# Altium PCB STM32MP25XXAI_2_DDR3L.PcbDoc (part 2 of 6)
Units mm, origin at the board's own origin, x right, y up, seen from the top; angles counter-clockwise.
Board outline 172 x 137 mm, 6 copper layers (Top Layer, Signal Layer 1, Signal Layer 2, Signal Layer 3, Signal Layer 4, Bottom Layer), stack 2.079 mm thick; 237 components, 152 nets, 1304 pads, 909 vias.
Unrouted connection lines stored in the file: 13.

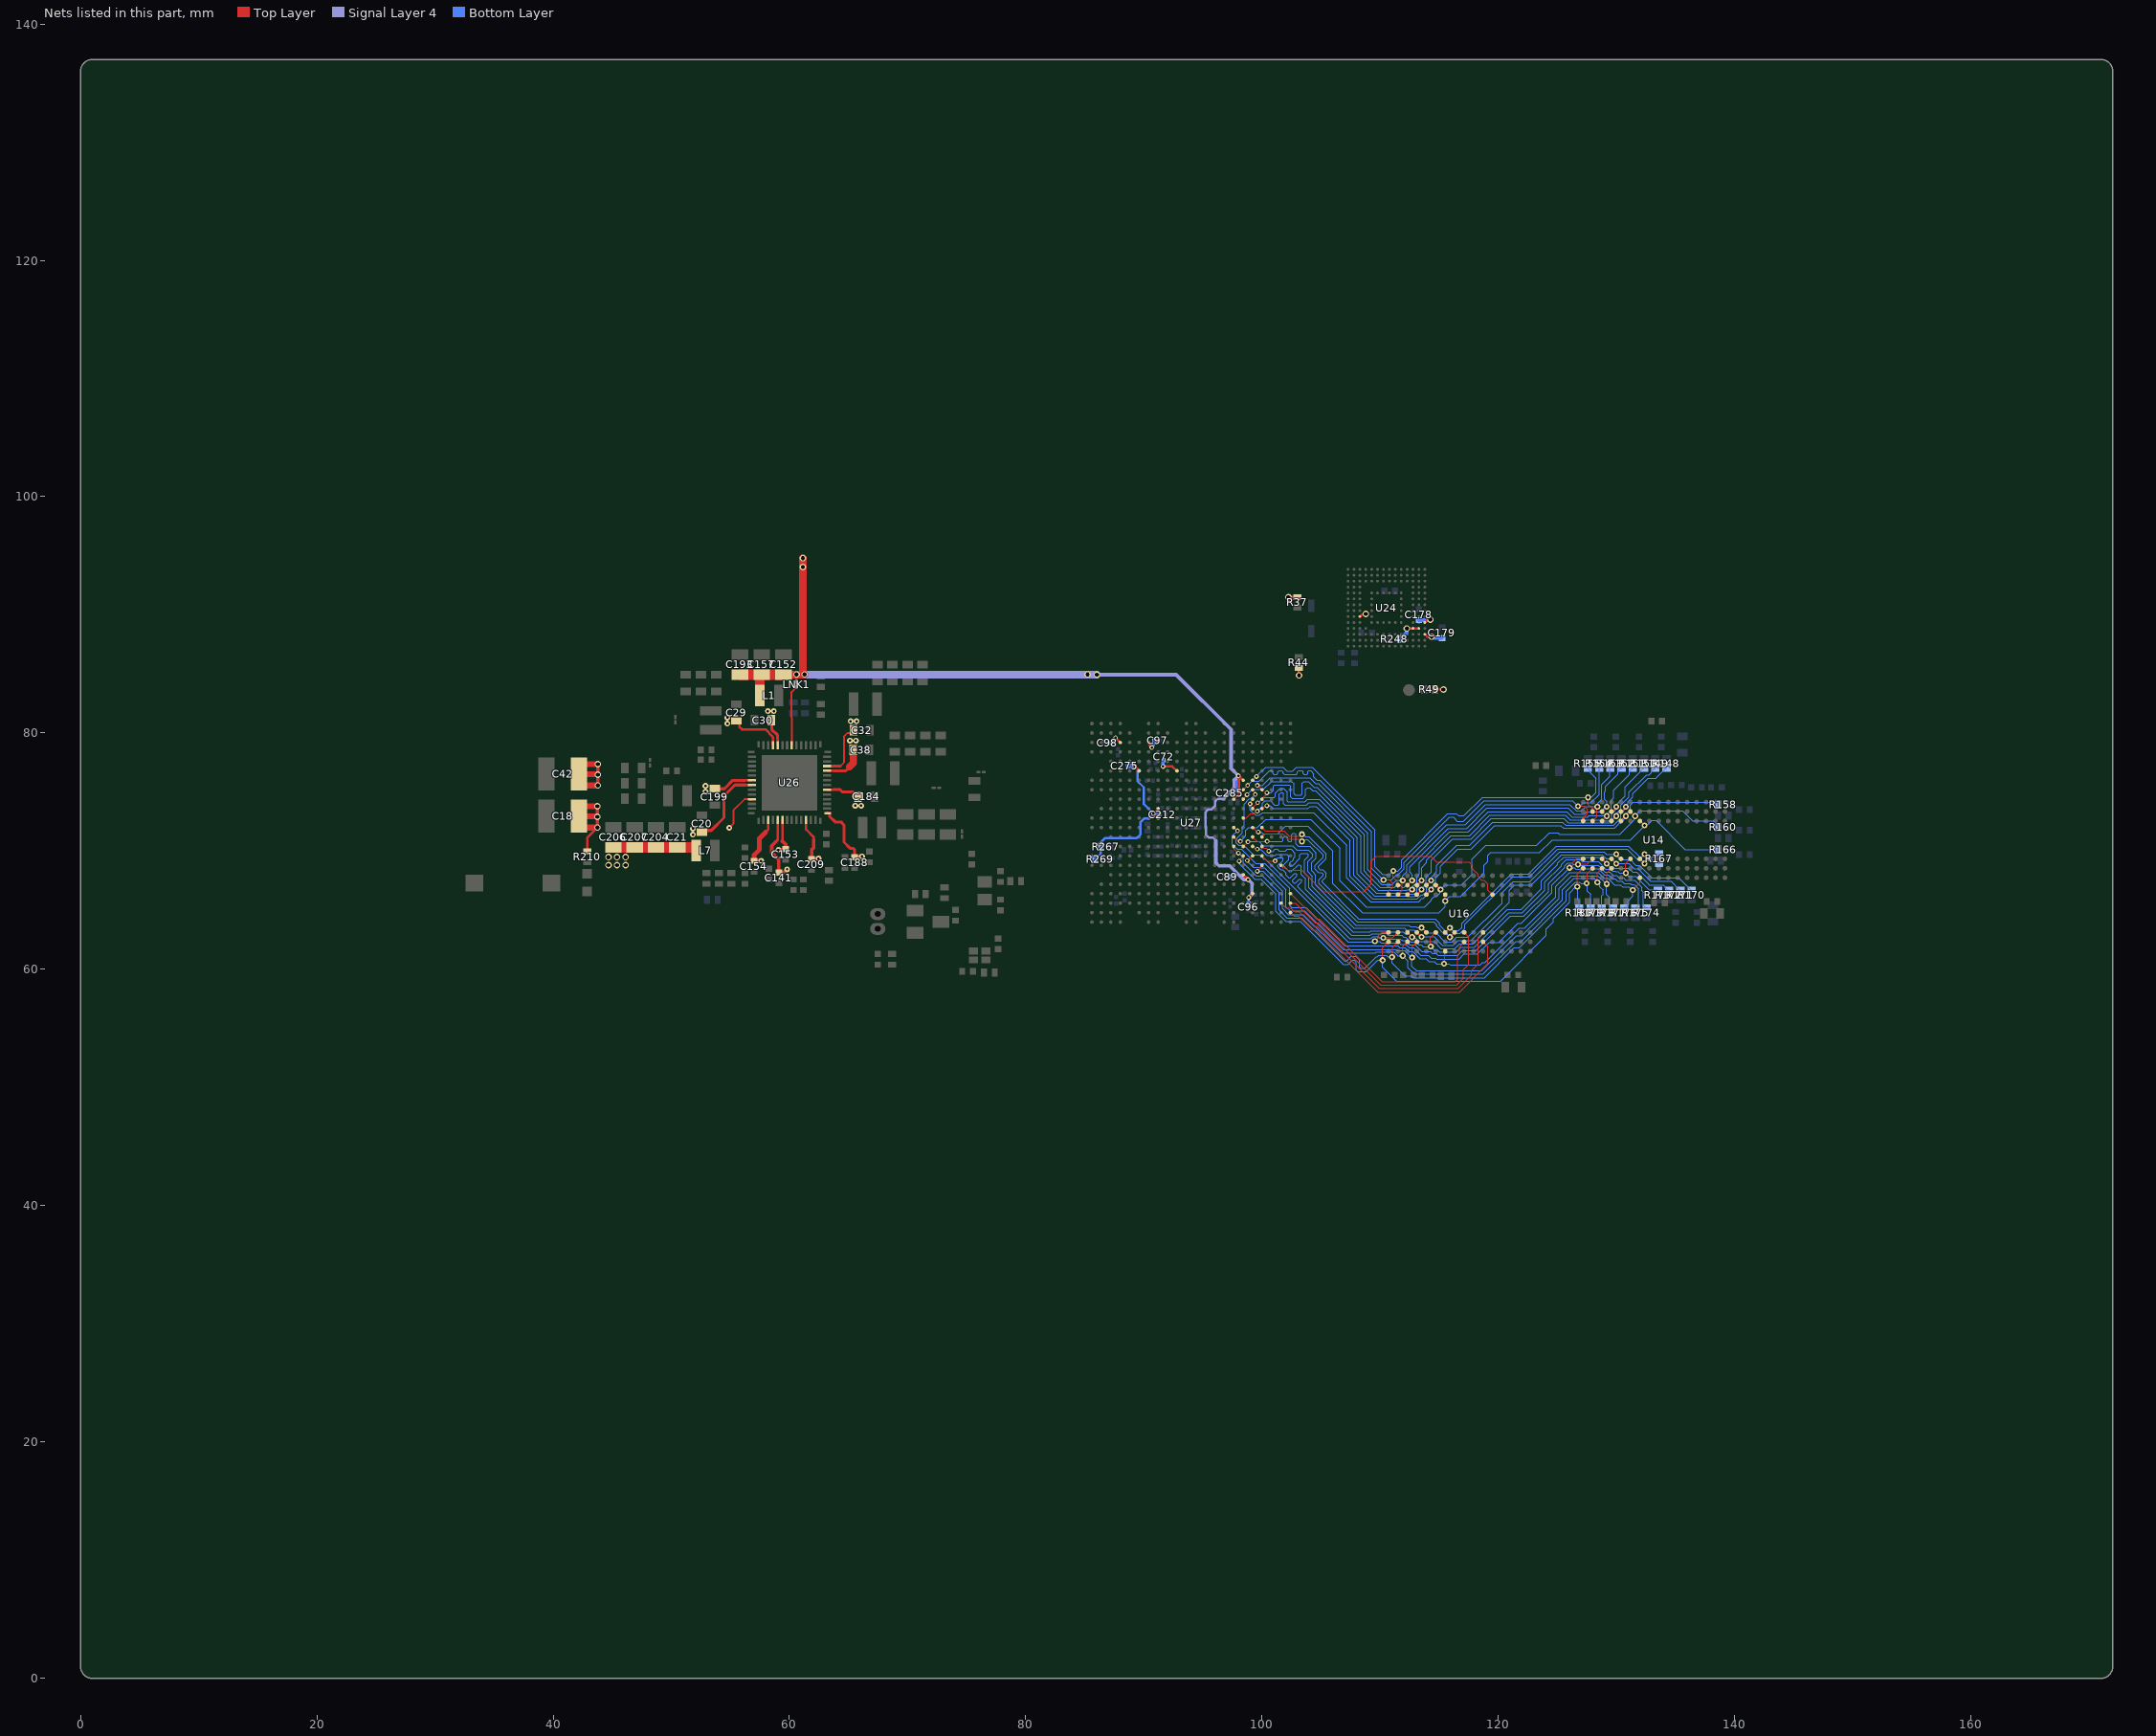
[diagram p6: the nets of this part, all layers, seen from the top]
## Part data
B2: library part MCD-03492, "Switch tactile, SPST-NO, 50mA, 12V, 6x3.8mm", Manufacturer="WURTH ELEKTRONIK", Manufacturer_Part_Number=434121025816, Package=6x3.8mm
C1 C2 C3 C4 C5 C6 C7 C8 C9 C10 C11 C12 C13 C14 C15 C16 C17 C25 C31 C44 C45 C46 C47 C52 C53 C54 C55 C56 C57 C58 C59 C60 C67: library part MCD-02377, "Capacitor, MLCC, 1uF, 6.3V, X5R, +/-20%, 0201, T=0,3mm", Alternate_Manufacturer=N/A, Manufacturer=MURATA, Manufacturer_Part_Number=GRM033R60J105MEA2, Package=0201
C18 C42: library part MCD-01796, "Capacitor, Tantalum, 100uF, 6V3, 40mR, +/-20%,  Type_B (3528 metric), T=1.9mm", Manufacturer=AVX, Manufacturer_Part_Number=TCJB107M006R0040, Package="3528 (metric)"
C19 C21 C152 C157 C186 C187 C193 C204 C206 C207: library part MCD-03139, "Capacitor, MLCC, 22uF, 10V, X5R, +/-20%, 0805, T=1,25mm", Manufacturer=MURATA, Manufacturer_Part_Number=GRM21BR61A226ME51L, Package=0805
C20 C29 C30 C32 C38 C184 C199: library part MCD-00099, "Capacitor, MLCC, 10uF, 10V, X5R, +/-10%, 0603, T=0,8mm", Alternate_Manufacturer=N/A, Manufacturer=MURATA, Manufacturer_Part_Number=GRM188R61A106KE69D, Package=0603
C22 C23 C24 C26 C27 C28 C34 C35 C36 C37 C41 C183 C200 C202: library part MCD-00100, "Capacitor, MLCC, 22uF, 6V3, X5R, +/-20%, 0603, T=0,8mm", Alternate_Manufacturer=N/A, Manufacturer=MURATA, Manufacturer_Part_Number=GRM188R60J226MEA0J, Package=0603
C33: library part MCD-00011, "Capacitor, MLCC, 10nF, 16V, X7R, 10%, 0402, T=0.5mm", Manufacturer=YAGEO, Manufacturer_Part_Number=CC0402KRX7R7BB103, Package=0402
C39 C40: library part MCD-03140, "Capacitor, MLCC, 10uF, 6.3V, X5R, +/-20%, 0402, T=0.5mm", Manufacturer=MURATA, Manufacturer_Part_Number=GRM155R60J106ME05D, Package=0402
C43 C153 C154 C188: library part MCD-00095, "Capacitor, MLCC, 1uF, 25V, X5R, +/-10%, 0402, T=0.5mm", Manufacturer=MURATA, Manufacturer_Part_Number=GRM155R61E105KA12, Package=0402
C48 C76 C77 C131 C132 C133 C134 C143 C146 C147 C148 C149 C159 C172 C177 C179 C182 C185 C191 C192 C194 C201 C205 C302 C304 C306 C307 C360 C361 C362 C363 C367 C373 C374 C375 C384 C390: library part MCD-00006, "Capacitor, MLCC, 100nF, 16V, X7R, +/-10%, 0402, T=0.5mm", Alternate_Manufacturer=MURATA, Alternate_Manufacturer_Part_Number=GCM155R71C104KA55D, Manufacturer=YAGEO, Manufacturer_Part_Number=CC0402KRX7R7BB104, Package=0402
C61: library part MCD-01534, "Capacitor, MLCC, 4,7uF, 6V3, X5R, +/-20%, 0201, T=0.5mm", Alternate_Manufacturer=N/A, Manufacturer=MURATA, Manufacturer_Part_Number=GRM035R60J475ME15, Package=0201
C62 C63 C64 C65 C66 C68 C69 C70 C71 C72 C73 C74 C75 C89 C96 C97 C98 C212 C234 C275 C285: library part MCD-01535, "Capacitor, MLCC,100nF, 10V, X7R, +/-10%, 0201, T=0.3mm", Alternate_Manufacturer=N/A, Manufacturer=MURATA, Manufacturer_Part_Number=GRM033R61A104KE15, Package=0201
C79: library part MCD-02235, "Capacitor, MLCC, 2.2uF, 10V, X5R,+/-10%, 0201, T=0.5mm", Manufacturer=MURATA, Manufacturer_Part_Number=GRM033R61A225KE47D, Package=0201
C80 C140 C173 C364: library part MCD-00099, "Capacitor, MLCC, 10uF, 10V, X5R, +/-10%, 0603, T=0.8mm", Alternate_Manufacturer=N/A, Manufacturer=MURATA, Manufacturer_Part_Number=GRM188R61A106KE69D, Package=0603
C81 C86 C90 C92: library part MCD-00674, "Capacitor, MLCC, 6.8pF, 50V, NPO, +-0.25pF, 0402, T=0.5mm", Alternate_Manufacturer=N/A, Manufacturer=YAGEO, Manufacturer_Part_Number=CC0402CRNPO9BN6R8, Package=0402
C87: library part MCD-00006, "Capacitor,100nF,16V,X7R,10%,0402", Alternate_Manufacturer=MURATA, Alternate_Manufacturer_Part_Number=GCM155R71C104KA55D, Manufacturer=YAGEO, Manufacturer_Part_Number=CC0402KRX7R7BB104, Package=0402
C88: library part MCD-01823, "Capacitor, MLCC, 2.2uF, 6V3, X5R,+/-10%, 0402, T=0.5mm", Alternate_Manufacturer=N/A, Manufacturer=MURATA, Manufacturer_Part_Number=GRM155R60J225KE95D, Package=0402
C91 C141 C142 C156 C189 C190 C208 C209 C217: library part MCD-01356, "Capacitor, MLCC, 4.7uF, 6V3, X5R, +/-20%, 0402, T=0.5mm", Manufacturer=MURATA, Manufacturer_Part_Number=GRM155R60J475ME47, Package=0402
C130 C399: library part MCD-00099, "Capacitor, MLCC, 10uF, 10V, X5R, +/-10%, 0603, T=0.8mm", Manufacturer=MURATA, Manufacturer_Part_Number=GRM188R61A106KE69D, Package=0603
C155: library part MCD-02198, "Capacitor, MLCC, 10nF, 50V, X7R, +/-10%, 0402, T=0.5mm", Manufacturer=YAGEO, Manufacturer_Part_Number=CC0402KRX7R9BB103, Package=0402
C178 C180 C181: library part MCD-02606, "Capacitor, MLCC, 2.2uF, 6.3V, X5R, +/-10%, 0402, T=0.5mm", Manufacturer=YAGEO, Manufacturer_Part_Number=CC0402KRX5R5BB225, Package=0402
CN12: library part MCD-00655, "Header 2 circuits, 1.25mm Pitch ,  Vertical, with Friction Lock", Alternate_Manufacturer=N/A, Manufacturer=MOLEX, Manufacturer_Part_Number=53047-0210
D5: library part MCD-00034, Manufacturer=STMICROELECTRONICS, Manufacturer_HQ_COO=EU, Package=SOD323
D6: library part MCD-03280, "Diode, Schottky, Dual Common Cathode, 0V3, 300mA, 40V, SOT-23", Manufacturer=STMICROELECTRONICS, Manufacturer_Part_Number=BAT54CFILM, Package=SOT23
L1 L6: library part MCD-03143, "Inductor, 2.2uH, +/-20%, Itemp= 1700mA, Isat= 2400mA, 0R140, 0806, T=1mm", Manufacturer=MURATA, Manufacturer_Part_Number=DFE201610E-2R2M{}P2, Package=0806
L2 L4: library part MCD-03142, "Inductor, 0.68uH, +/-20%, Itemp= 3900mA, Isat= 5400mA, 0R031, 1008, T=1.2mm", Manufacturer=MURATA, Manufacturer_Part_Number=DFE252012F-R68M{}P2, Package=1008
L3 L5 L7: library part MCD-03141, "Inductor, 0.68uH, +/-20%, Itemp= 3100mA, Isat= 4300mA, 0R043, 0806, T=1mm", Manufacturer=MURATA, Manufacturer_Part_Number=DFE201610E-R68M{}P2, Package=0806
LD11: library part MCD-00588, "LED Green, 0603 SMD, Forward Voltage Typ=2V, Max=2.5V", Alternate_Manufacturer="VISHAY SEMICONDUCTOR OPTO DIVISION", Alternate_Manufacturer_Part_Number=VLMTG1300-GS08, Manufacturer="OSRAM OPTO SEMICONDUCTORS", Manufacturer_Part_Number="LG Q396-PS-35", Package=0603
LNK1 LNK2 LNK4 LNK7 LNK8 LNK11: library part MCD-02777, "Track link on PCB 200um width for layout routing", Manufacturer=N/A
R2 R46 R57 R59 R60 R64 R75 R81 R267 R269 R286: library part MCD-00052, "Resistor,0R,0402,5%,1/16W", Alternate_Manufacturer=N/A, Manufacturer=YAGEO, Manufacturer_Part_Number=RC0402JR-070RL, Package=0402
R27 R272: library part MCD-00053, "Resistor,10K,0402,1%,1/16W", Alternate_Manufacturer=N/A, Manufacturer=YAGEO, Manufacturer_Part_Number=RC0402FR-0710KL, Package=0402
R37 R44 R49 R156 R248: library part MCD-00053, "Resistor,10K,0402,1%,1/16W", Manufacturer=YAGEO, Manufacturer_Part_Number=RC0402FR-0710KL, Package=0402
R66: library part MCD-00058, "Resistor, 20R, 0402, +/-1%, 1/16W", Alternate_Manufacturer=N/A, Manufacturer=YAGEO, Manufacturer_Part_Number=RC0402FR-0720RL, Package=0402
R67: library part MCD-00052, "Resistor, 0R, 0402, +/-5%, 1/16W", Manufacturer=YAGEO, Manufacturer_Part_Number=RC0402JR-070RL, Package=0402
R68 R83: library part MCD-00120, "Resistor,240R,0402,1%,1/16W", Manufacturer=YAGEO, Manufacturer_Part_Number=RC0402FR-07240RL, Package=0402
R148 R149 R150 R151 R152 R153 R154 R155 R158 R159 R160 R163 R166 R168 R170 R171 R172 R173 R174 R175 R176 R177 R178 R179 R180: library part MCD-00054, "Resistor, 56R, 0402, +/-1%, 1/16W", Alternate_Manufacturer=N/A, Manufacturer=YAGEO, Manufacturer_Part_Number=RC0402FR-0756RL, Package=0402
R167: library part MCD-01819, "Resistor,100R,0402,0,5%,1/16W,±100ppm/°C", Manufacturer=YAGEO, Manufacturer_Part_Number=RC0402DR-07100RL, Package=0402
R210: library part MCD-00441, "Resistor,270R,0402,1%,1/16W", Manufacturer=YAGEO, Manufacturer_Part_Number=RC0402FR-07270RL, Package=0402
R249: library part MCD-00056, "Resistor, 0R, 0603, +/-5%, 1/10W", Manufacturer=YAGEO, Manufacturer_Part_Number=RC0603JR-070RL, Package=0603
R260 R261: library part MCD-00068, "Resistor,1K5,0402,1%,1/16W", Manufacturer=YAGEO, Manufacturer_Part_Number=RC0402FR-071K5L, Package=0402
R262: library part MCD-02253, "Resistor,240R,0201,1%,1/20W", Alternate_Manufacturer=N/A, Manufacturer=YAGEO, Manufacturer_Part_Number=RC0201FR-07240RL, Package=0201
TP9: library part MCD-00074, "Test Point 1mm", Manufacturer=n/a, Manufacturer_HQ_COO=Unknown
U14 U16: library part MCD-01811, "Memory,DDR3L,4Gb,256Mbx16,933Mhz,1V35,TFBGA", Manufacturer=NANYA, Package=VFBGA-96
U24: library part MCD-02799, "Memory, eMMC, 4GB, 15nm ,WFBGA , 153 pins", Manufacturer=KIOXIA, Manufacturer_Part_Number=THGBMTG5D1LBAIL, Package=WFBGA153
U26: library part MCD-03000, "STPMIC2", Manufacturer=STMICROELECTRONICS, Package=VQFN
U27: library part MCD-02000, "MPU, ARM Cortex-A35 + M33 32-bit MPU, 808KB RAM, With Crypto", Manufacturer=STMICROELECTRONICS, Manufacturer_HQ_COO=EU, Package=LFBGA-436
X1: library part MCD-01479, "Crystal, 32.768kHz, 6pF, +/-20ppm, 80K, 2.05x1.2mm", Manufacturer=NDK, Manufacturer_Part_Number=NX2012SA-32.768KHZ-EXS00A-MU00527, Package=2.05x1.2mm
X2: library part MCD-02344, "Crystal, 40MHz, 6pF, +/-20ppm, 80R, 1.6x1.2mm", Manufacturer=NDK, Manufacturer_Part_Number=NX1612SA-40MHZ-EXS00A-CS13836, Package=1.6x1.2mm

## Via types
v1: diameter 0.55, hole 0.35, Top Layer to Bottom Layer, 421 vias
v2: diameter 0.4, hole 0.2, Top Layer to Bottom Layer, tented both sides, 169 vias
v3: diameter 0.5, hole 0.2, Top Layer to Bottom Layer, 146 vias
v4: diameter 0.5, hole 0.25, Top Layer to Bottom Layer, 145 vias
v5: diameter 0.4, hole 0.2, Top Layer to Bottom Layer, 28 vias

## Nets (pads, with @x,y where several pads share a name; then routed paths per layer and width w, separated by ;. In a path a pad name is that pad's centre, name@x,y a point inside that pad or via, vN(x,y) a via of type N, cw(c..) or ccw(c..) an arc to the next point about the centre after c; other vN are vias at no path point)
1V8: C72.2 C89.2 C96.2 C97.2 C98.2 C152.2 C157.2 C178.2 C179.2 C193.2 C212.2 C275.2 C285.2 L1.2 LNK1.2 R37.2 R44.2 R49.2 R248.2 R267.2 R269.1 U24.C6 U24.M4 U24.N4 U24.P3 U24.P5 U27.C4 U27.C7 U27.F6 U27.F10 U27.G17 U27.J16 U27.K8 U27.L8 U27.U17 U27.W18 | length 110.6
  Top Layer w0.2: LNK1.2@60.6,84.348 v1(60.6,84.95) ; v2(87.6,79.6) U27.C4@88,79.2 v2(87.6,79.6) ; v2(89.2,77.2) U27.F6@89.6,76.8 ; U27.C7@90.4,79.2 90.415,79.185 90.415,79.02 v2(90.66,78.775) ; U27.L8@91.2,72.8 91.175,72.8 v2(90.8,73.175) 91.2,73.575 U27.K8@91.2,73.6 ; v2(91.624,77.173) 92.413,77.173 92.786,76.8 U27.F10@92.8,76.8 ; U27.J16@97.6,74.4 98,74.8 v2(98,76.375) 98.012,76.375 98.388,76 U27.G17@98.4,76 ; U27.U17@98.4,68 v2(98.8,67.6) ; v2(98.868,66.067) U27.W18@99.2,66.4 ; v1(102.23,91.5) R37.2@102.975,91.5 ; R44.2@103.1,85.528 103.125,85.503 v1(103.125,84.875) ; U24.C6@108.275,89.85 108.452,90.027 108.727,90.027 v1(108.775,90.075) ; v1(112.25,88.85) U24.M4@112.775,88.85 U24.N4@113.275,88.85 ; U24.P3@113.775,88.35 113.975,88.15 v1(114.35,88.15) ; U24.P5@113.775,89.35 114.005,89.58 114.23,89.58 v1(114.25,89.6) ; R49.2@114.625,83.685 v1(115.35,83.685)
  Top Layer w0.64: C152.2@59.5,84.95 v1(60.6,84.95) v1(61.28,84.95) 61.142,85.088 v1(61.142,94.8)
  Top Layer w0.8: L1.2@57.495,83.175 57.495,84.9 57.545,84.95 C157.2@57.65,84.95
  Top Layer w0.9: C193.2@55.8,84.95 C157.2@57.545,84.95 ; C157.2@57.65,84.95 C152.2@59.5,84.95
  Signal Layer 4 w0.2: 96.075,70.9 95.825,71.15 95.484,71.15 95.399,71.235 95.248,71.386 95.248,72.063 95.201,72.109 95.201,73.292 95.317,73.408 95.317,73.433 95.434,73.55 95.723,73.55 96.007,73.834 96.007,74.166 96.003,74.169 96.257,74.423 96.684,74.423 ; v2(98.868,66.067) v2@98.868,66.094
  Signal Layer 4 w0.3: v1(86.019,84.939) 92.721,84.939 97.371,80.289 97.371,77.004 v2(98,76.375) ; 96.075,70.9 96.075,69.048 96.075,69.014 96.339,68.75 97.262,68.75 98.412,67.6 v2(98.8,67.6) ; 96.684,74.423 97.65,75.389 97.65,76.018 v2@98,76.367 ; v2(98.8,67.6) 99.15,67.25 99.15,66.377 v2@98.868,66.094
  Signal Layer 4 w0.64: v1@60.6,84.955 v1@61.28,84.955 ; v1(61.28,84.95) 86.009,84.95 v1(86.019,84.939)
  Bottom Layer w0.17: C89.2@97.35,67.825 97.415,67.89 97.44,67.89 97.56,68.01 98.39,68.01 v2(98.8,67.6)
  Bottom Layer w0.2: R269.1@85.854,69.315 85.854,69.41 86.009,69.565 86.104,69.565 86.35,69.811 R267.2@86.35,70.375 ; R267.2@86.325,70.715 86.697,71.087 89.377,71.087 89.723,71.434 89.723,72.448 90.059,72.783 90.457,72.783 90.8,73.127 v2(90.8,73.175) ; v2(89.2,77.2) 89.458,76.942 89.458,75.927 89.985,75.4 89.985,73.99 v2(90.8,73.175) ; v2(90.66,78.775) 90.66,78.79 90.825,78.955 C97.2@90.825,79.375 ; C212.2@91.31,73.1 91.272,73.138 90.837,73.138 v2(90.8,73.175) ; C96.2@98.85,65.55 98.85,66.05 v2(98.868,66.067)
  Bottom Layer w0.3: C98.2@87.175,79.175 v2(87.6,79.6) ; C72.2@91.6,77.7 91.6,77.224 91.624,77.2 v2(91.624,77.173) ; C285.2@97.555,74.91 97.94,75.295 97.94,76.288 98,76.348 v2(98,76.375) ; R248.2@111.675,87.95 112.241,88.516 112.241,88.841 v1(112.25,88.85) ; C178.2@113.275,89.55 114.132,89.55 114.182,89.6 v1(114.25,89.6) ; v1(114.35,88.15) 114.418,88.15 114.543,88.025 C179.2@115.225,88.025
  Bottom Layer w0.4: C275.2@88.675,77.2 v2(89.2,77.2)
  other v1: 85.224,84.95 61.131,94.047
1V8_FB: LNK1.1 U26.35 | length 5.1
  Top Layer w0.15: U26.35@60.2,78.97 60.2,81.311 60.175,81.336 60.175,83.473 LNK1.1@60.6,83.898
3V3: C21.2 C154.2 C204.2 C206.2 C207.2 L7.2 U26.3 U26.53 | length 15.3
  Top Layer w0.15: v3(54.91,71.977) 55.262,72.329 55.262,73.465 56.197,74.4 U26.53@56.83,74.4 ; U26.53@56.62,74.369 56.919,74.369 U26.53@56.95,74.4
  Top Layer w0.21: 57.973,71.598 58.2,71.825 U26.3@58.2,72.63
  Top Layer w0.3: C154.2@56.975,69.175 C154.2@57,69.175 v3@57.585,69.175
  Top Layer w0.4: C154.2@57,69.175 57.014,69.189 57.014,69.685 57.46,70.131 57.46,71.085 57.973,71.598
  Top Layer w0.9: C206.2@45.087,70.323 C21.2@50.5,70.323 51.862,70.323 L7.2@51.887,70.298
  other v1: 44.687,68.823 45.412,68.823 46.137,68.823 44.687,69.498 45.412,69.498 46.137,69.498
  other v3: 57.61,69.175
5V_STLK: C18.1 C20.2 C29.2 C30.2 C32.2 C38.2 C42.1 C153.2 C184.2 C188.2 C199.2 C209.2 R210.1 U26.6 U26.11 U26.15 U26.20 U26.24 U26.25 U26.38 U26.39 U26.49 U26.50 | length 56.5
  Top Layer w0.15: 64.3,77.2 64.625,77.525 64.625,79.731 64.888,79.994 65.319,79.994 C32.2@65.425,80.1
  Top Layer w0.2: R210.1@42.887,69.97 42.887,71.138 v1(43.751,72.002)
  Top Layer w0.21: C29.2@55.525,81.05 55.762,80.813 55.762,80.513 55.975,80.3 57.964,80.3 58.6,79.664 U26.39@58.6,78.97 ; 56.275,75.6 U26.50@56.83,75.6 ; 56.275,76 U26.49@56.83,76 ; U26.38@59,78.97 59,79.525 ; 59.4,70.85 U26.6@59.4,72.63 ; U26.11@61.4,72.63 61.4,71.843 62.04,71.203 62.04,70.975 ; U26.15@63.17,73.2 U26.15@63.245,73.2 U26.15@63.285,73.2 ; U26.20@63.17,75.2 63.725,75.2 ; U26.24@63.17,76.8 63.725,76.8 ; U26.25@63.17,77.2 64.3,77.2
  Top Layer w0.25: C20.2@52.6,71.75 53.375,71.75 54.45,72.825 54.45,74.669 55.381,75.6 56.275,75.6 ; C199.2@53.675,75.275 54.491,75.275 55.216,76 56.275,76 ; C30.2@58.425,81.075 58.494,81.006 58.494,80.308 59,79.802 59,79.525 ; 63.395,73.095 63.395,72.947 63.871,72.472 64.353,72.472 64.625,72.2 64.625,70.759 65.134,70.25 65.379,70.25 65.525,70.104 C188.2@65.525,69.55 ; 63.725,75.2 64.288,75.2 64.463,75.025 65.347,75.025 65.472,74.9 65.55,74.9 65.747,74.703 C184.2@65.747,74.625 ; 63.725,76.8 64.75,76.8 65.075,77.125
  Top Layer w0.3: v1(43.751,72.002) v1(43.751,72.902) v1(43.751,73.802) ; v1(43.776,75.565) v1(43.776,76.465) v1(43.776,77.365) ; v3(59.065,70.11) 59.675,70.11 59.674,70.111 59.674,70.576 59.4,70.85 ; C209.2@61.85,69.38 C209.2@61.875,69.38 ; 62.04,70.975 62.04,70.269 61.875,70.104 C209.2@61.875,69.38 ; v3(62.46,69.38) C209.2@61.875,69.38 ; C188.2@65.525,69.55 v3(66.135,69.55)
  Top Layer w0.5: C18.1@42.187,72.049 42.235,72.002 v1(43.751,72.002) ; C18.1@42.187,72.961 43.679,72.961 43.737,72.902 v1(43.751,72.902) ; C42.1@42.187,75.612 42.235,75.565 v1(43.776,75.565) ; C42.1@42.187,76.523 43.704,76.523 43.762,76.465 v1(43.776,76.465) ; C18.1@42.246,73.802 v1(43.751,73.802) ; C42.1@42.246,77.365 v1(43.776,77.365)
  Top Layer w0.6: 65.075,77.125 65.4,77.45 C38.2@65.4,78.175
  other v3: 51.825,71.4 51.825,71.9 65.575,73.85 66.075,73.85 52.9,75.025 52.9,75.525 65.125,79.35 65.625,79.35 54.75,80.8 65.175,81 65.675,81 54.75,81.3 58.175,81.85 58.675,81.85
5V_VCONN: C141.1 U26.5 | length 5.7
  Top Layer w0.21: 58.877,70.828 59,70.95 U26.5@59,72.63
  Top Layer w0.3: 58.877,70.828 58.51,70.46 58.51,69.865 59.1,69.275 C141.1@59.1,68.2 59.539,68.2 v3(59.8,68.46)
DDR_A0: R149.1 U14.N3 U16.N3 U27.L17 | length 50.4
  Top Layer w0.09: U27.L17@98.4,72.8 98.673,72.8 99.037,73.164 99.374,73.164 v5(99.6,73.39) ; U16.N3@113.101,66.327 113.101,66.376 v4@113.5,66.775 ; U14.N3@129.576,72.552 129.576,72.601 v4@129.975,73
  Bottom Layer w0.09: v5@99.603,73.39 100.016,73.803 100.016,74.043 100.219,74.246 100.712,74.246 101.058,73.9 101.348,73.9 101.443,73.995 101.443,74.811 101.603,74.971 101.748,74.971 101.833,74.886 101.833,74.017 101.95,73.9 103.774,73.9 103.962,74.088 104.682,74.088 105.043,73.727 ; 105.05,73.734 107.755,71.029 107.755,67.967 109.502,66.22 112.251,66.22 112.32,66.151 112.967,66.151 113.5,66.685 v4(113.5,66.745) 113.5,66.818 113.715,67.033 113.715,67.097 113.895,67.277 113.895,67.808 114.336,68.25 114.336,69.245 116.116,71.025 117.679,71.025 119.404,72.75 125.544,72.75 125.912,72.382 129.422,72.382 129.975,72.935 v4(129.975,72.97) v4@129.975,73 ; v4@129.976,73.013 129.976,73.139 130.37,73.534 130.37,73.908 131.064,74.602 131.064,74.979 132.537,76.452 132.751,76.452 132.971,76.672 132.971,76.767 133.181,76.977 R149.1@133.276,76.977
DDR_A1: R172.1 U14.P7 U16.P7 U27.P19 | length 48.6
  Top Layer w0.09: U27.P19@100.005,70.4 100.168,70.237 100.338,70.237 v5(100.575,70) ; U16.P7@112.301,63.127 v4(112.7,62.725) ; U14.P7@128.776,69.352 v4@129.176,68.952
  Bottom Layer w0.09: v5(100.575,70) 100.585,69.99 100.909,69.99 101.096,70.177 101.282,70.177 101.432,70.027 101.968,70.027 102.118,70.177 102.453,70.177 102.802,69.827 102.802,69.539 102.652,69.388 102.652,69.283 102.349,68.98 102.349,68.846 102.424,68.772 102.566,68.772 103.197,69.402 103.197,69.689 103.327,69.82 103.784,69.82 103.903,69.7 103.903,69.576 103.586,69.258 103.586,68.134 103.953,67.766 103.953,66.903 107.68,63.177 109.148,63.177 109.231,63.26 110.6,63.26 110.683,63.177 111.946,63.177 112.101,63.022 112.406,63.022 v4@112.672,62.756 ; v4@112.685,62.769 112.7,62.754 112.7,62.728 v4(112.7,62.725) 112.763,62.662 113.002,62.662 113.32,62.344 114.55,62.344 115.145,61.75 116.304,61.75 116.711,62.157 117.833,62.157 120.761,65.085 121.919,65.085 123.64,66.806 123.64,67.493 125.03,68.884 125.03,68.984 125.538,69.492 128.592,69.492 129.134,68.95 v4(129.175,68.95) 129.175,68.931 129.439,68.667 129.669,68.667 129.782,68.554 131.028,68.554 131.372,68.211 131.69,68.211 132.659,67.242 132.673,67.242 132.765,67.15 133.959,67.15 134.145,66.964 134.145,66.905 R172.1@134.45,66.6
DDR_A2: R151.1 U14.P3 U16.P3 U27.J19 | length 47.1
  Top Layer w0.09: U27.J19@100,74.4 100,74.438 100.341,74.779 100.341,74.891 v5(100.4,74.95) ; U16.P3@112.301,66.327 112.7,66.726 v4(112.7,66.745) ; U14.P3@128.776,72.552 129.175,72.951 v4(129.175,72.97)
  Bottom Layer w0.09: v5@100.403,74.95 100.747,74.95 100.95,75.153 100.95,75.501 101.051,75.602 102.305,75.602 102.413,75.494 102.413,74.594 102.527,74.48 103.461,74.48 103.689,74.708 103.689,75.224 103.824,75.359 104.044,75.359 104.287,75.115 104.517,75.115 108.355,71.278 108.355,68.187 109.842,66.7 112.213,66.7 112.258,66.745 v4(112.7,66.745) 112.778,66.823 112.778,67.042 113.095,67.358 113.095,67.845 113.168,67.918 113.168,67.92 113.3,68.052 113.3,69.057 ; 113.299,69.057 115.867,71.625 117.43,71.625 119.155,73.35 125.793,73.35 126.241,72.902 127.573,72.902 127.668,72.997 v4@129.172,72.997 ; v4(129.175,72.97) 129.175,73.095 129.57,73.49 129.57,74.31 129.765,74.505 129.765,75.167 131.071,76.472 131.071,76.767 131.281,76.977 R151.1@131.376,76.977
DDR_A3: R150.1 U14.N2 U16.N2 U27.K18 | length 47.8
  Top Layer w0.09: U27.K18@99.2,73.6 99.2,73.65 v5@99.625,74.075 ; U16.N2@113.101,67.127 113.476,67.502 v4@113.476,67.527 ; U14.N2@129.575,73.35 v4(129.975,73.75)
  Bottom Layer w0.09: v5@99.625,74.063 100.109,74.546 101.03,74.546 101.14,74.656 101.14,74.918 101.524,75.302 101.828,75.302 102.123,75.007 102.123,74.238 102.171,74.19 103.654,74.19 103.842,74.378 104.83,74.378 108.055,71.153 108.055,68.077 109.672,66.46 112.315,66.46 112.425,66.35 112.864,66.35 113.095,66.581 113.095,66.899 113.31,67.114 113.31,67.267 113.5,67.457 v4(113.5,67.525) 113.505,67.53 113.505,68.614 113.916,69.025 113.916,69.249 115.992,71.325 117.554,71.325 119.279,73.05 125.669,73.05 126.075,72.644 128.943,72.644 129.011,72.575 129.339,72.575 129.58,72.816 129.58,73.164 129.897,73.48 129.897,73.672 v4(129.975,73.75) ; v4@130.018,73.956 130.712,74.651 130.712,75.438 132.021,76.746 132.021,76.767 132.231,76.977 R150.1@132.326,76.977
  other v5: 99.625,74.1
DDR_A4: R178.1 U14.P8 U16.P8 U27.T19 | length 43.4
  Top Layer w0.09: v5(99.6,68.3) 99.6,68.302 99.798,68.501 99.798,68.591 U27.T19@100,68.793 ; v4(111.9,61.145) 111.901,61.927 U16.P8@112.301,62.327 ; v4(128.375,67.35) 128.376,68.152 U14.P8@128.776,68.552
  Bottom Layer w0.09: v5(99.6,68.3) 100.063,68.3 101.734,66.629 101.734,65.145 102.237,64.642 103.471,64.642 106.736,61.377 109.575,61.377 109.65,61.452 111.181,61.452 111.488,61.145 v4(111.9,61.145) 112.36,60.685 112.36,60.134 112.904,59.59 118.694,59.59 121.482,62.378 121.92,62.378 125.44,65.898 125.44,66.748 126.377,67.685 128.101,67.685 128.375,67.411 v4(128.375,67.35) 128.375,67.34 128.573,67.142 128.573,66.992 128.846,66.72 128.846,66.347 128.743,66.244 128.743,65.232 R178.1@128.75,65.225
DDR_A5: R152.1 U14.P2 U16.P2 U27.J17 | length 48.4
  Top Layer w0.09: U27.J17@98.4,74.4 98.4,74.438 98.725,74.763 v5(98.725,74.775) ; U16.P2@112.302,67.127 v4(112.7,67.525) ; U14.P2@128.776,73.352 128.777,73.352 v4(129.175,73.75)
  Bottom Layer w0.09: v5(98.725,74.775) 99.174,75.224 100.113,75.224 100.791,75.902 102.504,75.902 102.703,75.703 102.703,74.866 102.799,74.77 103.304,74.77 103.399,74.865 103.399,75.763 103.538,75.902 103.924,75.902 104.411,75.415 104.642,75.415 108.655,71.402 108.655,68.297 108.918,68.034 110.012,66.94 111.189,66.94 111.438,67.189 111.613,67.189 111.701,67.102 ; 111.699,67.1 111.859,66.94 112.029,66.94 112.216,67.127 112.302,67.127 v4(112.7,67.525) 112.7,68.005 112.487,68.218 112.487,68.669 115.743,71.925 117.306,71.925 119.031,73.65 125.917,73.65 126.425,73.142 127.3,73.142 127.503,73.345 128.644,73.345 129.049,73.75 v4(129.175,73.75) 129.191,73.766 129.191,74.172 128.972,74.391 128.972,75.001 129.076,75.105 129.076,75.477 130.121,76.522 130.121,76.767 130.331,76.977 R152.1@130.426,76.977
DDR_A6: R179.1 U14.R8 U16.R8 U27.P16 | length 46.7
  Top Layer w0.09: U27.P16@97.6,70.4 97.624,70.376 97.624,70.155 97.934,69.845 v5(98,69.845) ; v4(111,61.05) 111.047,61.096 111.047,61.872 U16.R8@111.5,62.325 ; v4(127.475,67.275) 127.523,67.323 127.523,68.09 127.976,68.542 U14.R8@127.976,68.552
  Bottom Layer w0.09: v5(98,69.845) 98.4,69.445 98.4,69.012 99.492,67.92 100.025,67.92 101.444,66.5 101.444,65.025 102.117,64.352 103.351,64.352 106.991,60.712 107.147,60.712 107.522,61.087 107.928,61.087 108.242,60.772 108.242,60.182 108.344,60.081 108.688,60.081 109.684,61.077 109.759,61.077 109.854,61.172 110.514,61.172 110.636,61.05 v4(111,61.05) 111,60.516 112.08,59.436 112.648,59.436 112.784,59.3 118.814,59.3 121.338,61.824 121.776,61.824 125.74,65.788 125.74,66.623 126.511,67.395 126.839,67.395 126.985,67.248 127.449,67.248 v4(127.475,67.275) 127.52,67.23 127.52,66.63 127.801,66.349 R179.1@127.801,65.227
DDR_A7: R155.1 U14.R2 U16.R2 U27.G18 | length 43.8
  Top Layer w0.09: U27.G18@99.2,76 v5(99.525,76.325) ; v4(111.1,68.325) 111.1,67.772 111.447,67.425 111.447,67.178 U16.R2@111.5,67.125 ; v4(127.575,74.55) 127.575,73.997 127.969,73.603 127.969,73.356 U14.R2@127.975,73.35
  Bottom Layer w0.09: v5(99.525,76.325) 100.302,77.102 101.791,77.102 102.111,76.782 102.594,76.782 102.914,77.102 104.228,77.102 109.555,71.775 109.555,68.67 110.187,68.038 110.81,68.038 111.097,68.325 v4(111.1,68.325) 111.505,68.325 111.8,68.62 111.8,69.255 115.72,73.175 116.432,73.175 116.616,72.991 117.099,72.991 118.658,74.55 v4(127.575,74.55) 127.615,74.59 127.9,74.59 128.249,74.938 128.249,76.156 127.767,76.638 127.767,76.786 R155.1@127.576,76.977
DDR_A8: R180.1 U14.T8 U16.T8 U27.R17 | length 45.9
  Top Layer w0.09: v5(98.05,69.15) 98.05,69.216 98.4,69.566 U27.R17@98.4,69.6 ; v4(110.2,60.775) 110.2,61.826 U16.T8@110.701,62.327 ; v4(126.675,67) 126.675,68.051 U14.T8@127.176,68.552
  Bottom Layer w0.09: v5@98.05,69.175 98.109,69.116 98.109,68.893 99.372,67.63 99.905,67.63 101.154,66.38 101.154,64.905 101.997,64.062 103.231,64.062 106.871,60.422 107.268,60.422 107.643,60.797 107.808,60.797 107.952,60.652 107.952,59.919 108.08,59.791 108.808,59.791 109.794,60.777 v4@110.2,60.777 ; v4(110.2,60.775) 110.2,60.189 111.379,59.01 120.203,59.01 124.063,62.871 124.063,63.411 124.67,64.017 124.67,64.308 126.03,65.668 126.03,66.458 126.571,67 v4(126.675,67) v4@126.675,66.903 ; v4@126.678,66.903 126.73,66.852 126.73,65.909 126.851,65.788 R180.1@126.851,65.227
DDR_A9: R153.1 U14.R3 U16.R3 U27.H19 | length 45.3
  Top Layer w0.09: v5(99.6,75.575) 99.625,75.575 U27.H19@100,75.2 ; U16.R3@111.501,66.327 111.876,66.702 v4@111.876,67.502 ; U14.R3@127.976,72.552 128.351,72.927 v4@128.351,73.727
  Bottom Layer w0.09: v5@99.605,75.57 100.038,75.57 100.67,76.202 104.049,76.202 104.536,75.715 104.766,75.715 108.955,71.526 108.955,68.421 109.88,67.496 109.88,67.404 110.104,67.18 111.005,67.18 111.351,67.526 v4@111.899,67.526 ; v4(111.9,67.525) 111.9,67.921 112.25,68.271 112.25,68.856 115.619,72.225 117.182,72.225 118.907,73.95 126.041,73.95 126.586,73.405 127.017,73.405 127.389,73.777 128.351,73.777 128.417,73.843 128.417,74.073 128.745,74.401 128.745,75.631 129.442,76.327 129.442,76.943 R153.1@129.476,76.977
  other v4: 128.375,73.75
DDR_A10: R173.1 U14.L7 U16.L7 U27.P18 | length 48.2
  Top Layer w0.09: U27.P18@99.2,70.4 99.254,70.4 99.42,70.234 99.541,70.234 v5(99.6,70.175) ; v4@114.256,61.931 114.256,62.681 U16.L7@114.7,63.125 ; v4(130.775,68.15) 130.775,68.95 U14.L7@131.175,69.35
  Bottom Layer w0.09: v5(99.6,70.175) 99.642,70.133 99.913,70.133 100.409,69.637 101.112,69.637 101.202,69.727 102.095,69.727 102.247,69.575 102.247,69.288 101.84,68.881 101.84,68.724 102.309,68.255 102.477,68.255 103.053,68.83 103.182,68.83 103.296,68.716 103.296,68.014 103.663,67.646 103.663,66.783 107.56,62.887 109.163,62.887 109.296,63.02 110.086,63.02 110.111,63.045 110.51,63.045 110.581,62.974 ; 110.582,62.974 110.679,62.877 111.822,62.877 111.977,62.722 112.14,62.722 112.52,62.342 112.524,62.342 112.536,62.33 113.013,62.33 113.266,62.077 113.47,62.077 113.623,61.924 v4@114.279,61.924 ; 115.024,61.46 115.013,61.46 114.833,61.64 114.561,61.64 114.561,61.644 v4(114.28,61.925) ; 115.024,61.46 116.424,61.46 116.831,61.867 117.968,61.867 120.886,64.785 122.029,64.785 123.94,66.696 123.94,67.369 125.33,68.759 125.33,68.874 125.726,69.27 126.921,69.27 127.081,69.109 128.45,69.109 129.082,68.477 129.496,68.477 129.667,68.305 129.862,68.305 129.913,68.254 130.13,68.254 130.234,68.15 v4(130.775,68.15) 130.775,68.125 131.025,67.875 131.615,67.875 132.741,66.75 R173.1@133.5,66.75 ; v4@114.279,61.924 v4(114.28,61.925)
DDR_A11: R174.1 U14.R7 U16.R7 U27.R19 | length 48.7
  Top Layer w0.09: U27.R19@100,69.6 100.42,69.18 v5(101.105,69.18) ; v4(110.25,62.65) 110.27,62.67 111.045,62.67 U16.R7@111.5,63.125 ; v4(126.725,68.875) 126.751,68.901 127.525,68.901 U14.R7@127.976,69.352
  Bottom Layer w0.09: v5(101.105,69.18) 101.105,69.206 101.326,69.427 101.686,69.427 101.769,69.344 101.769,69.22 101.331,68.782 101.331,68.672 101.585,68.418 101.736,68.418 102.012,68.142 102.012,67.992 102.25,67.754 102.393,67.754 102.762,68.123 102.876,68.123 102.961,68.038 102.961,67.903 102.596,67.538 102.596,67.408 102.693,67.31 102.83,67.31 103.147,67.628 103.271,67.628 103.366,67.533 103.366,67.409 103.047,67.09 103.047,66.956 107.406,62.597 109.212,62.597 109.368,62.753 109.37,62.753 109.386,62.77 109.822,62.77 109.943,62.649 v4(110.25,62.65) 110.3,62.65 v4@110.355,62.595 ; v4@110.401,62.577 111.698,62.577 111.853,62.422 112.143,62.422 112.506,62.059 112.947,62.059 113.501,61.505 114.254,61.505 114.409,61.35 114.713,61.35 114.893,61.17 114.904,61.17 116.544,61.17 116.951,61.577 118.102,61.577 121.02,64.495 122.149,64.495 124.24,66.586 124.24,67.245 125.63,68.635 125.63,68.764 125.861,68.995 126.247,68.995 126.365,68.877 126.826,68.877 126.893,68.809 128.445,68.809 129.028,68.227 129.425,68.227 129.71,67.942 130.006,67.942 130.204,67.745 130.587,67.745 130.773,67.559 131.521,67.559 132.154,66.926 132.154,66.636 132.249,66.541 132.249,65.437 132.459,65.227 R174.1@132.551,65.227
DDR_A12: R171.1 U14.N7 U16.N7 U27.P17 | length 48.9
  Top Layer w0.09: U27.P17@98.4,70.4 v5(98.8,70.8) ; U16.N7@113.101,63.127 113.101,63.102 v4@113.451,62.752 ; U14.N7@129.576,69.352 129.576,69.327 129.953,68.95 v4(129.975,68.95)
  Bottom Layer w0.09: v5@98.801,70.802 99.743,70.802 100.068,70.477 102.577,70.477 102.944,70.11 103.904,70.11 104.276,69.737 104.276,69.539 103.876,69.138 103.876,68.254 104.243,67.886 104.243,67.023 107.761,63.506 112.041,63.506 112.226,63.322 112.881,63.322 113.463,62.74 v4(113.5,62.74) ; v4@113.501,62.752 114.553,62.752 115.265,62.04 116.184,62.04 116.591,62.447 117.699,62.447 120.926,65.674 120.926,66.683 121.39,67.148 122.784,67.148 125.342,69.706 128.802,69.706 129.132,69.376 129.582,69.376 129.975,68.983 v4(129.975,68.95) 131.057,68.95 131.492,68.515 131.818,68.515 132.791,67.542 ; 132.794,67.545 132.889,67.45 134.605,67.45 135.305,66.75 R171.1@135.4,66.75 ; R171.1@135.352,66.703 R171.1@135.4,66.655
DDR_A13: R154.1 U14.T3 U16.T3 U27.H17 | length 48
  Top Layer w0.09: U27.H17@98.4,75.2 v5(98.775,75.575) ; v4(110.275,67.575) 110.775,67.575 111.05,67.3 111.05,66.95 110.701,66.601 U16.T3@110.701,66.327 ; v4@126.775,73.8 127.25,73.8 127.525,73.525 127.525,73.175 127.176,72.826 U14.T3@127.176,72.552
  Bottom Layer w0.09: v5(98.775,75.575) 99.127,75.927 99.739,75.927 100.624,76.812 100.816,76.812 100.932,76.696 100.932,76.57 101.011,76.492 101.24,76.492 101.317,76.569 101.317,76.701 101.429,76.812 101.671,76.812 101.767,76.716 101.767,76.606 101.881,76.492 102.887,76.492 103.006,76.612 103.006,76.727 103.091,76.812 103.389,76.812 103.474,76.727 103.474,76.587 103.559,76.502 103.778,76.502 103.863,76.587 103.863,76.717 103.948,76.802 104.103,76.802 104.378,76.528 104.378,76.297 104.66,76.015 104.89,76.015 109.255,71.65 109.255,68.546 110.226,67.575 v4(110.275,67.575) 110.976,67.575 111.369,67.968 111.482,67.968 112.025,68.512 112.025,69.055 115.845,72.875 116.175,72.875 116.525,72.525 117.057,72.525 118.782,74.25 126.275,74.25 126.725,73.8 v4(126.75,73.8) v4@126.775,73.8 ; v4@126.776,73.801 126.851,73.727 127.206,74.082 127.828,74.082 128.526,74.78 R154.1@128.526,76.977
DDR_A14: R175.1 U14.T7 U16.T7 U27.H18 | length 52.7
  Top Layer w0.09: U27.H18@99.2,75.2 99.2,75.145 99.366,74.979 99.366,74.859 v5(99.425,74.8) ; v4(109.55,62.375) 109.574,62.375 109.847,62.648 109.847,62.825 110.149,63.127 U16.T7@110.701,63.127 ; v4(126.025,68.6) 126.084,68.6 126.33,68.846 126.33,69.039 126.643,69.352 U14.T7@127.176,69.352
  Bottom Layer w0.09: v5(99.425,74.8) 99.033,74.408 98.907,74.408 98.474,73.975 98.474,72.194 98.319,72.04 98.319,71.552 97.805,71.038 97.805,70.682 98.007,70.48 98.469,70.48 99.279,69.67 99.804,69.67 100.137,69.337 100.257,69.337 107.286,62.307 109.482,62.307 v4(109.55,62.375) ; v4@109.551,62.377 109.964,62.377 110.086,62.255 111.596,62.255 111.729,62.122 112.146,62.122 112.456,61.812 112.813,61.812 113.427,61.198 114.078,61.198 114.316,60.96 114.684,60.96 114.764,60.88 116.664,60.88 117.071,61.287 118.222,61.287 119.209,62.274 120.038,62.274 121.659,63.894 121.959,63.894 124.54,66.475 124.54,67.12 126.019,68.6 v4(126.025,68.6) 126.441,68.6 126.561,68.48 126.914,68.48 126.943,68.509 128.443,68.509 128.965,67.987 129.325,67.987 129.667,67.645 129.879,67.645 130.079,67.445 130.463,67.445 130.649,67.259 131.177,67.259 131.242,67.195 131.461,67.195 131.526,67.13 131.528,67.13 131.854,66.804 131.854,65.435 131.644,65.225 R175.1@131.6,65.225
DDR_A15: R170.1 U14.M7 U16.M7 U27.N18 | length 50.9
  Top Layer w0.09: U27.N18@99.2,71.2 99.575,70.825 v5(100.425,70.825) ; v4(113.501,63.527) U16.M7@113.9,63.127 ; v4(129.975,69.745) 129.978,69.745 U14.M7@130.371,69.352 ; U14.M7@130.373,69.35 U14.M7@130.375,69.35
  Bottom Layer w0.09: v5(100.425,70.825) 101.679,70.827 101.775,70.923 101.775,71.086 101.944,71.254 102.069,71.254 102.175,71.149 102.175,70.91 102.258,70.827 102.451,70.827 102.499,70.875 102.499,71.407 102.612,71.52 102.762,71.52 102.864,71.419 102.864,70.615 103.078,70.4 104.024,70.4 104.566,69.857 104.566,69.419 104.186,69.038 104.186,68.354 104.533,68.006 104.533,67.144 107.931,63.746 112.425,63.746 112.548,63.623 113.027,63.623 113.124,63.526 113.499,63.526 v4(113.501,63.527) 113.957,63.071 114.723,63.071 115.463,62.33 116.064,62.33 116.471,62.737 117.421,62.737 120.302,65.618 120.302,66.469 121.27,67.438 122.664,67.438 125.172,69.946 128.925,69.946 129.146,69.725 129.975,69.725 129.975,69.648 130.345,69.279 131.152,69.279 131.616,68.815 131.951,68.815 133.011,67.755 135.25,67.755 R170.1@136.35,66.655
DDR_BA0: R148.1 U14.M2 U16.M2 U27.K19 | length 46.9
  Top Layer w0.09: U27.K19@100,73.6 100.054,73.6 100.245,73.791 100.341,73.791 v5(100.4,73.85) ; U16.M2@113.901,67.127 113.913,67.127 114.3,67.514 v4(114.3,67.525) ; U14.M2@130.376,73.352 130.388,73.352 130.775,73.739 v4(130.775,73.75)
  Bottom Layer w0.09: v5(100.4,73.85) 100.696,73.852 100.938,73.61 103.894,73.61 104.082,73.798 104.562,73.798 107.455,70.905 107.455,67.857 109.332,65.98 112.187,65.98 112.223,65.944 113.128,65.944 113.458,66.274 113.614,66.274 113.905,66.564 113.905,66.909 114.085,67.089 114.085,67.247 114.3,67.462 v4(114.3,67.525) 114.35,67.575 114.35,67.839 114.762,68.252 114.762,68.782 116.463,70.483 117.561,70.483 119.528,72.45 125.42,72.45 125.688,72.182 129.753,72.182 130.375,72.804 130.375,73.25 v4@130.835,73.71 ; v4(130.775,73.75) 130.775,73.835 130.974,74.034 130.974,74.182 131.364,74.571 131.364,74.855 132.661,76.152 133.306,76.152 134.131,76.977 R148.1@134.226,76.977
DDR_BA1: R177.1 U14.N8 U16.N8 U27.R18 | length 45.6
  Top Layer w0.09: v5(98.75,69.2) 98.775,69.2 99.175,69.6 U27.R18@99.2,69.6 ; v4(112.7,61) 112.7,61.926 U16.N8@113.101,62.327 ; v4(129.175,67.225) 129.175,68.151 U14.N8@129.576,68.552
  Bottom Layer w0.09: v5(98.75,69.2) 98.75,69.157 99.253,68.654 99.798,68.654 99.863,68.59 100.183,68.59 102.034,66.739 102.034,65.269 102.361,64.942 103.595,64.942 106.86,61.677 111.325,61.677 111.414,61.588 112.065,61.588 112.653,61 v4(112.7,61) 112.68,60.98 112.68,60.269 113.07,59.88 118.574,59.88 121.545,62.85 121.982,62.85 125.14,66.008 125.14,66.872 126.183,67.915 128.424,67.915 129.011,67.329 129.071,67.329 v4(129.175,67.225) 129.153,67.203 129.153,66.319 129.396,66.077 129.396,65.437 129.606,65.227 R177.1@129.701,65.227
DDR_BA2: R158.1 U14.M3 U16.M3 U27.J18 | length 51.7
  Top Layer w0.09: v5(98.99,74) 99.05,74.059 99.05,74.193 99.2,74.343 U27.J18@99.2,74.4 ; U16.M3@113.901,66.327 113.901,66.365 v4@114.3,66.764 ; U14.M3@130.376,72.552 130.376,72.59 v4@130.775,72.989
  Bottom Layer w0.09: v5(98.99,74) 98.99,73.512 99.457,73.045 99.789,73.045 100.014,73.27 104.378,73.27 107.155,70.493 107.155,67.746 109.166,65.735 113.273,65.735 113.534,65.996 113.653,65.996 114.3,66.643 v4(114.3,66.745) 114.3,66.866 114.498,67.063 114.498,67.164 114.696,67.362 114.696,67.76 115.1,68.165 115.1,68.709 116.573,70.183 117.685,70.183 119.652,72.15 125.275,72.15 125.483,71.942 129.854,71.942 130.726,72.814 130.726,73.041 131.17,73.485 131.17,73.904 131.426,74.16 138.365,74.16 R158.1@138.575,73.95
  other v4: 130.775,72.97
DDR_CASN: R166.1 U14.K3 U16.K3 U27.M18 | length 50.8
  Top Layer w0.09: U27.M18@99.2,72 99.22,72 99.595,71.625 v5(99.675,71.625) ; v4(115.5,65.775) U16.K3@115.501,66.327 ; U14.K3@131.975,72.55 132,72.55 v4@132.377,72.172
  Bottom Layer w0.09: v5(99.675,71.625) 99.72,71.583 99.964,71.583 100.066,71.481 101.336,71.481 101.965,72.11 103.898,72.11 105.995,70.013 105.995,67.266 108.486,64.775 114.967,64.775 115.5,65.308 v4(115.5,65.775) 115.87,66.145 116.796,66.145 118.78,68.13 118.78,68.778 119.116,69.114 119.116,69.658 119.338,69.88 123.494,69.88 124.561,70.947 131.152,70.947 v4(132.375,72.17) 132.486,72.17 132.6,72.284 132.683,72.284 132.994,72.595 133.339,72.595 135.784,70.15 R166.1@138.575,70.15
DDR_CKE: R176.1 U14.K9 U16.K9 U27.M16 | length 49.3
  Top Layer w0.09: U27.M16@97.6,72 97.625,72 97.9,71.725 v5(97.925,71.725) ; v4(115.4,60.475) 115.445,60.52 115.445,61.472 U16.K9@115.501,61.527 ; v4(131.375,66.725) 131.976,67.326 U14.K9@131.976,67.752
  Bottom Layer w0.09: v5(97.925,71.725) 97.495,71.295 97.495,70.574 97.879,70.19 98.249,70.19 99.474,68.964 100.219,68.964 102.334,66.849 102.334,65.393 102.485,65.242 103.719,65.242 106.985,61.977 111.491,61.977 111.633,61.835 112.114,61.835 112.423,61.527 112.732,61.527 113.339,60.92 113.864,60.92 114.114,60.67 114.564,60.67 114.758,60.476 v4@115.399,60.476 ; v4@115.404,60.471 115.836,60.471 115.945,60.363 118.447,60.363 118.664,60.58 118.864,60.58 121.774,63.49 122.212,63.49 124.84,66.118 124.84,66.996 126.049,68.205 128.442,68.205 128.95,67.697 129.268,67.697 129.82,67.145 130.339,67.145 130.525,66.959 131.053,66.959 131.287,66.725 v4(131.375,66.725) 131.375,66.2 130.955,65.78 130.955,65.435 130.745,65.225 R176.1@130.65,65.225
DDR_CLK_N: R167.2 U14.K7 U16.K7 U27.M19 | length 45.3
  Top Layer w0.09: U27.M19@100,72 100.285,71.715 101.842,71.715 102.293,71.264 103.124,71.264 103.285,71.425 v4(103.381,71.425) ; U16.K7@115.501,63.127 v4(115.9,63.525) ; U14.K7@131.977,69.352 v4@132.375,69.75
  Bottom Layer w0.09: v4@103.381,71.417 103.5,71.417 103.671,71.246 103.941,71.246 105.415,69.772 105.415,69.375 104.753,68.712 104.753,68.588 104.888,68.452 105.13,68.452 105.415,68.167 105.415,67.829 105.073,67.487 105.073,67.367 108.171,64.27 114.632,64.27 115.012,63.891 115.012,63.744 115.488,63.268 115.641,63.268 v4(115.9,63.525) 116.151,63.277 116.651,63.277 116.925,63.551 116.925,63.912 121.093,68.08 122.542,68.08 124.898,70.436 131.001,70.436 131.93,69.507 132.14,69.507 v4@132.375,69.742 ; v4(132.375,69.745) 132.629,69.491 133.173,69.491 133.296,69.614 133.296,69.617 133.506,69.827 R167.2@133.601,69.827
DDR_CLK_P: R167.1 U14.J7 U16.J7 U27.N19 | length 45.4
  Top Layer w0.09: U27.N19@100,71.2 100.009,71.2 100.294,71.485 101.718,71.485 102.189,71.014 103.124,71.014 103.313,70.825 v4(103.381,70.825) ; v4(115.9,62.725) U16.J7@116.3,63.125 ; v4@132.375,68.95 U14.J7@132.775,69.35
  Bottom Layer w0.09: v4(103.381,70.825) 103.492,70.825 103.664,70.996 103.837,70.996 105.165,69.669 105.165,69.478 104.503,68.816 104.503,68.485 104.785,68.202 105.026,68.202 105.165,68.064 105.165,67.932 104.823,67.591 104.823,67.264 108.067,64.02 114.529,64.02 114.762,63.787 114.762,63.64 115.384,63.018 115.63,63.018 115.901,62.747 v4(115.9,62.725) 116.201,63.027 116.754,63.027 117.175,63.448 117.175,63.809 121.196,67.83 122.646,67.83 125.002,70.186 130.898,70.186 131.827,69.257 132.068,69.257 v4@132.375,68.95 ; v4(132.375,68.955) 132.661,69.241 133.19,69.241 133.294,69.137 133.391,69.137 R167.1@133.6,68.925
DDR_CSN: R160.1 U14.L2 U16.L2 U27.N16 | length 53.1
  Top Layer w0.09: U27.N16@97.6,71.2 97.916,70.884 98.091,70.884 v5(98.15,70.825) ; U16.L2@114.7,67.125 114.716,67.125 v4@115.096,66.745 ; U14.L2@131.175,73.35 131.191,73.35 131.571,72.97 v4(131.575,72.97)
  Bottom Layer w0.09: v5(98.15,70.825) 98.626,71.301 98.626,71.748 98.857,71.979 99.593,71.979 100.304,72.69 104.138,72.69 106.575,70.253 106.575,67.506 108.819,65.262 113.746,65.262 114.337,65.853 114.337,65.92 114.568,66.152 114.783,66.152 115.063,66.431 115.063,66.708 v4(115.1,66.745) ; v4@115.1,66.75 115.5,67.15 116.864,67.15 117.752,68.038 117.752,69.31 118.929,70.487 123.252,70.487 124.312,71.547 125.044,71.547 125.157,71.434 130.276,71.434 131.503,72.661 131.503,72.898 v4(131.575,72.97) ; v4@131.575,72.976 132,73.402 135.596,73.402 136.452,72.546 138.188,72.546 138.378,72.355 R160.1@138.582,72.056
DDR_DQ0: U16.H8 U27.W22 | length 20.7
  Top Layer w0.09: U27.W22@102.401,66.377 102.476,66.377 104.608,64.246 104.85,64.246 110.14,58.955 116.34,58.955 116.562,59.176 116.562,61.228 116.7,61.366 116.7,61.925 U16.H8@117.1,62.325
DDR_DQ1: U16.F7 U27.Y21 | length 23.6
  Top Layer w0.09: U27.Y21@101.6,65.6 102.003,65.2 102.427,65.2 102.774,64.853 103.152,64.853 104.359,63.646 104.629,63.646 109.9,58.375 116.581,58.375 117.746,59.54 117.746,59.897 118.302,60.453 118.302,62.726 U16.F7@118.7,63.125
DDR_DQ2: U16.H7 U27.Y22 | length 22
  Top Layer w0.09: U27.Y22@102.4,65.6 102.833,65.6 104.497,63.936 104.75,63.936 110.02,58.665 116.46,58.665 117.054,59.258 117.054,59.979 117.497,60.422 117.497,62.724 U16.H7@117.1,63.122
DDR_DQ3: U16.F8 U27.AA22 | length 22.5
  Top Layer w0.09: U27.AA22@102.4,64.8 102.688,64.515 103.066,64.515 104.235,63.346 104.519,63.346 109.78,58.085 116.701,58.085 119.097,60.482 119.097,61.928 U16.F8@118.7,62.325
DDR_DQ4: U16.E3 U27.T21 | length 23.1
  Top Layer w0.09: U27.T21@101.601,68.802 101.791,68.612 101.933,68.612 102.16,68.385 103.367,68.385 105.175,66.577 108.611,66.577 109.242,67.208 109.242,69.141 109.661,69.56 114.304,69.56 114.787,69.077 117.521,69.077 117.75,68.848 117.75,68.548 118.028,68.27 118.043,68.27 118.285,68.028 118.285,67.848 118.589,67.543 118.779,67.543 119.118,67.205 119.118,66.71 U16.E3@119.501,66.327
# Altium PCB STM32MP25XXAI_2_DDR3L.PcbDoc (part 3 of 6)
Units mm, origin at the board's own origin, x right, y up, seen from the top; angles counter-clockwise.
Board outline 172 x 137 mm, 6 copper layers (Top Layer, Signal Layer 1, Signal Layer 2, Signal Layer 3, Signal Layer 4, Bottom Layer), stack 2.079 mm thick; 237 components, 152 nets, 1304 pads, 909 vias.
Unrouted connection lines stored in the file: 13.

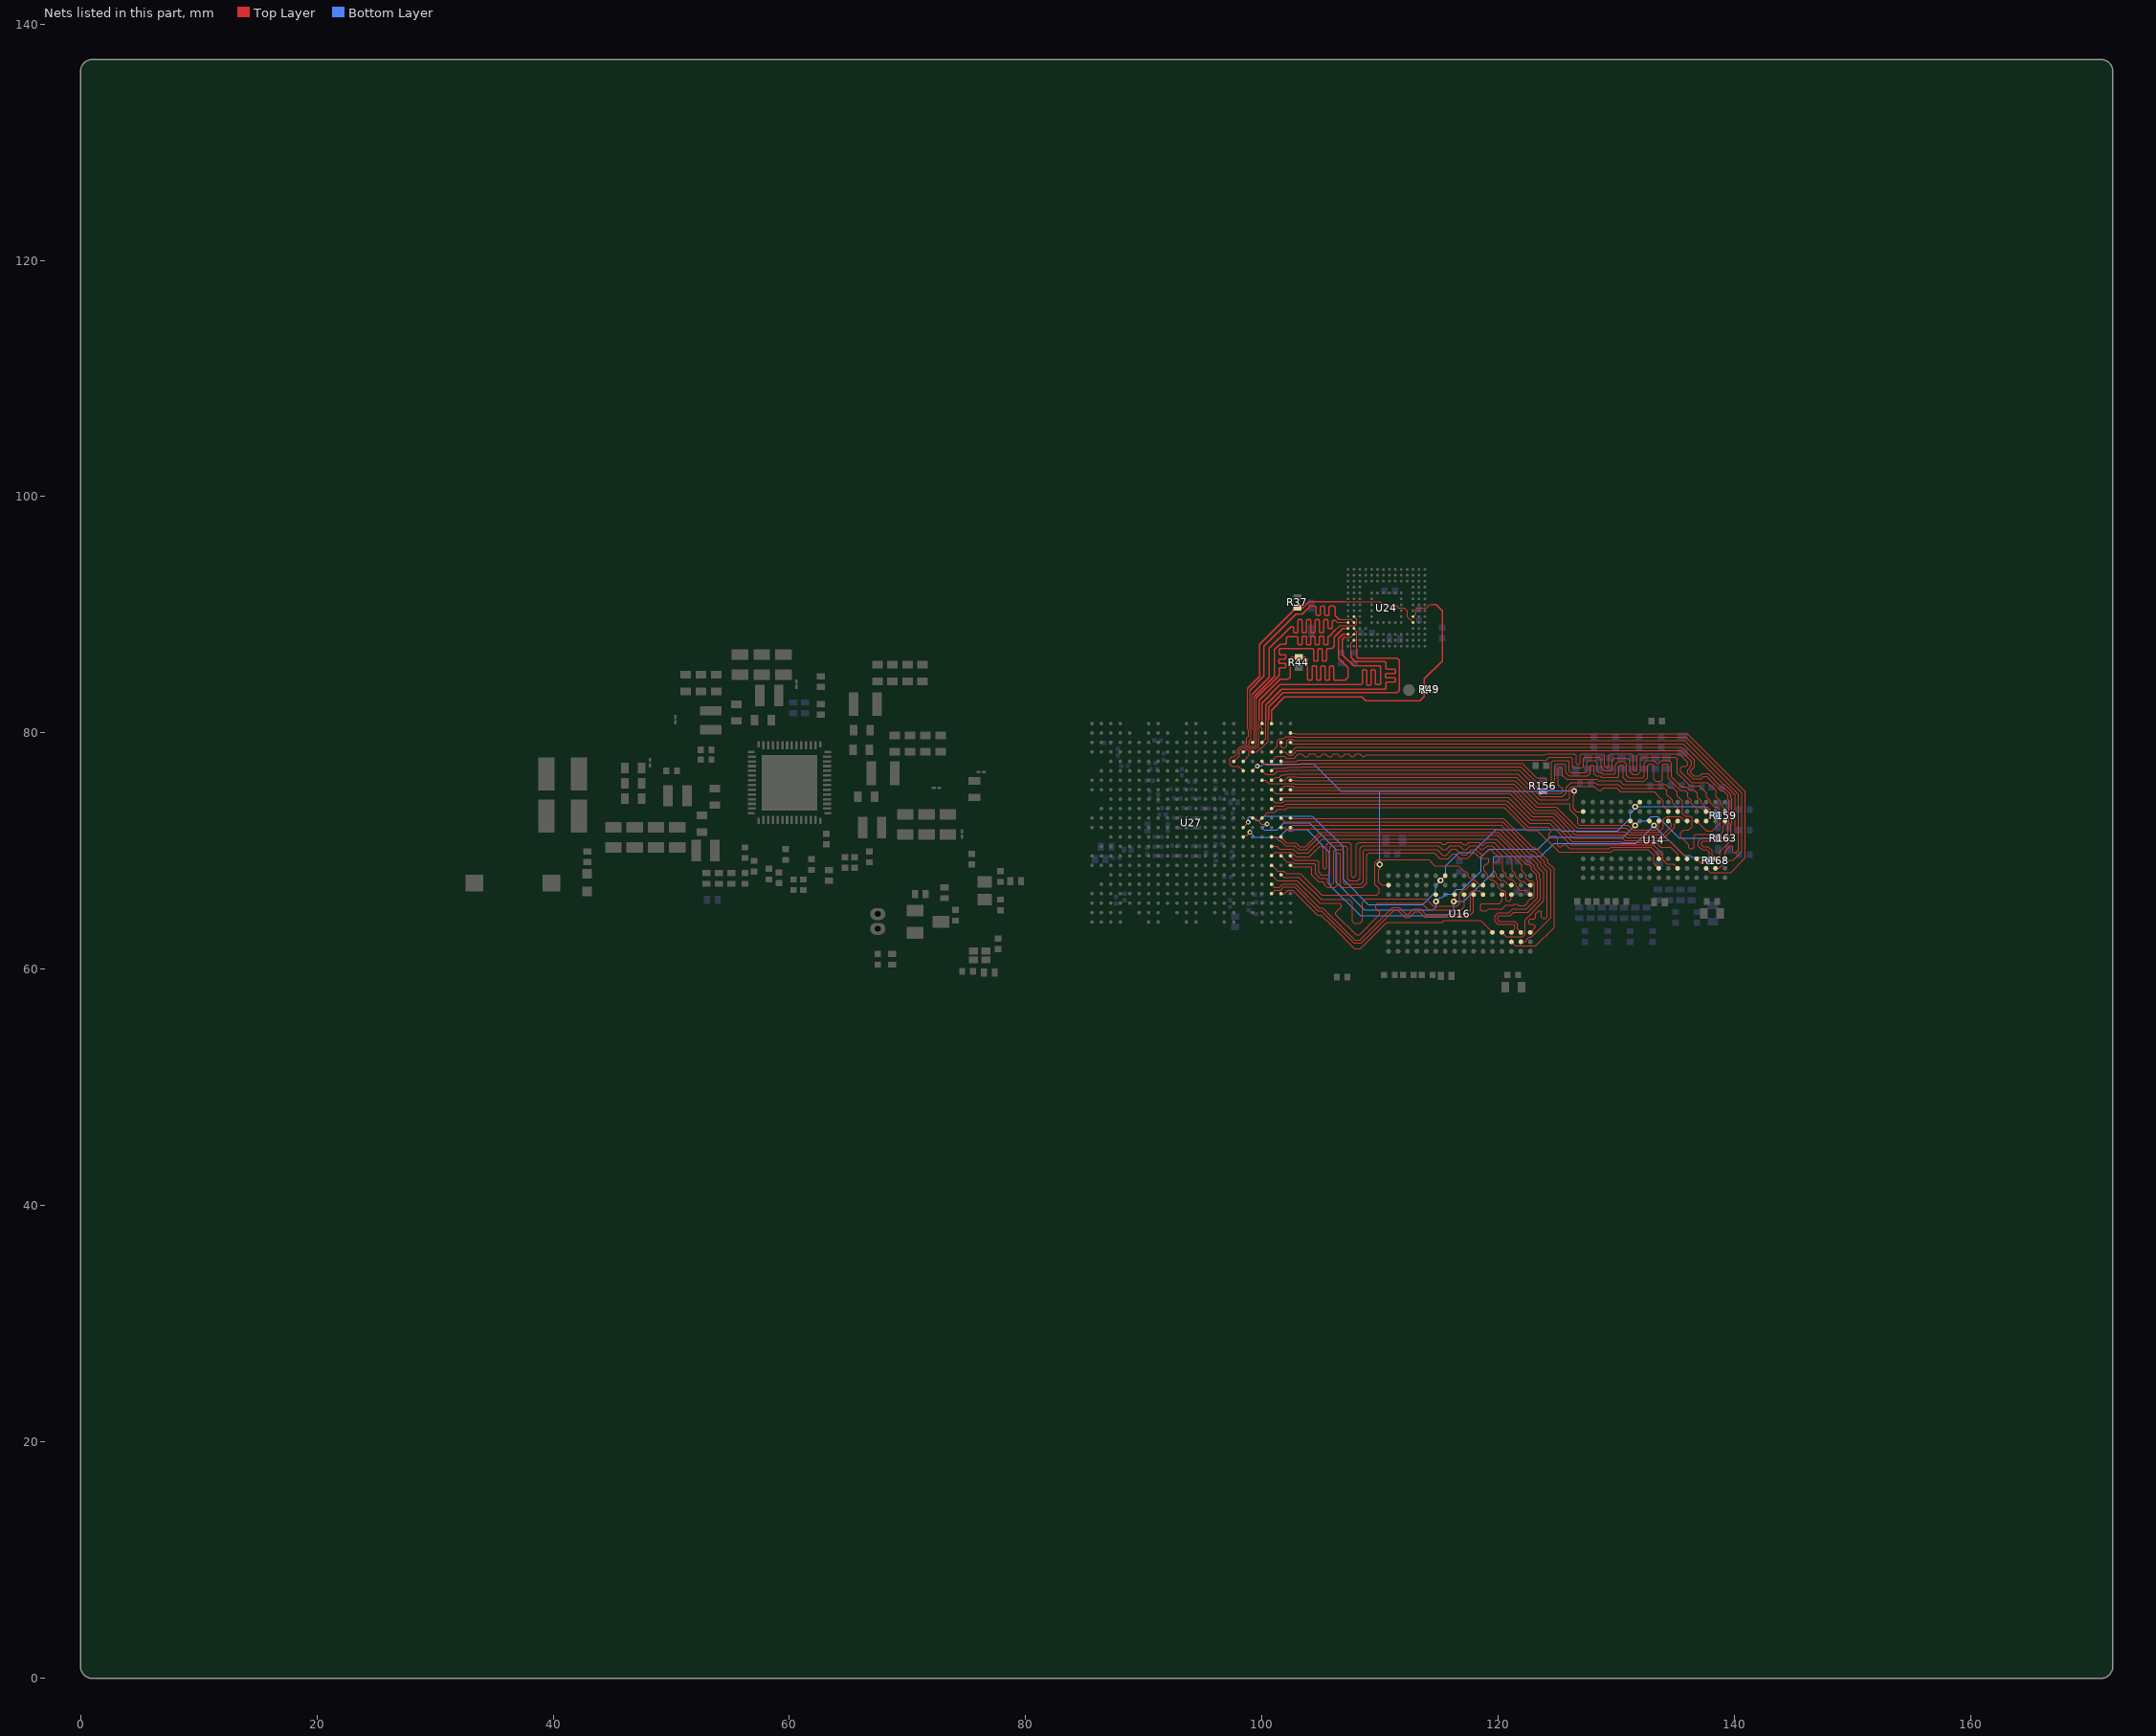
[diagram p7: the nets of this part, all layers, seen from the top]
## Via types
v1: diameter 0.55, hole 0.35, Top Layer to Bottom Layer, 421 vias
v2: diameter 0.4, hole 0.2, Top Layer to Bottom Layer, tented both sides, 169 vias
v3: diameter 0.5, hole 0.2, Top Layer to Bottom Layer, 146 vias
v4: diameter 0.5, hole 0.25, Top Layer to Bottom Layer, 145 vias
v5: diameter 0.4, hole 0.2, Top Layer to Bottom Layer, 28 vias

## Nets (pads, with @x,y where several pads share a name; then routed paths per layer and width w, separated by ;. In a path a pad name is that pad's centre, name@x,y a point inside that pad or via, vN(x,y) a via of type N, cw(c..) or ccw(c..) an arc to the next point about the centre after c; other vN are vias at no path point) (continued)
DDR_DQ5: U16.F2 U27.T20 | length 23.2
  Top Layer w0.09: U27.T20@100.801,68.802 100.826,68.802 101.316,68.312 101.823,68.312 102.04,68.095 103.233,68.095 105.051,66.277 109.708,66.277 109.91,66.478 109.91,66.808 109.532,67.186 109.532,69.021 109.781,69.27 114.13,69.27 114.623,68.777 116.623,68.777 117.13,68.27 117.243,68.27 117.457,68.056 117.457,67.876 117.806,67.527 118.002,67.527 118.402,67.127 U16.F2@118.701,67.127
DDR_DQ6: U16.G2 U27.U21 | length 22.2
  Top Layer w0.09: U27.U21@101.6,68 101.634,68 101.829,67.805 103.099,67.805 105.001,65.903 107.366,65.903 107.631,65.637 107.631,64.047 107.77,63.908 108.293,63.908 108.476,64.091 108.476,65.693 108.749,65.967 113.871,65.967 114.483,65.355 116.511,65.355 116.697,65.542 116.697,66.41 117.067,66.78 117.243,66.78 117.587,67.124 U16.G2@117.9,67.125 U16.G2@117.9,67.125
DDR_DQ7: U16.H3 U27.U20 | length 22.9
  Top Layer w0.09: U27.U20@100.8,68 101.285,67.515 102.965,67.515 104.878,65.602 106.563,65.602 106.703,65.462 106.703,65.275 106.237,64.809 106.237,64.644 107.95,62.931 108.233,62.931 109.969,64.666 109.969,64.835 109.631,65.172 109.631,65.432 109.801,65.602 113.522,65.602 114.087,65.037 116.836,65.037 117.101,65.301 U16.H3@117.101,66.327
DDR_DQ8: U16.D7 U27.M21 | length 32.1
  Top Layer w0.09: U27.M21@101.601,72.002 101.976,72.002 102.276,71.702 102.601,71.702 102.769,71.871 120.126,71.871 122.561,69.435 122.762,69.435 123.31,68.887 123.31,68.686 123.85,68.146 123.85,65.802 122.243,64.195 122.243,62.971 122.052,62.78 120.645,62.78 U16.D7@120.3,63.125
DDR_DQ9: U16.A7 U27.M22 | length 31.6
  Top Layer w0.09: U27.M22@102.401,72.002 102.586,72.187 120.219,72.187 122.681,69.725 122.882,69.725 123.6,69.007 123.6,68.807 124.14,68.267 124.14,64.484 123.965,64.309 123.765,64.309 123.657,64.416 123.657,64.861 123.572,64.946 123.419,64.946 123.171,64.698 123.171,64.403 123.016,64.248 122.72,64.248 122.59,64.118 122.59,63.894 122.666,63.818 122.971,63.818 123.129,63.66 123.129,63.522 122.732,63.125 U16.A7@122.7,63.125
DDR_DQ10: U16.B8 U27.L21 | length 32.2
  Top Layer w0.09: U27.L21@101.6,72.8 101.613,72.8 101.936,72.477 120.34,72.477 122.802,70.015 123.003,70.015 123.89,69.128 123.89,68.927 124.43,68.387 124.43,64.364 122.791,62.725 122.605,62.725 122.205,62.325 U16.B8@121.9,62.325
DDR_DQ11: U16.C8 U27.L22 | length 33.6
  Top Layer w0.09: U27.L22@102.401,72.802 102.436,72.767 120.46,72.767 122.922,70.305 123.123,70.305 124.18,69.248 124.18,69.047 124.72,68.507 124.72,63.534 123.166,61.98 121.445,61.98 U16.C8@121.1,62.325
DDR_DQ12: U16.C3 U27.T22 | length 32.8
  Top Layer w0.09: U27.T22@102.4,68.8 102.457,68.8 102.582,68.675 104.107,68.675 104.22,68.562 104.22,67.971 104.767,67.424 105.149,67.424 105.264,67.309 105.264,67.185 105.534,66.915 106.177,66.915 106.34,67.078 106.34,69.772 106.425,69.857 106.551,69.857 106.636,69.772 106.636,67.102 106.817,66.92 108.475,66.92 108.866,67.311 108.866,69.639 109.076,69.85 114.564,69.85 115.037,69.377 115.76,69.377 116.139,69.756 116.364,69.756 116.733,69.387 117.397,69.387 117.86,69.85 117.992,69.85 118.451,69.391 119.086,69.391 119.192,69.285 119.192,69.045 119.068,68.92 118.928,68.92 118.78,68.772 118.78,68.336 119.045,68.071 119.045,67.86 119.37,67.535 119.609,67.535 119.955,67.188 119.955,66.982 120.254,66.683 120.448,66.683 120.645,66.486 120.645,65.852 120.745,65.752 120.921,65.752 121.078,65.909 121.078,66.303 U16.C3@121.1,66.325
DDR_DQ13: U16.A2 U27.R20 | length 34.5
  Top Layer w0.09: U27.R20@100.801,69.602 100.809,69.602 101.092,69.885 102.518,69.885 102.858,69.545 104.013,69.545 104.903,70.436 105.042,70.436 105.168,70.31 105.168,68.589 105.253,68.504 105.385,68.504 105.47,68.589 105.47,70.533 105.674,70.737 107.366,70.737 107.557,70.545 107.557,67.9 107.657,67.8 107.803,67.8 107.976,67.973 107.976,70.543 108.184,70.751 115.092,70.751 115.27,70.573 115.544,70.573 115.722,70.751 116.844,70.751 117.043,70.552 117.278,70.552 117.476,70.751 118.334,70.751 118.572,70.512 118.692,70.512 118.931,70.751 119.647,70.751 121.175,69.223 121.175,68.338 121.461,68.052 121.461,67.872 121.862,67.47 122.091,67.47 122.377,67.184 122.641,67.184 U16.A2@122.7,67.125
DDR_DQ14: U16.C2 U27.R21 | length 33.5
  Top Layer w0.09: U27.R21@101.6,69.6 101.6,69.595 102.1,69.095 102.572,69.095 102.702,68.965 104.393,68.965 104.51,68.847 104.51,68.091 104.887,67.714 105.454,67.714 105.554,67.613 105.554,67.305 105.655,67.205 105.911,67.205 106.05,67.344 106.05,70.008 106.189,70.147 106.801,70.147 106.926,70.022 106.926,67.299 107.014,67.21 108.355,67.21 108.576,67.431 108.576,70.036 108.679,70.14 114.811,70.14 115.284,69.667 115.562,69.667 116.066,70.171 116.409,70.171 116.903,69.677 117.277,69.677 117.74,70.14 118.112,70.14 118.571,69.681 118.743,69.681 119.212,70.15 119.364,70.15 120.081,69.433 120.081,69.178 119.964,69.062 119.687,69.062 119.575,68.95 119.575,68.341 119.845,68.071 119.845,67.855 120.148,67.552 120.447,67.552 120.825,67.174 121.054,67.174 U16.C2@121.101,67.127
DDR_DQ15: U16.A3 U27.R22 | length 32.7
  Top Layer w0.09: U27.R22@102.4,69.6 102.743,69.255 104.644,69.255 104.8,69.099 104.8,68.211 105.007,68.004 105.585,68.004 105.76,68.179 105.76,70.328 105.878,70.447 107.045,70.447 107.226,70.266 107.226,67.646 107.371,67.5 108.088,67.5 108.276,67.688 108.276,70.247 108.489,70.461 114.934,70.461 115.266,70.129 115.567,70.129 115.899,70.461 116.724,70.461 117.049,70.136 117.279,70.136 117.596,70.453 117.596,70.461 118.201,70.461 118.545,70.117 118.707,70.117 119.051,70.461 119.463,70.461 120.371,69.553 120.371,68.34 120.372,68.34 120.66,68.053 120.66,67.873 120.956,67.577 121.158,67.577 121.493,67.241 121.493,67.036 121.819,66.71 122.317,66.71 U16.A3@122.701,66.327
DDR_DQ16: U14.B8 U27.D20 | length 50.3
  Top Layer w0.09: U27.D20@100.801,78.402 101.294,78.895 101.294,79.322 101.489,79.517 101.825,79.517 101.837,79.517 102.011,79.692 102.746,79.692 102.786,79.652 135.868,79.652 140.615,74.906 140.615,69.983 139.886,69.255 139.568,69.255 139.263,68.95 139.049,68.95 138.649,68.55 U14.B8@138.375,68.55
DDR_DQ17: U14.D7 U27.C22 | length 47.7
  Top Layer w0.09: U27.C22@102.4,79.2 102.417,79.2 102.545,79.072 135.628,79.072 139.055,75.645 139.143,75.645 140.035,74.753 140.035,71.275 138.747,69.988 138.747,69.234 138.518,69.005 137.123,69.005 U14.D7@136.776,69.352
DDR_DQ18: U14.A7 U27.C21 | length 48.9
  Top Layer w0.09: U27.C21@101.6,79.2 101.584,79.184 101.584,78.875 101.734,78.725 101.9,78.725 102.105,78.93 102.105,79.322 102.278,79.495 102.533,79.495 102.666,79.362 135.748,79.362 140.325,74.785 140.325,70.103 140.053,69.831 139.933,69.831 139.848,69.916 139.848,70.372 139.755,70.465 139.634,70.465 139.179,70.01 U14.A7@139.179,69.354
DDR_DQ19: U14.C8 U27.B22 | length 50.1
  Top Layer w0.09: U27.B22@102.4,80 102.418,79.982 102.866,79.982 102.906,79.942 135.988,79.942 140.905,75.026 140.905,69.451 139.659,68.205 137.92,68.205 U14.C8@137.575,68.55
DDR_DQ20: U14.C2 U27.F20 | length 50.8
  Top Layer w0.09: U27.F20@100.801,76.802 101.001,77.002 101.805,77.002 101.855,77.052 102.1,77.052 102.15,77.102 103.348,77.102 103.378,77.132 121.899,77.132 123.116,75.915 123.695,75.915 123.81,75.8 123.81,75.307 123.913,75.204 124.701,75.204 124.786,75.289 124.786,77.259 124.889,77.362 125.584,77.362 125.711,77.235 125.711,76.663 126.008,76.365 127.547,76.365 127.77,76.588 127.77,77.165 127.855,77.25 128.018,77.25 128.103,77.165 128.103,76.548 128.286,76.365 128.589,76.365 128.714,76.24 130.107,76.24 130.22,76.353 130.22,77.194 130.315,77.289 130.468,77.289 130.553,77.204 130.553,76.202 130.828,75.928 132.323,75.928 132.62,76.224 132.62,77.213 132.779,77.372 132.991,77.372 133.15,77.213 133.15,76.069 133.292,75.928 133.749,75.928 133.884,76.062 133.884,77.282 133.974,77.372 134.27,77.372 134.372,77.271 134.372,76.176 135.389,75.159 135.776,75.159 136.023,74.912 136.023,74.589 136.05,74.563 136.118,74.495 136.322,74.29 136.322,74.052 136.672,73.702 137.163,73.702 137.513,73.352 U14.C2@137.576,73.352
DDR_DQ21: U14.A3 U27.F19 | length 51.5
  Top Layer w0.09: U27.F19@100.001,76.802 100.301,76.502 101.015,76.502 101.275,76.762 101.905,76.762 101.945,76.802 102.204,76.802 102.244,76.842 121.779,76.842 123.709,74.913 125.306,74.913 125.445,75.052 125.445,75.25 125.076,75.619 125.076,76.986 125.162,77.072 125.331,77.072 125.421,76.982 125.421,76.426 125.771,76.075 128.339,76.075 128.464,75.95 130.267,75.95 130.58,75.638 134.176,75.638 134.468,75.345 134.791,75.345 135.132,75.004 135.132,74.681 135.576,74.237 135.576,73.177 135.801,72.952 136.251,72.952 136.376,72.827 136.376,72.061 136.123,71.809 135.675,71.809 135.414,71.548 135.414,71.225 136.101,70.538 136.101,70.298 136.197,70.202 136.452,70.202 136.573,70.323 136.573,71.324 136.687,71.438 138.79,71.438 139.021,71.67 139.021,72.142 139.135,72.256 139.135,72.51 U14.A3@139.175,72.55
DDR_DQ22: U14.C3 U27.E19 | length 51
  Top Layer w0.09: U27.E19@100.001,77.602 100.298,77.305 101.722,77.305 101.77,77.353 101.859,77.353 ; 101.86,77.352 102.906,77.352 ; 102.907,77.353 103.189,77.353 103.258,77.422 122.019,77.422 123.236,76.205 123.92,76.205 124.1,76.025 124.1,75.594 124.199,75.495 124.386,75.495 124.471,75.58 124.471,77.523 124.6,77.652 125.895,77.652 126.001,77.546 126.001,76.783 126.129,76.655 127.395,76.655 127.48,76.74 127.48,77.546 127.596,77.662 128.17,77.662 128.393,77.439 128.393,76.752 128.489,76.655 128.709,76.655 128.834,76.53 129.839,76.53 129.93,76.621 129.93,77.356 130.153,77.579 130.621,77.579 130.843,77.356 130.843,76.427 131.053,76.218 132.203,76.218 132.33,76.344 132.33,77.439 132.553,77.662 133.145,77.662 133.382,77.425 133.58,77.425 133.817,77.662 134.439,77.662 134.662,77.439 134.662,76.299 135.512,75.449 135.895,75.449 136.187,75.156 136.577,75.156 136.693,75.041 136.698,75.036 cw(c136.425,74.75) 136.711,75.023 136.716,75.018 136.798,74.935 136.825,74.909 136.825,74.588 136.851,74.561 137.154,74.258 137.154,74.082 137.512,73.725 137.688,73.725 137.92,73.493 137.92,72.895 U14.C3@137.575,72.55
DDR_DQ23: U14.A2 U27.E20 | length 50.1
  Top Layer w0.09: U27.E20@100.801,77.602 101.218,78.019 101.9,78.019 102.067,77.852 102.699,77.852 103.079,78.232 103.371,78.232 103.601,78.002 103.826,78.002 104.056,78.232 104.426,78.232 104.656,78.002 104.901,78.002 105.131,78.232 105.371,78.232 105.601,78.002 105.851,78.002 106.081,78.232 106.371,78.232 106.601,78.002 106.801,78.002 107.031,78.232 107.326,78.232 107.556,78.002 107.722,78.002 107.952,78.232 108.296,78.232 108.526,78.002 108.676,78.002 108.808,78.134 123.927,78.134 124.035,78.242 126.437,78.242 126.581,78.098 126.581,77.431 126.666,77.346 126.815,77.346 126.9,77.431 126.9,78.094 127.048,78.242 128.85,78.242 128.973,78.119 128.973,77.215 129.077,77.11 129.265,77.11 129.35,77.195 129.35,78.112 129.48,78.242 131.274,78.242 131.423,78.093 131.423,76.901 131.526,76.798 131.649,76.798 131.75,76.899 131.75,78.092 131.9,78.242 135.284,78.242 136.018,77.508 136.018,77.317 135.884,77.183 135.551,77.183 135.441,77.073 135.441,76.731 136.35,75.823 137.703,75.823 138.43,75.096 138.43,74.583 138.83,74.183 138.83,74.007 139.006,73.831 139.006,73.747 139.157,73.596 139.157,73.371 U14.A2@139.176,73.352
DDR_DQ24: U14.E3 U27.G19 | length 38.9
  Top Layer w0.09: U27.G19@100.001,76.002 100.007,75.995 100.285,75.995 100.576,75.704 102.757,75.704 102.779,75.682 121.299,75.682 123.23,73.751 124.897,73.751 126.648,72 126.707,71.94 130.827,71.94 131.183,71.584 133.566,71.584 133.976,71.993 133.976,72.666 134.237,72.927 135.365,72.927 135.729,72.563 135.964,72.563 U14.E3@135.976,72.552
DDR_DQ25: U14.H3 U27.G22 | length 34.1
  Top Layer w0.09: U27.G22@102.401,76.002 102.869,76.002 102.899,75.972 121.419,75.972 123.35,74.041 125.95,74.041 126.05,73.941 126.05,73.495 126.698,72.847 126.698,72.36 126.853,72.205 130.981,72.205 131.411,71.775 133.339,71.775 133.575,72.011 U14.H3@133.575,72.55
DDR_DQ26: U14.G2 U27.G21 | length 36.1
  Top Layer w0.09: U27.G21@101.601,76.002 101.925,76.002 102.218,76.295 102.986,76.295 103.019,76.262 121.539,76.262 123.47,74.331 125.831,74.331 126.025,74.525 126.025,75.259 126.261,75.495 128.099,75.495 128.483,75.111 128.659,75.111 128.918,75.37 129.995,75.37 130.32,75.045 133.191,75.045 133.43,74.806 133.43,74.736 133.661,74.505 133.708,74.505 133.983,74.229 133.983,73.799 134.375,73.407 U14.G2@134.375,73.35
DDR_DQ27: U14.F2 U27.G20 | length 37.7
  Top Layer w0.09: U27.G20@100.801,76.002 100.849,76.002 101.109,76.262 101.435,76.262 101.635,76.462 101.96,76.462 102.05,76.552 121.659,76.552 123.588,74.623 125.426,74.623 125.735,74.932 125.735,75.379 126.141,75.785 128.219,75.785 128.343,75.66 130.147,75.66 130.472,75.335 134.049,75.335 134.23,75.154 134.23,74.783 134.72,74.293 134.72,74.088 135.146,73.662 135.146,73.382 U14.F2@135.176,73.352
DDR_DQ28: U14.F7 U27.J21 | length 36
  Top Layer w0.09: U27.J21@101.6,74.4 101.762,74.562 120.835,74.562 122.766,72.631 124.433,72.631 126.244,70.82 130.345,70.82 130.442,70.723 133.348,70.723 133.734,70.336 134.562,70.336 135.176,69.723 U14.F7@135.176,69.352
DDR_DQ29: U14.F8 U27.J20 | length 37.2
  Top Layer w0.09: U27.J20@100.801,74.402 101.098,74.105 101.722,74.105 101.889,74.272 120.715,74.272 122.646,72.341 124.312,72.341 126.121,70.533 133.124,70.533 133.91,69.746 133.91,69.277 134.26,68.927 134.8,68.927 U14.F8@135.176,68.552
DDR_DQ30: U14.H7 U27.K20 | length 36.1
  Top Layer w0.09: U27.K20@100.801,73.602 100.859,73.602 101.072,73.815 101.842,73.815 102.009,73.982 120.594,73.982 122.526,72.051 124.192,72.051 124.457,71.786 124.457,71.65 124.3,71.492 124.3,71.227 124.385,71.143 124.943,71.143 125.028,71.058 125.028,70.498 125.155,70.372 125.337,70.372 125.487,70.521 125.722,70.521 126.041,70.203 129.388,70.203 129.516,70.331 132.902,70.331 133.559,69.673 133.559,69.365 U14.H7@133.575,69.35
DDR_DQ31: U14.H8 U27.L19 | length 36.7
  Top Layer w0.09: U27.L19@100.001,72.802 100.476,73.277 101.079,73.277 101.327,73.525 101.962,73.525 102.129,73.692 120.474,73.692 122.405,71.761 123.282,71.761 125.13,69.913 129.508,69.913 129.736,70.14 132.679,70.14 133.175,69.644 133.175,68.95 U14.H8@133.575,68.55
DDR_DQM0: U16.E7 U27.W21 | length 21.5
  Top Layer w0.09: U27.W21@101.601,66.402 101.629,66.374 101.859,66.374 102.17,66.685 102.593,66.685 104.673,64.605 104.956,64.605 106.005,63.556 107.809,61.752 108.351,61.752 110.558,63.96 115.258,63.96 115.429,64.13 118.495,64.13 U16.E7@119.5,63.125
DDR_DQM1: U16.D3 U27.P20 | length 34.2
  Top Layer w0.09: U27.P20@100.801,70.402 100.855,70.402 101.254,70.402 101.481,70.175 102.638,70.175 102.978,69.835 103.893,69.835 105.098,71.041 119.782,71.041 121.979,68.843 121.979,68.334 122.355,67.958 122.355,67.723 122.592,67.486 122.827,67.486 123.045,67.268 123.045,66.171 122.864,65.99 122.731,65.99 122.47,65.729 122.47,65.636 122.239,65.405 121.702,65.405 121.602,65.505 121.314,65.505 121.247,65.437 120.645,65.437 120.334,65.126 119.169,65.126 118.995,64.952 118.592,64.952 118.507,65.037 118.507,65.465 118.592,65.55 120.077,65.55 120.313,65.786 120.313,66.312 U16.D3@120.3,66.325
DDR_DQM2: U14.D3 U27.E21 | length 49.4
  Top Layer w0.09: U27.E21@101.603,77.603 102.927,77.603 103.036,77.712 124.035,77.712 124.275,77.952 126.168,77.952 126.291,77.829 126.291,77.141 126.376,77.056 127.1,77.056 127.19,77.146 127.19,77.834 127.308,77.952 128.494,77.952 128.683,77.764 128.683,77.095 128.957,76.82 129.526,76.82 129.64,76.935 129.64,77.695 129.814,77.869 130.938,77.869 131.133,77.674 131.133,76.73 131.356,76.508 131.817,76.508 132.04,76.73 132.04,77.771 132.221,77.952 134.994,77.952 135.139,77.806 135.139,76.623 136.23,75.533 137.001,75.533 137.63,74.904 137.63,74.586 137.938,74.278 137.938,74.112 138.298,73.752 138.461,73.752 138.73,73.483 138.73,72.344 138.115,71.729 137.599,71.729 U14.D3@136.776,72.552
DDR_DQM3: U14.E7 U27.H20 | length 37.6
  Top Layer w0.09: U27.H20@100.801,75.201 100.957,75.045 101.151,74.852 120.955,74.852 122.766,73.041 122.886,72.921 124.553,72.921 126.364,71.11 130.474,71.11 130.671,70.913 134.433,70.913 135.976,69.37 U14.E7@135.976,69.352
DDR_DQS0_N: U16.G3 U27.W20 | length 22.7
  Top Layer w0.09: U27.W20@100.801,66.402 101.101,66.702 101.554,66.702 101.827,66.975 102.727,66.975 104.741,64.961 105.025,64.961 107.746,62.24 108.414,62.24 111.151,64.977 111.505,64.977 112.085,64.397 112.476,64.397 112.942,64.863 113.318,64.863 113.751,64.43 117.453,64.43 117.901,64.878 U16.G3@117.901,66.327
DDR_DQS0_P: U16.F3 U27.V20 | length 23.8
  Top Layer w0.09: U27.V20@100.801,67.202 101.051,66.952 101.451,66.952 101.724,67.225 102.83,67.225 104.844,65.211 105.128,65.211 107.849,62.49 108.311,62.49 111.048,65.227 111.609,65.227 112.189,64.647 112.373,64.647 112.839,65.113 113.421,65.113 113.854,64.68 117.349,64.68 117.651,64.982 117.651,66.086 117.555,66.182 117.555,66.468 117.757,66.67 118.358,66.67 U16.F3@118.701,66.327
DDR_DQS1_N: U16.B7 U27.N21 | length 33.6
  Top Layer w0.09: U27.N21@101.6,71.2 101.6,71.18 102.065,70.715 102.862,70.715 103.202,70.375 103.669,70.375 104.875,71.581 120.005,71.581 122.441,69.145 122.643,69.145 123.02,68.767 123.02,68.542 123.482,68.08 123.482,67.668 123.56,67.59 123.56,65.922 122.486,64.848 121.302,64.848 120.99,64.536 120.08,64.536 119.948,64.404 119.948,64.168 120.062,64.054 121.388,64.054 121.631,63.811 121.631,63.396 U16.B7@121.901,63.126
DDR_DQS1_P: U16.C7 U27.N20 | length 34.1
  Top Layer w0.09: U27.N20@100.801,71.202 101.126,71.202 101.423,70.905 101.521,70.905 101.961,70.465 102.758,70.465 103.098,70.125 103.772,70.125 104.978,71.331 119.902,71.331 122.338,68.895 122.539,68.895 122.77,68.664 122.77,68.439 ; U16.C7@121.101,63.127 121.381,63.408 121.381,63.707 121.285,63.804 119.958,63.804 119.698,64.064 119.698,64.507 119.977,64.786 120.887,64.786 121.198,65.098 122.382,65.098 123.31,66.026 123.31,67.487 123.232,67.565 123.232,67.977 122.77,68.439
DDR_DQS2_N: U14.B7 U27.D22 | length 48.7
  Top Layer w0.09: U27.D22@102.4,78.4 102.464,78.4 102.846,78.782 135.508,78.782 136.603,77.687 136.603,77.138 136.277,76.812 136.277,76.659 136.573,76.363 137.063,76.363 137.261,76.561 137.729,76.561 138.92,75.37 139.117,75.37 139.677,74.81 139.677,74.489 139.77,74.396 139.77,72.304 139.677,72.211 139.677,71.369 139.167,70.859 137.315,70.859 137.19,70.735 137.19,70.539 137.333,70.396 137.731,70.396 138.091,70.036 138.091,69.637 U14.B7@138.376,69.352
DDR_DQS2_P: U14.C7 U27.D21 | length 49.2
  Top Layer w0.09: U27.D21@101.601,78.402 101.946,78.402 102.242,78.105 102.278,78.105 102.523,78.105 102.95,78.532 135.404,78.532 136.353,77.584 136.353,77.242 136.027,76.916 136.027,76.556 136.47,76.113 137.166,76.113 137.365,76.311 137.625,76.311 138.816,75.12 139.014,75.12 139.427,74.707 139.427,74.385 139.52,74.293 139.52,72.407 139.427,72.315 139.427,71.473 139.063,71.109 137.212,71.109 136.94,70.838 136.94,70.435 137.23,70.146 137.627,70.146 137.841,69.932 137.841,69.617 U14.C7@137.576,69.352
DDR_DQS3_N: U14.G3 U27.H21 | length 35.8
  Top Layer w0.09: U27.H21@101.601,75.202 101.601,75.227 101.876,75.502 102.565,75.502 102.675,75.392 121.179,75.392 123.11,73.461 124.776,73.461 126.587,71.65 130.702,71.65 130.967,71.385 133.937,71.385 134.652,72.1 134.652,72.286 134.387,72.552 U14.G3@134.376,72.552
DDR_DQS3_P: U14.F3 U27.H22 | length 35.2
  Top Layer w0.09: U27.H22@102.4,75.2 102.458,75.142 121.075,75.142 123.006,73.211 124.673,73.211 126.484,71.4 130.598,71.4 130.864,71.134 134.04,71.134 134.902,71.996 134.902,72.279 U14.F3@135.176,72.552
DDR_ODT: R159.1 U14.K1 U16.K1 U27.M17 | length 51.9
  Top Layer w0.09: U27.M17@98.4,72 98.4,72.013 98.825,72.438 v5(98.825,72.45) ; v4(115.1,67.525) U16.K1@115.5,67.925 ; v4(131.575,73.75) U14.K1@131.963,74.138
  Bottom Layer w0.09: v5(98.825,72.45) 98.825,72.81 98.936,72.921 99.132,72.921 99.463,72.59 99.794,72.59 100.184,72.98 104.258,72.98 106.865,70.373 106.865,67.626 108.996,65.495 113.609,65.495 114.695,66.581 114.695,66.899 114.79,66.994 114.79,67.188 115.1,67.498 v4(115.1,67.525) 115.555,67.98 115.555,68.755 116.683,69.883 117.809,69.883 119.776,71.85 125.151,71.85 125.299,71.702 130.073,71.702 131.18,72.809 131.18,73.164 131.497,73.48 131.497,73.698 131.576,73.777 137.351,73.777 138.041,73.087 138.488,73.087 R159.1@138.575,73
DDR_RASN: R168.1 U14.J3 U16.J3 U27.N17 | length 51.6
  Top Layer w0.09: U27.N17@98.4,71.2 98.457,71.2 98.62,71.363 98.738,71.363 v5(98.975,71.6) ; v4(116.226,65.75) 116.301,65.825 U16.J3@116.301,66.327 ; U14.J3@132.775,72.55 132.8,72.55 133.15,72.2 v4@133.175,72.2
  Bottom Layer w0.09: v5@98.975,71.592 99.386,71.181 101.446,71.181 102.085,71.82 103.778,71.82 105.705,69.893 105.705,67.146 108.316,64.535 115.654,64.535 116.226,65.106 v4(116.226,65.75) 117.075,65.75 119.571,68.247 119.571,69.486 119.665,69.58 123.618,69.58 124.714,70.676 131.651,70.676 133.145,72.17 v4(133.175,72.17) 135.695,69.65 136.2,69.65 136.345,69.505 137.865,69.505 138.075,69.295 R168.1@138.075,69.2
DDR_RESETN: R156.2 U14.T2 U16.T2 U27.F18 | length 39.5
  Top Layer w0.09: U27.F18@99.2,76.8 v5(99.6,77.2) ; v4(109.95,68.875) 109.95,68.501 109.876,68.427 109.876,67.379 110.128,67.127 U16.T2@110.701,67.127 ; v4(126.425,75.1) 126.425,74.726 126.351,74.652 126.351,73.604 126.603,73.352 U14.T2@127.176,73.352
  Bottom Layer w0.09: v5(99.6,77.2) 99.943,77.2 100.145,77.402 104.352,77.402 106.679,75.075 109.95,75.075 ; v4(109.95,68.875) 109.95,75.075 ; R156.2@123.75,75.075 109.95,75.075 ; R156.2@123.775,75.1 v4(126.425,75.1)
DDR_WEN: R163.1 U14.L3 U16.L3 U27.L18 | length 51.6
  Top Layer w0.09: U27.L18@99.2,72.8 99.44,72.8 99.94,72.3 v5(100.425,72.3) ; U16.L3@114.7,66.325 114.725,66.3 v4(114.725,65.75) ; U14.L3@131.175,72.55 131.2,72.55 v4@131.55,72.2
  Bottom Layer w0.09: v5(100.425,72.3) 100.37,72.3 100.076,72.006 100.076,71.881 100.176,71.781 101.226,71.781 101.845,72.4 104.018,72.4 106.285,70.133 106.285,67.386 108.656,65.015 114.455,65.015 114.723,65.283 v4@114.723,65.748 ; v4(114.725,65.75) 115.052,66.077 115.243,66.077 115.516,66.35 116.064,66.35 116.477,66.763 116.978,66.763 118.545,68.33 118.545,69.188 118.543,69.19 118.543,69.516 119.207,70.18 123.369,70.18 124.439,71.25 124.843,71.25 124.906,71.187 130.562,71.187 131.95,72.575 132.539,72.575 132.553,72.589 132.561,72.589 132.894,72.922 133.489,72.922 135.311,71.1 R163.1@138.575,71.1
  other v4: 131.575,72.17
eMMC.SDMMC2_CK: R49.1 U24.M6 U27.A20 | length 26
  Top Layer w0.09: U24.M6@112.775,89.85 113.025,90.1 113.025,90.454 113.171,90.6 113.925,90.6 114.175,90.85 114.375,90.85
  Top Layer w0.11: U27.A20@100.8,80.8 100.8,81.935 101.902,83.037 106.072,83.037 108.445,83.037 108.767,82.715 113.348,82.715 113.725,83.093 R49.1@113.725,83.685 113.725,84.582 115.25,86.107 115.25,90.35 114.75,90.85 114.375,90.85
eMMC.SDMMC2_CMD: R37.1 U24.M5 U27.F17 | length 28.4
  Top Layer w0.09: U27.F17@98.4,76.8 98.002,77.198 97.453,77.198 97.29,77.36 97.29,77.84 97.432,77.982 97.62,77.982 97.91,78.272 97.91,78.596 98.199,78.885 98.488,78.885 98.715,79.112 98.715,79.56 98.865,79.71 98.865,80.231 98.775,80.321 98.775,83.777 ; 107.071,91.1 109.975,91.1 110.3,90.775 111.35,90.775 111.525,90.6 112,90.6 112.3,90.3 112.3,89.825 U24.M5@112.775,89.35
  Top Layer w0.11: 98.775,83.777 99.787,84.789 99.787,87.507 102.287,90.007 102.88,90.6 R37.1@102.975,90.6 103.449,90.6 103.943,91.093 107.071,91.093
eMMC.SDMMC2_D0: R44.1 U24.A3 U27.B19 | length 25.9
  Top Layer w0.09: 99.75,81.05 99.695,80.995 99.695,80.674 100,80.369 U27.B19@100,80
  Top Layer w0.11: 99.75,81.05 99.75,82.762 101.528,84.541 102.178,84.541 102.363,84.725 102.363,86.308 102.482,86.428 R44.1@103.1,86.428 103.633,86.428 103.836,86.225 103.836,84.57 103.929,84.477 ; 103.932,84.474 103.929,84.477 ; U24.A3@107.275,88.35 106.824,88.35 106.475,88.001 106.475,86.332 107.27,85.537 107.27,84.724 107.023,84.477 106.406,84.477 106.162,84.477 106.071,84.568 106.071,85.579 105.98,85.67 105.798,85.67 105.707,85.579 105.707,84.566 105.616,84.475 105.434,84.475 105.343,84.566 105.343,85.593 105.252,85.684 105.07,85.684 104.979,85.593 104.979,84.566 104.888,84.475 104.706,84.475 104.615,84.566 104.615,85.593 104.524,85.684 104.342,85.684 104.251,85.593 104.251,84.568 104.16,84.477 104.105,84.477 103.929,84.477
eMMC.SDMMC2_D1: U24.A4 U27.E17 | length 24
  Top Layer w0.09: U27.E17@98.4,77.6 98.895,78.095 98.895,78.526 99.074,78.705 99.505,78.705 99.695,78.895 99.695,80.419 99.515,80.599 99.515,82.965 99.525,82.975
  Top Layer w0.11: 99.525,82.965 99.525,82.975 101.442,84.892 101.442,85.031 101.442,85.45 101.533,85.541 101.944,85.541 102.035,85.632 102.035,85.814 101.944,85.905 101.493,85.905 101.402,85.996 101.402,86.178 101.493,86.269 101.944,86.269 102.035,86.36 102.035,86.542 101.944,86.633 101.533,86.633 101.442,86.724 101.442,86.911 101.442,87.057 101.525,87.14 103.849,87.14 104.268,87.14 104.359,87.049 104.359,86.182 104.45,86.091 104.632,86.091 104.723,86.182 104.723,87.061 104.814,87.152 104.996,87.152 105.087,87.061 105.087,86.182 105.178,86.091 105.36,86.091 105.451,86.182 105.451,87.049 105.542,87.14 105.917,87.14 105.923,87.146 106.102,87.325 106.102,88.132 106.82,88.85 U24.A4@107.275,88.85
eMMC.SDMMC2_D2: U24.A5 U27.C18 | length 25.1
  Top Layer w0.09: 99.155,83.28 99.155,80.45 99.335,80.27 99.335,79.361 99.2,79.226 U27.C18@99.2,79.2 ; 106.195,89.516 106.353,89.358 107.267,89.358 U24.A5@107.275,89.35
  Top Layer w0.11: 99.165,83.28 100.606,84.721 100.606,87.166 102.247,88.807 102.446,89.006 102.575,89.006 102.666,88.915 102.666,88.55 102.757,88.459 102.939,88.459 103.03,88.55 103.03,89.502 103.121,89.593 103.303,89.593 103.394,89.502 103.394,88.55 103.485,88.459 103.667,88.459 103.758,88.55 103.758,89.502 103.849,89.593 104.031,89.593 104.122,89.502 104.122,88.55 104.213,88.459 104.395,88.459 104.486,88.55 104.486,89.502 104.577,89.593 104.759,89.593 104.85,89.502 104.85,88.55 104.941,88.459 105.123,88.459 105.214,88.55 105.214,89.502 105.305,89.593 105.487,89.593 105.578,89.502 105.578,88.917 105.669,88.826 105.851,88.826 105.942,88.917 105.942,89.425 106.033,89.516 106.103,89.516 106.195,89.516
eMMC.SDMMC2_D3: U24.B2 U27.C19 | length 23.8
  Top Layer w0.09: U27.C19@100,79.2 100.31,79.51 100.31,81.055 ; 107.525,86.9 107.525,87.6 U24.B2@107.775,87.85
  Top Layer w0.11: 100.31,81.055 100.299,81.065 100.299,82.373 101.646,83.72 110.396,83.72 110.461,83.784 110.461,83.796 110.461,84.215 110.552,84.306 111.194,84.306 111.285,84.397 111.285,84.579 111.194,84.67 110.539,84.67 110.448,84.761 110.448,84.943 110.539,85.034 111.194,85.034 111.285,85.125 111.285,85.307 111.194,85.398 110.552,85.398 110.461,85.489 110.461,85.916 110.461,85.974 110.396,86.038 107.887,86.038 107.525,86.4 107.525,86.9
eMMC.SDMMC2_D4: U24.B3 U27.A19 | length 24.7
  Top Layer w0.09: 107,88.1 107.525,88.1 U24.B3@107.775,88.35
  Top Layer w0.11: U27.A19@100,80.8 100,82.538 101.546,84.084 108.332,84.084 108.387,84.084 108.478,84.175 108.478,85.263 108.569,85.354 108.751,85.354 108.842,85.263 108.842,84.122 108.933,84.031 109.115,84.031 109.206,84.122 109.206,85.263 109.297,85.354 109.479,85.354 109.57,85.263 109.57,84.175 109.661,84.084 109.866,84.084 109.947,84.084 110.053,84.19 110.053,85.549 109.938,85.664 107.753,85.664 106.814,86.603 106.814,87.914 107,88.1
eMMC.SDMMC2_D5: U24.B4 U27.D18 | length 25
  Top Layer w0.09: U27.D18@99.2,78.4 99.562,78.4 99.872,78.71 99.948,78.71 100.49,79.252 100.51,79.272 100.51,81.16 100.55,81.2 ; U24.B4@107.775,88.85 108.025,88.6 108.025,87.75 108.025,87.15
  Top Layer w0.11: 100.55,81.2 100.55,82.184 101.775,83.409 106.072,83.409 111.428,83.409 111.596,83.577 111.596,86.171 111.422,86.345 108.142,86.345 108.025,86.462 108.025,87.15
eMMC.SDMMC2_D6: U24.B5 U27.E16 | length 23.9
  Top Layer w0.09: U27.E16@97.6,77.6 98.09,78.09 98.09,78.375 98.095,78.38 98.095,78.526 98.274,78.705 98.563,78.705 98.895,79.037 98.895,79.345 99.045,79.495 99.045,80.305 98.965,80.385 98.965,83.61 ; 106.499,89.612 106.803,89.612 106.815,89.6 107.525,89.6 U24.B5@107.775,89.35
  Top Layer w0.11: 98.975,83.625 100.173,84.823 100.173,87.357 102.876,90.06 103.393,90.06 104.072,90.739 104.491,90.739 104.582,90.648 104.582,90.022 104.673,89.931 104.855,89.931 104.946,90.022 104.946,90.659 105.037,90.75 105.219,90.75 105.31,90.659 105.31,90.022 105.401,89.931 105.583,89.931 105.674,90.022 105.674,90.648 105.765,90.739 106.071,90.739 106.179,90.63 106.195,90.615 106.195,89.916 106.499,89.612
eMMC.SDMMC2_D7: U24.B6 U27.D17 | length 24
  Top Layer w0.09: U27.D17@98.4,78.4 98.44,78.44 98.552,78.44 98.997,78.885 99.431,78.885 99.515,78.969 99.515,80.345 99.335,80.525 99.335,83.11 ; 106.195,88.716 106.579,89.1 107.879,89.1 108.025,89.246 108.025,89.6 U24.B6@107.775,89.85
  Top Layer w0.11: 99.355,83.11 101.049,84.804 101.049,87.051 101.524,87.526 101.95,87.525 102.049,87.624 102.049,88.051 102.171,88.172 102.52,88.172 102.939,88.172 103.03,88.081 103.03,87.56 103.121,87.469 103.303,87.469 103.394,87.56 103.394,88.107 103.485,88.198 103.667,88.198 103.758,88.107 103.758,87.56 103.849,87.469 104.031,87.469 104.122,87.56 104.122,88.107 104.213,88.198 104.395,88.198 104.486,88.107 104.486,87.56 104.577,87.469 104.759,87.469 104.85,87.56 104.85,88.107 104.941,88.198 105.123,88.198 105.214,88.107 105.214,87.56 105.305,87.469 105.487,87.469 105.578,87.56 105.578,88.099 105.726,88.247 106.195,88.716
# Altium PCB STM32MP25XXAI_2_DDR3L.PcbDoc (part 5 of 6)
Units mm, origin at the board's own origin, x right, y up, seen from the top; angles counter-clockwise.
Board outline 172 x 137 mm, 6 copper layers (Top Layer, Signal Layer 1, Signal Layer 2, Signal Layer 3, Signal Layer 4, Bottom Layer), stack 2.079 mm thick; 237 components, 152 nets, 1304 pads, 909 vias.
Unrouted connection lines stored in the file: 13.

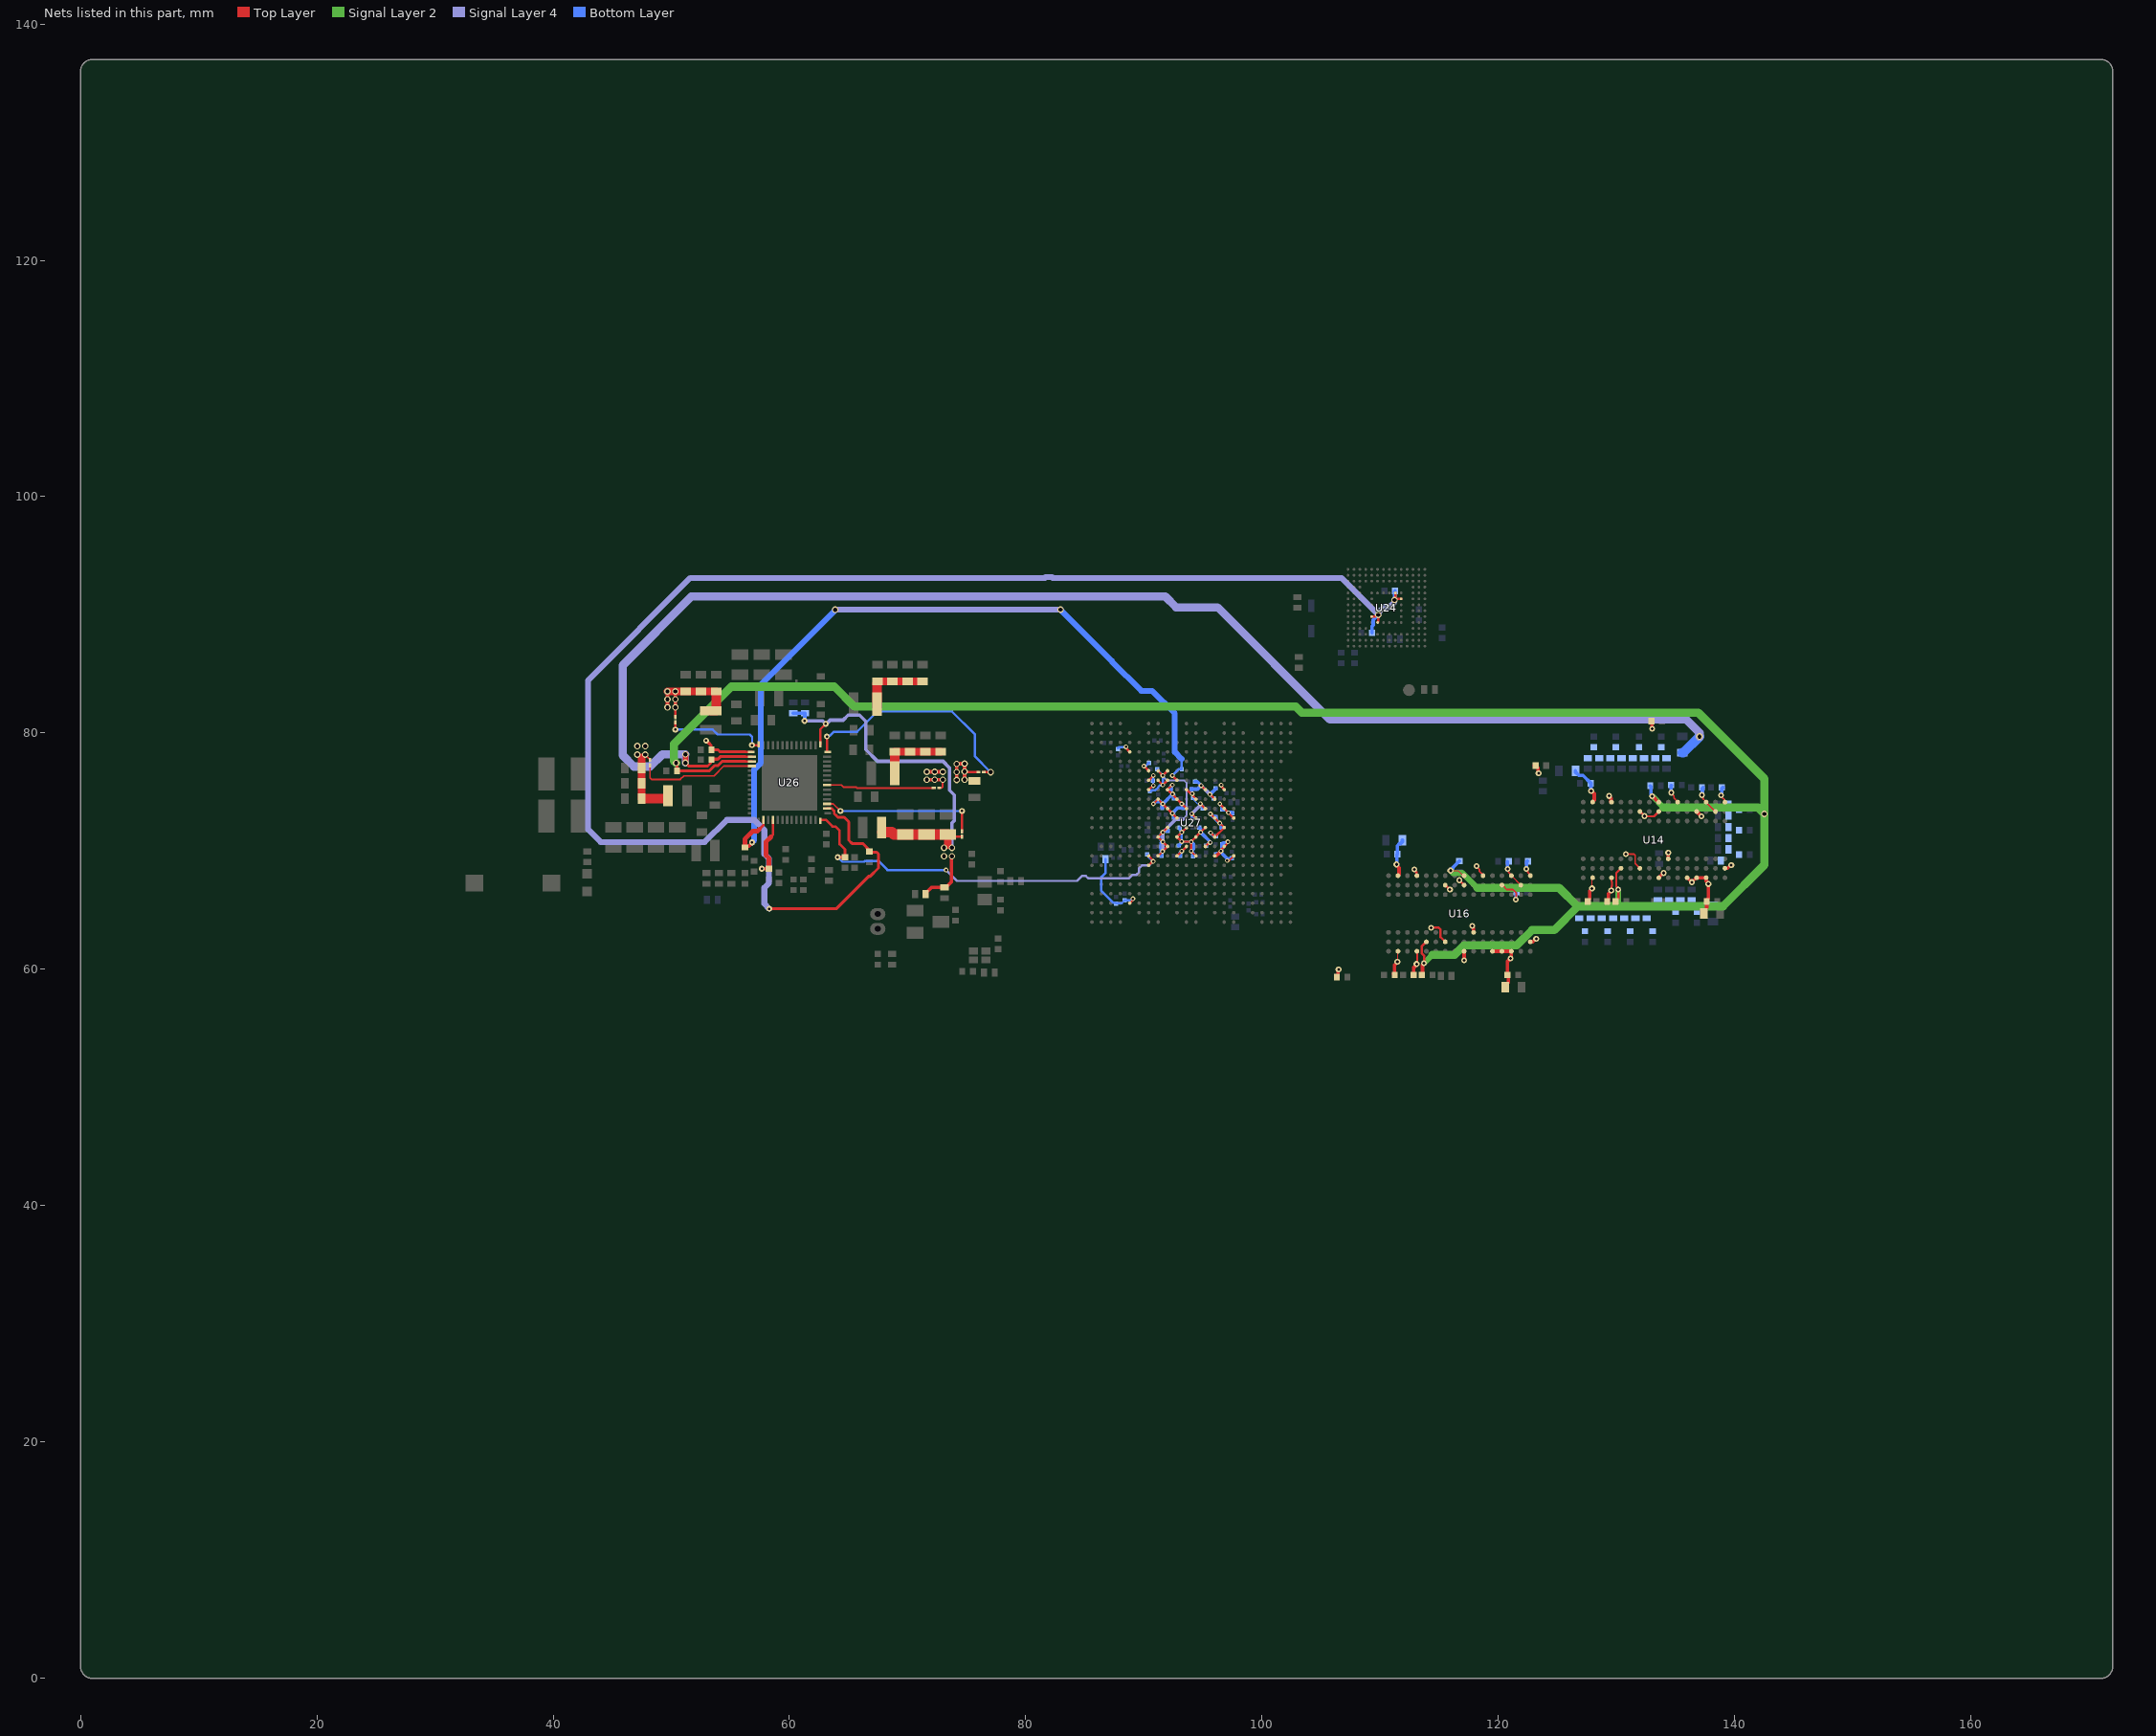
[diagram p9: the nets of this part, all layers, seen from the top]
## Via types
v1: diameter 0.55, hole 0.35, Top Layer to Bottom Layer, 421 vias
v2: diameter 0.4, hole 0.2, Top Layer to Bottom Layer, tented both sides, 169 vias
v3: diameter 0.5, hole 0.2, Top Layer to Bottom Layer, 146 vias
v4: diameter 0.5, hole 0.25, Top Layer to Bottom Layer, 145 vias
v5: diameter 0.4, hole 0.2, Top Layer to Bottom Layer, 28 vias

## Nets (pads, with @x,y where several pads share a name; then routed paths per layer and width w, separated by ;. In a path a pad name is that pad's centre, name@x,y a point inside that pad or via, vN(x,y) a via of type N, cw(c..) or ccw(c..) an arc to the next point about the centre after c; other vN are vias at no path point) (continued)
VDD_DDR: C39.2 C41.2 C48.2 C53.2 C54.1 C55.2 C56.2 C57.2 C58.2 C59.2 C60.2 C76.2 C77.2 C80.2 C140.2 C143.2 C146.2 C148.2 C149.2 C173.2 C191.2 C194.2 C200.2 C202.2 C360.2 C361.2 C363.2 C364.2 C367.2 C373.2 C374.2 C384.2 C390.2 L5.2 LNK8.2 U14.A1 U14.A8 U14.B2 U14.C1 U14.C9 U14.D2 U14.D9 U14.E9 U14.F1 U14.G7 U14.H2 U14.H9 U14.K2 U14.K8 U14.N1 U14.N9 U14.R1 U14.R9 U16.A1 U16.A8 U16.B2 U16.C1 U16.C9 U16.D2 U16.D9 U16.E9 U16.F1 U16.G7 U16.H2 U16.H9 U16.K2 U16.K8 U16.N1 U16.N9 U16.R1 U16.R9 U26.43 U27.K15 U27.L14 U27.L16 U27.M15 U27.N14 U27.P15 U27.R14 U27.R16 | length 78.9
  Top Layer w0.1: U27.R16@97.575,69.6 U27.R16@97.6,69.6 ; v4@111.476,60.625 U16.R9@111.476,61.502 ; v4@127.951,66.85 U14.R9@127.951,67.727
  Top Layer w0.125: U16.C1@121.1,67.928 U16.B2@121.901,67.127
  Top Layer w0.15: v1(47.798,78.165) 48.2,77.763 LNK8.2@48.2,77.723 ; v4@113.134,60.508 U16.N9@113.134,61.492 ; v4@118.15,68.75 v4(118.15,68.725) 118.15,68.68 118.401,68.43 118.401,68.279 118.7,67.979 U16.F1@118.7,67.925 ; U16.D2@120.301,67.127 120.354,67.127 120.732,66.749 121.24,66.749 121.5,66.488 v4@121.5,65.975 ; v4(120.775,68.5) 120.842,68.433 120.842,68.237 121.1,67.979 U16.C1@121.1,67.928 ; U16.C1@121.062,67.966 U16.C1@121.1,67.928 ; U16.C1@121.1,67.925 U16.C1@121.1,67.928 ; v4@122.425,68.425 122.425,68.355 122.492,68.288 122.492,68.203 122.625,68.07 122.625,68.068 122.7,67.993 U16.A1@122.7,67.925 ; C48.2@122.976,77.252 C48.2@123.126,77.102 ; v4(129.55,66.675) 129.575,66.7 129.575,67.024 129.6,67.049 129.6,67.401 129.575,67.426 U14.N9@129.575,67.75 ; v4@130.775,69.75 131.485,69.75 131.573,69.662 131.573,68.952 U14.K8@131.975,68.55 ; v4(132.375,72.97) v4@132.397,72.948 ; v4(134.625,74.95) 134.625,74.88 134.851,74.655 134.851,74.504 135.15,74.204 U14.F1@135.15,74.15 ; v4@137.225,74.725 137.292,74.658 137.292,74.462 137.55,74.204 U14.C1@137.55,74.153 ; C364.2@137.376,64.827 C364.2@137.376,64.951 ; C364.2@137.376,64.952 137.625,65.201 137.626,65.202 C363.2@137.626,65.877 ; U14.C1@137.512,74.191 U14.C1@137.55,74.153 ; U14.C1@137.55,74.15 U14.C1@137.55,74.153 ; U14.C1@137.575,74.15 U14.B2@138.375,73.35 ; v4@138.836,74.7 138.836,74.636 139.137,74.335 139.137,74.188 U14.A1@139.175,74.15
  Top Layer w0.175: v4@132.397,72.948 133.172,72.948
  Top Layer w0.2: v2@95.6,73.15 v2(95.625,73.15) 95.65,73.15 U27.L14@96,72.8 v2(96.42,72.379) ; v2@95.625,71.575 U27.N14@96,71.2 U27.M15@96.8,72 v2@96.421,72.379 ; v2@96.4,74 U27.K15@96.8,73.6 v2(97.15,73.25) ; v2(96.525,70) 96.563,70.038 96.563,70.163 U27.P15@96.8,70.4 97.1,70.7 v2(97.1,70.8) ; v2(97.05,69.2) 97.2,69.2 U27.R16@97.6,69.6 ; v2@97.125,73.275 v2(97.15,73.25) ; U27.L16@97.6,72.8 v2(97.15,73.25) ; v4(112.892,68.45) 112.892,68.418 113.063,68.248 113.063,67.965 U16.N1@113.101,67.927 ; v4(114.3,63.525) 114.949,63.525 115.093,63.381 ; 115.093,62.732 U16.K8@115.5,62.325 ; 115.1,62.732 115.1,63.381 ; U16.K2@115.5,67.125 115.51,67.125 v4@115.89,66.745 ; v4@115.88,66.745 v4@115.89,66.745 ; v4(115.9,66.745) v4@115.89,66.745 ; v4(116.7,67.545) 116.7,67.535 117.1,67.135 U16.H2@117.1,67.125 ; U16.H9@117.067,61.489 U16.H9@117.101,61.455 ; v4(117.102,60.76) v4(117.102,60.76) ; U14.K2@132.001,73.352 132.353,73 v4@132.375,73 ; 133.172,72.948 U14.H2@133.576,73.352
  Top Layer w0.21: 56.275,78.4 U26.43@56.825,78.4
  Top Layer w0.25: 53.195,79.125 53.199,79.125 53.345,78.979 53.345,78.685 C39.2@53.455,78.575 ; C39.2@53.505,78.575 53.975,78.575 54.15,78.4 56.275,78.4
  Top Layer w0.275: U14.H9@133.576,67.752 v4(133.976,68.152) ; U14.E9@135.977,67.761 136.363,67.375 v4(136.375,67.375) ; v4@136.375,67.475 136.402,67.449 136.449,67.449 136.713,67.713 136.717,67.713 136.755,67.75 U14.D9@136.775,67.75
  Top Layer w0.3: v3@52.944,79.376 53.195,79.125 ; U27.R14@96,69.6 96.125,69.6 v2(96.525,70) ; C77.2@106.325,59.35 106.43,59.455 106.43,59.9 v4@106.475,59.944 ; C373.2@111.151,59.627 111.2,59.676 111.2,60.349 111.45,60.599 v4(111.45,60.625) ; v4@111.375,68.86 111.375,68.824 111.6,68.599 111.6,68.052 111.5,67.952 U16.R1@111.5,67.925 ; C374.2@112.751,59.627 112.838,59.714 112.838,60.158 113.075,60.396 v4(113.075,60.45) ; v4(117.102,60.76) U16.H9@117.101,61.455 ; v4@117.775,63.65 117.775,63.596 117.891,63.48 117.891,63.135 U16.G7@117.9,63.125 ; U16.E9@119.5,61.525 U16.D9@120.3,61.525 U16.C9@121.093,61.525 ; C80.2@120.55,58.6 120.85,58.9 120.85,59.625 C76.2@120.806,59.669 ; C76.2@120.775,59.625 120.775,60.671 121.025,60.921 v4(121.025,60.925) 121.025,60.979 121.091,61.045 121.091,61.515 U16.C9@121.1,61.525 ; v4@120.775,68.446 v4(120.775,68.5) ; v4@121.488,65.988 v4@121.5,65.975 ; v4(122.375,68.5) v4@122.375,68.564 ; U16.A8@122.753,62.325 122.9,62.325 123.175,62.6 v4@123.2,62.6 ; C48.2@123.125,77.3 123.125,77.275 123.362,77.038 123.362,76.638 v4(123.4,76.6) ; C360.2@127.626,65.852 127.731,65.957 127.731,66.656 v4(127.925,66.85) ; v4@127.825,75.125 v4(127.85,75.1) 128.106,74.844 128.106,74.321 127.975,74.191 U14.R1@127.975,74.15 ; C361.2@129.226,65.852 129.313,65.939 129.313,66.383 129.55,66.621 v4(129.55,66.675) ; v4(129.367,74.675) 129.367,74.643 129.538,74.473 129.538,74.19 U14.N1@129.575,74.15 ; C367.2@132.95,81 132.987,80.963 132.987,80.387 v4(133.025,80.35) ; U14.G7@134.375,69.35 v4(134.375,69.875) ; U14.D9@136.775,67.75 U14.C9@137.575,67.75 137.585,67.74 137.585,67.47 137.775,67.279 v4(137.775,67.225) 137.775,66.026 C363.2@137.73,65.981 ; U14.D2@136.775,73.35 v4(137.175,72.95) ; v4@137.225,74.725 v4@137.263,74.763 ; C364.2@137.376,64.951 137.625,65.2 ; 137.625,65.201 C363.2@137.625,65.85 ; C363.2@137.627,65.877 C363.2@137.73,65.98 ; U14.A8@139.175,68.55 139.386,68.55 v4@139.696,68.86
  Top Layer w0.64: C202.2@47.475,74.45 C41.2@47.475,75.75 C200.2@47.475,77.05 ; 47.475,77.495 47.475,77.925
  Top Layer w0.8: C202.2@47.7,74.45 L5.2@49.475,74.45
  Signal Layer 4 w0.3: v2@96.356,72.394 96.406,72.394 v2@96.425,72.375
  Bottom Layer w0.2: v2@96.4,74 96.4,73.946 96.549,73.796 96.549,73.599 C60.2@96.624,73.524 ; C60.2@96.631,73.524 96.704,73.452 96.933,73.452 97.135,73.25 v2(97.15,73.25) ; v2@97.125,73.275 v2(97.15,73.25) ; v2@97.15,73.23 v2(97.15,73.25)
  Bottom Layer w0.3: v2@95.6,71.575 95.9,71.275 C55.2@96.1,71.275 ; v2@95.6,73.15 v2(95.625,73.15) ; v2@95.627,73.15 v2(95.625,73.15) ; C59.2@96.1,69.725 96.175,69.8 96.308,69.8 96.6,70.092 96.6,70.575 C54.1@96.625,70.6 96.7,70.675 96.921,70.675 97.046,70.8 v2(97.1,70.8) ; v2(96.42,72.379) 96.394,72.379 96.124,72.649 96.124,72.687 96.099,72.712 96.099,72.85 C56.2@96.074,72.875 96.049,72.9 95.875,72.9 v2(95.625,73.15) ; v2@96.425,72.375 96.425,72.347 96.549,72.223 96.549,71.999 C57.2@96.574,71.974 ; v2(96.525,70) 96.544,69.981 96.544,69.869 v2@97.031,69.383 ; v2(97.05,69.2) 97.05,69.375 97.425,69.375 C53.2@97.45,69.4 ; v2@97.125,73.275 97.425,73.275 C58.2@97.5,73.2 ; v4(111.375,68.875) 111.413,68.913 111.413,69.713 C384.2@111.45,69.75 111.45,70.454 111.626,70.63 111.705,70.63 111.875,70.8 C173.2@111.875,70.925 ; v4@120.775,68.446 v4(120.775,68.5) C191.2@120.775,69.125 ; C194.2@121.475,66.625 121.488,66.612 121.488,65.988 v4@121.5,65.975 ; v4@122.396,68.496 122.396,69.096 C390.2@122.45,69.15 ; C140.2@126.525,76.8 126.525,76.675 126.794,76.406 127.169,76.406 127.825,75.75 127.825,75.125 v4(127.85,75.1) ; v4(134.625,74.95) 134.625,75.55 C146.2@134.637,75.562 ; v4@137.225,74.725 137.263,74.763 137.263,75.313 C149.2@137.325,75.375 ; v4@138.825,74.7 138.825,74.754 138.895,74.824 138.895,75.27 C148.2@139,75.375
  other v1: 47.123,78.165 47.123,78.89 47.798,78.89
  other v2: 95.65,71.55 96.425,74
  other v3: 52.95,79.348
  other v4: 106.475,59.998 123.2,62.575 117.775,63.675 121.475,65.9 139.71,68.825 130.775,69.745 138.847,74.725 137.225,74.75
VDD_DDR_FB: LNK8.1 U26.46 | length 10.2
  Top Layer w0.15: LNK8.1@48.2,77.273 48.2,76.19 48.317,76.073 50.767,76.073 51.067,76.373 51.737,76.373 51.739,76.375 53.627,76.375 54.452,77.2 U26.46@56.83,77.2
VDD_EMMC: C177.2 C180.2 C190.1 U24.E6 U24.F5 U24.J10 U24.K9 U26.16 | length 133.6
  Top Layer w0.2: U24.E6@109.275,89.85 109.58,89.85 109.73,90 v1(109.825,90) ; U24.F5@109.775,89.35 109.775,89.358 109.825,89.408 v1@109.825,89.85 ; v1(111.2,91.25) v1@111.275,91.325 ; U24.J10@111.275,91.85 111.275,91.42 111.267,91.412 111.267,91.333 v1@111.275,91.325 ; U24.K9@111.775,91.35 111.395,91.35 111.362,91.317 111.283,91.317 v1@111.275,91.325
  Top Layer w0.21: U26.16@63.17,73.6 63.6,73.6 63.788,73.412 63.788,73.188 63.934,73.041
  Top Layer w0.25: v3(58.3,65.125) 63.96,65.125 66.7,67.865 66.822,67.865 67.535,68.578 67.535,69.764 67.389,69.91 66.805,69.91 C190.1@66.75,69.965 ; 63.932,73.038 64.098,72.872 64.628,72.872 65.025,72.475 65.025,70.925 65.3,70.65 66.195,70.65 C190.1@66.75,70.095
  Signal Layer 4 w0.5: v3(58.3,65.125) 57.872,65.553 57.872,66.908 58.265,67.301 58.265,69.369 57.872,69.762 57.872,71.786 57.009,72.649 54.703,72.649 52.827,70.773 44.024,70.773 42.958,71.839 42.958,84.457 51.616,93.115 81.606,93.115 81.691,93.2 82.209,93.2 82.294,93.115 85.406,93.115 85.416,93.125 85.934,93.125 85.944,93.115 106.726,93.115 v1@109.678,90.163 ; v1(109.825,90) 109.835,90.01 109.835,90.196 110.259,90.62 110.475,90.62 110.737,90.62 111.2,91.083 v1(111.2,91.25)
  Bottom Layer w0.3: C180.2@109.3,88.475 109.3,89.049 109.4,89.149 109.4,89.575 v1(109.825,90) ; v1(111.2,91.25) 111.225,91.275 111.225,92 C177.2@111.25,92.025
VDD_SDCARD: C142.1 U26.4 | length 5.1
  Top Layer w0.21: 58.425,71.2 58.6,71.375 U26.4@58.6,72.63
  Top Layer w0.3: v3(57.665,68.51) C142.1@58.275,68.51
  Top Layer w0.4: C142.1@58.275,68.51 58.275,69.393 58.01,69.658 58.01,70.785 58.425,71.2
VDDA1V8_AON: C189.2 C234.2 U26.14 U27.R7 U27.T7 | length 35.8
  Top Layer w0.2: U27.T7@90.4,68.8 90.687,69.087 90.757,69.087 v2(90.795,69.125) 90.795,69.178 90.4,69.573 U27.R7@90.4,69.6
  Top Layer w0.21: U26.14@62.6,72.63 63.11,72.63 63.648,72.092 63.887,72.092 64.245,71.734 64.245,70.602 64.7,70.147 C189.2@64.7,69.49
  Top Layer w0.3: v3(64.09,69.49) C189.2@64.7,69.49
  Signal Layer 4 w0.2: v2(73.253,68.406) 73.259,68.406 74.183,67.482 84.342,67.482 84.76,67.9 85.091,67.9 85.302,67.689 88.724,67.689 89.034,68 89.2,68 89.366,68 89.6,68.234 89.6,68.566 89.835,68.8 90.47,68.8 v2(90.795,69.125) v2@90.726,69.125
  Bottom Layer w0.2: v3(64.09,69.49) 64.48,69.1 66.321,69.1 66.392,69.171 67.535,69.171 68.3,68.406 v2(73.253,68.406) ; C234.2@90.275,69.735 90.441,69.569 90.441,69.443 90.76,69.125 v2(90.795,69.125)
VDDCORE: C1.1 C2.2 C3.2 C4.1 C5.2 C6.2 C22.2 C23.2 C24.2 C66.2 C69.2 C70.2 C183.2 L2.2 LNK2.2 R249.1 U27.D5 U27.F7 U27.G7 U27.H7 U27.H9 U27.J8 U27.J10 U27.K9 U27.K11 U27.L10 | length 26.2
  Top Layer w0.2: C22.2@71.275,84.375 C22.2@71.323,84.423 ; v1@74.87,76.685 LNK2.2@75.98,76.685 ; v2(88.475,78.825) 88.475,78.725 U27.D5@88.8,78.4 ; v2(90,77.2) U27.F7@90.4,76.8 U27.F7@90.425,76.8 ; U27.H7@90.4,75.2 90.425,75.2 90.775,75.55 v2(90.8,75.55) ; U27.G7@90.4,76 v2(90.8,76.4) ; v2(90.8,74) U27.J8@91.2,74.4 v2(91.6,74) v2(92.4,73.2) U27.L10@92.8,72.8 ; v2(92.4,75.6) U27.H9@92,75.2 v2@92.425,74.775 ; v2(92.425,74.85) v2@92.425,74.775 ; U27.K11@93.6,73.6 v2(93.2,74) U27.J10@92.8,74.4 v2@92.425,74.775
  Top Layer w0.3: v1@74.151,77.404 v1(74.826,77.404) v1(74.826,76.729) ; v1(74.156,76.024) v1(74.156,76.699) v1(74.156,77.374) ; v1(74.826,76.054) v1(74.826,76.729) ; v1@74.87,76.685 v1(74.826,76.729)
  Top Layer w0.64: C183.2@67.45,84.375 C24.2@68.725,84.375 C23.2@70,84.375 C22.2@71.275,84.375
  Top Layer w0.8: L2.2@67.415,82.2 L2.2@67.415,82.45 C183.2@67.415,84.173
  Bottom Layer w0.2: C70.2@87.8,78.7 87.9,78.8 88.038,78.8 v2@88.4,78.8 ; v2(90,77.2) 90.038,77.238 90.188,77.238 C66.2@90.425,77.475 ; v2(90.8,75.55) 90.777,75.572 90.777,75.948 C69.2@90.755,75.97 90.777,75.992 90.777,76.378 v2(90.8,76.4)
  Bottom Layer w0.3: v2(90.8,74) 91,74.2 91.4,74.2 v2(91.6,74) ; C3.2@91.55,73.65 91.55,73.95 v2(91.6,74) ; v2(92.4,75.6) 92.275,75.475 C4.1@92.275,75.25 92.275,75 v2(92.425,74.85) ; C1.1@92.55,72.825 92.55,73.05 v2(92.4,73.2) 92.85,73.65 C2.2@93.326,73.65 93.325,73.875 v2(93.2,74) ; C5.2@92.551,74.475 92.55,74.725 v2(92.425,74.85) ; v2(91.6,74) 92.425,74.825 v2(92.425,74.85)
VDDCORE_FB: LNK2.1 U26.28 | length 19.9
  Top Layer w0.2: U26.28@63.17,78.4 v3(63.17,79.7) ; LNK2.1@76.444,76.687 v1@77.031,76.685
  Bottom Layer w0.2: v3(63.17,79.7) 63.227,79.757 63.401,79.757 63.754,80.111 65.734,80.111 67.457,81.833 73.744,81.833 75.675,79.902 75.675,78.041 v1(77.033,76.683)
VDDCPU: C13.1 C14.2 C15.2 C16.1 C17.2 C25.2 C26.2 C27.2 C28.2 C31.2 L3.2 LNK4.1 U27.H11 U27.H13 U27.H15 U27.J12 U27.J14 U27.K13 U27.L12 | length 21.1
  Top Layer w0.2: LNK4.1@50.35,81.35 v1(50.35,82.173) ; U27.H11@93.6,75.2 93.627,75.2 93.924,74.903 94.052,74.903 94.128,74.827 94.128,74.699 94.4,74.427 U27.J12@94.4,74.4 ; v2(94.045,73.155) U27.L12@94.4,72.8 ; v2(94.775,74.005) 95.18,73.6 U27.K13@95.2,73.6 ; v2(94.845,75.555) U27.H13@95.2,75.2 ; v2(95.595,74.805) U27.J14@96,74.4 ; v2(96.54,75.591) 96.578,75.553 96.578,75.449 96.8,75.227 U27.H15@96.8,75.2
  Top Layer w0.3: v1(49.675,82.173) v1(49.675,82.848) v1(49.675,83.523) v1(50.35,83.523) v1(50.35,82.848) v1(50.35,82.173)
  Top Layer w0.64: v1(49.675,83.523) 49.675,83.525 C27.2@51.2,83.525 C28.2@52.5,83.525 C26.2@53.8,83.525
  Top Layer w0.8: L3.2@53.35,81.875 53.8,81.875 53.8,83.173
  Signal Layer 4 w0.3: v2(94.045,73.155) 94.756,73.866 94.756,73.986 v2(94.775,74.005) ; v2(94.845,75.555) v2(95.595,74.805)
  Bottom Layer w0.1: C14.2@94.15,74.48 94.15,74.379 94.524,74.005 v2(94.775,74.005)
  Bottom Layer w0.2: v2(94.045,73.155) 94.045,72.855 C31.2@94.125,72.775 ; v2@94.775,73.978 v2(94.775,74.005) ; C13.1@94.95,73.625 94.95,73.803 ; v2(95.595,74.805) 95.633,74.767 95.633,74.692 C15.2@95.875,74.45
  Bottom Layer w0.3: v2(94.095,74.865) 94.095,74.892 94.05,74.937 94.05,75.225 C25.2@94.025,75.25 94.548,75.25 v2@94.853,75.555 ; C17.2@94.325,75.875 94.525,75.875 v2(94.845,75.555) ; v2@94.775,73.978 94.95,73.803 ; v2(95.595,74.805) C16.1@96.095,75.305
VDDCPU_FB: LNK4.2 U26.42 | length 8.6
  Top Layer w0.2: v3(50.35,80.29) LNK4.2@50.35,80.9 ; v3(56.825,78.975) U26.42@57.395,78.975
  Bottom Layer w0.2: v3@50.37,80.287 53.499,80.287 53.914,79.872 56.643,79.872 56.845,79.67 v3@56.845,78.972
VDDGPU: C7.2 C8.2 C9.2 C10.2 C11.1 C12.2 C34.2 C35.2 C36.2 C37.2 L4.2 LNK7.2 U27.M11 U27.M13 U27.N10 U27.N12 U27.P13 U27.R12 | length 21.3
  Top Layer w0.15: LNK7.2@72.675,75.35 72.682,75.358 72.885,75.358 72.973,75.445 v1(72.973,76.038)
  Top Layer w0.2: C35.2@73.05,78.393 C35.2@73.098,78.345 ; U27.M11@93.6,72 v2(93.2,71.6) U27.N10@92.8,71.2 93.197,70.803 93.997,70.803 v2(94,70.8) ; U27.R12@94.4,69.6 v2(94,70) v2(94,70.8) ; U27.P13@95.2,70.4 95.487,70.687 95.562,70.687 v2(95.6,70.725) ; U27.M13@95.2,72 v2(94.8,71.6) v2(94,70.8)
  Top Layer w0.3: v1(71.623,76.038) v1(72.298,76.038) v1(72.973,76.038) ; v1(71.623,76.713) v1(72.298,76.713) v1(72.973,76.713)
  Top Layer w0.64: C37.2@68.9,78.4 C36.2@70.2,78.4 C34.2@71.5,78.4 C35.2@72.8,78.4
  Top Layer w0.8: L4.2@68.925,76.6 68.925,78.073
  Bottom Layer w0.2: C9.2@93.025,72 93.025,71.775 v2(93.2,71.6) 93.197,71.598 93.197,70.808 93.195,70.805 93.197,70.803 93.997,70.803 v2(94,70.8) ; v2(95.6,70.725) v2@95.61,70.715
  Bottom Layer w0.3: C10.2@92.95,70.48 93.176,70.706 93.176,70.786 v2@93.195,70.805 ; v2(94,70.8) 94.175,70.625 94.175,70.175 v2(94,70) 94.2,69.8 C12.2@94.2,69.575 ; C7.2@94.675,72 94.8,71.875 v2(94.8,71.6) 94.833,71.567 95.581,70.819 95.581,70.744 v2(95.6,70.725) 95.581,70.706 95.506,70.706 C11.1@95.25,70.45
  other v2: 93.2,70.805
VDDGPU_FB: LNK7.1 U26.21 | length 9.3
  Top Layer w0.15: U26.21@63.05,75.6 64.383,75.6 64.56,75.423 65.64,75.423 65.713,75.35 LNK7.1@72.225,75.35
VDDIO: C19.2 C44.1 C45.2 C46.2 C47.1 C52.2 C73.2 C74.2 C186.2 C187.2 L6.2 LNK11.2 R27.2 R67.2 R260.2 R261.2 U26.29 U27.F8 U27.F9 U27.G8 U27.G9 U27.M9 U27.N8 U27.P9 U27.P11 U27.R8 U27.R10 | length 61.4
  Top Layer w0.2: U26.29@62.6,79.045 62.6,80.298 v3(63.075,80.773) ; C186.2@73.4,71.4 73.585,71.215 LNK11.2@74.6,71.215 ; U27.R8@91.2,69.6 v2(91.575,69.975) U27.P9@92,70.4 v2(91.6,70.8) U27.N8@91.2,71.2 v2(91.6,71.6) U27.M9@92,72 ; U27.G8@91.2,76 91.599,75.6 U27.G9@92,76 ; U27.F8@91.2,76.8 v2(91.6,76.4) U27.F9@92,76.8 ; U27.R10@92.8,69.6 v2(93.2,70) U27.P11@93.6,70.4
  Top Layer w0.3: R67.2@71.525,66.375 71.525,66.44 72.01,66.925 R27.2@73.125,66.925 73.23,67.03 73.339,67.03 73.712,67.402 73.712,69.52 v1(73.752,69.56) ; v1(73.077,69.56) v1@73.125,69.512
  Top Layer w0.64: 73.4,70.525 C186.2@73.4,70.955
  Top Layer w0.9: L6.2@67.85,71.6 68.65,71.6 68.85,71.4 C187.2@69.8,71.4 C19.2@71.6,71.4 C186.2@73.4,71.4
  Signal Layer 4 w0.15: v2(91.599,75.599) 91.971,75.971 91.962,75.98 ; v2@91.6,76.338 v2@91.6,76.342 ; v2(91.6,76.4) v2@91.6,76.342 ; 93.301,72.703 93.608,73.01 93.608,75.783 93.411,75.98 91.962,75.98 ; v2@91.6,76.342 91.962,75.98
  Signal Layer 4 w0.3: v3(61.284,81.027) 62.799,81.027 63.05,80.776 v3@63.075,80.776 ; v3(63.075,80.773) 63.129,80.773 63.44,81.084 64.543,81.084 64.973,81.513 65.931,81.513 66.455,80.989 66.455,78.601 67.456,77.6 72.999,77.6 73.551,77.048 73.551,75.156 73.951,74.756 73.951,72.573 73.752,72.375 v1(73.752,70.285) ; v2(91.575,69.975) 91.6,70 v2(91.6,71.6) 92.703,72.703 93.301,72.703
  Bottom Layer w0.2: C74.2@90.5,75.05 90.575,75.125 90.667,75.125 90.692,75.15 90.931,75.15 90.946,75.165 90.981,75.165 91.2,75.384 91.2,75.419 91.342,75.561 91.561,75.561 v2(91.599,75.599) 91.6,76.4 91.6,76.45 C73.2@91.125,76.925
  Bottom Layer w0.3: R260.2@60.33,81.68 R261.2@61.305,81.68 61.294,81.669 61.294,81.038 v3(61.284,81.027) ; C44.1@91.475,69.6 91.475,69.875 v2(91.575,69.975) 91.475,70.075 91.475,70.675 v2(91.6,70.8) 91.475,70.925 91.475,71.475 91.725,71.725 C46.2@92.025,71.725 ; C45.2@93.075,69.6 93.075,69.875 v2(93.2,70) v2@93.225,70
  other v1: 73.077,70.285
VDDIO_FB: LNK11.1 U26.17 | length 13.4
  Top Layer w0.15: U26.17@63.17,74 63.7,74 64.303,73.397 v3(64.315,73.397)
  Top Layer w0.2: LNK11.1@74.6,71.665 v3(74.6,73.4)
  Bottom Layer w0.15: v3(64.315,73.397) v3@74.597,73.397
VDDIO_SDCARD: C71.2 C217.1 U26.2 U27.G10 | length 65.5
  Top Layer w0.2: v2(92.4,76.4) U27.G10@92.8,76
  Top Layer w0.21: 57.459,71.873 57.8,72.214 U26.2@57.8,72.63
  Top Layer w0.3: C217.1@56.225,70.38 56.27,70.425 56.559,70.425 56.835,70.701 v3(56.835,70.737)
  Top Layer w0.4: C217.1@56.225,70.32 56.225,70.38 56.225,71.015 56.899,71.69 57.275,71.69 57.459,71.873
  Signal Layer 4 w0.5: v1(63.865,90.43) 63.867,90.432 82.942,90.432 v1(82.945,90.435)
  Bottom Layer w0.2: v2(92.4,76.4) 92.95,76.95 C71.2@93.201,76.95 93.201,77.799
  Bottom Layer w0.5: v3(56.835,70.737) 57.009,70.911 57.009,76.91 57.581,77.482 57.581,81.596 57.575,81.601 57.575,82.099 57.581,82.104 57.581,84.092 63.855,90.367 63.855,90.42 v1(63.865,90.43) ; v1@82.945,90.444 v1(82.945,90.435) 87.294,86.086 87.294,86.055 89.779,83.57 90.696,83.57 92.605,81.661 92.605,78.395 93.2,77.8
VREF+: C67.2 C68.2 R269.2 U27.Y5 | length 6.6
  Top Layer w0.2: U27.Y5@88.8,65.6 89.037,65.837 89.037,65.942 v2(89.076,65.981)
  Bottom Layer w0.2: R269.2@86.754,69.315 86.754,68.159 86.402,67.808 86.402,66.63 87.387,65.645 87.585,65.645 87.63,65.6 88.125,65.6 C68.2@88.375,65.85 88.904,65.85 89.035,65.981 v2(89.076,65.981)
VREF_DDR: C43.2 C147.2 C192.2 C362.2 C375.2 U14.H1 U14.M8 U16.H1 U16.M8 U26.45 | length 179.7
  Top Layer w0.1: v4(115.95,68.35) 116.609,68.35 117.034,67.925 U16.H1@117.1,67.925
  Top Layer w0.175: C362.2@129.925,65.75 129.925,65.775 130.159,66.008 v4@130.159,66.741 ; v4@130.135,66.75 130.135,66.853 129.987,67 129.987,68.163 U14.M8@130.376,68.552
  Top Layer w0.2: v4(113.7,60.525) 113.7,61.159 113.5,61.359 113.5,61.925 U16.M8@113.9,62.325
  Top Layer w0.21: 56.275,77.6 U26.45@56.83,77.6
  Top Layer w0.25: C43.2@50.485,76.8 50.485,77.341 v1@50.504,77.36 ; C43.2@50.515,76.79 53.231,76.79 53.676,77.235 53.951,77.235 54.316,77.6 56.275,77.6
  Top Layer w0.3: C375.2@113.475,59.625 113.58,59.73 v4@113.58,60.351 ; v4@133.025,74.635 v4(133.025,74.65) 133.05,74.65 133.55,74.15 U14.H1@133.575,74.15
  Signal Layer 2 w0.5: v4(113.7,60.525) 114.394,61.219 ; v4(115.95,68.35) 116.155,68.145 116.949,68.145 118.2,66.894 ; 130.151,65.33 v4(130.15,66.75) ; v4(133.025,74.65) 133.032,74.65 133.985,73.698
  Signal Layer 2 w0.7: v1(50.4,77.455) 50.222,77.633 50.222,79.06 55.087,83.925 63.802,83.925 65.477,82.25 102.84,82.25 103.365,81.725 136.925,81.725 142.513,76.137 v1(142.513,73.145) ; 114.394,61.219 116.288,61.219 117.094,62.025 121.555,62.025 122.85,63.319 124.728,63.319 126.739,65.33 ; 118.2,66.894 125.13,66.894 126.694,65.33 126.739,65.33 ; 133.985,73.698 141.961,73.698 v1(142.513,73.145) ; 126.739,65.33 130.151,65.33 139.015,65.33 142.513,68.828 v1(142.513,73.145)
  Bottom Layer w0.3: v4@115.95,68.325 116.146,68.521 116.146,68.621 116.675,69.15 C192.2@116.7,69.15 ; C147.2@132.85,75.525 132.912,75.463 132.912,74.688 v4@132.95,74.65
VTT_DDR: C40.2 C130.2 C131.2 C132.2 C133.2 C134.2 C159.2 C172.2 C185.2 C201.2 C205.2 C302.2 C304.2 C306.2 C307.2 C399.2 R148.2 R149.2 R150.2 R151.2 R152.2 R153.2 R154.2 R155.2 R158.2 R159.2 R160.2 R163.2 R166.2 R168.2 R170.2 R171.2 R172.2 R173.2 R174.2 R175.2 R176.2 R177.2 R178.2 R179.2 R180.2 U26.44 | length 122.1
  Top Layer w0.21: 56.275,78 U26.44@56.83,78
  Top Layer w0.25: v1(51.2,78.198) v1@51.202,78.196 ; v1@51.225,77.473 v1(51.202,77.473) 51.475,77.2 53.075,77.2 53.32,77.445 53.32,77.635 53.435,77.75 C40.2@53.505,77.75 ; C40.2@53.51,77.635 53.665,77.79 53.94,77.79 54.15,78 56.275,78
  Top Layer w0.5: v1(51.202,77.473) v1@51.202,78.196
  Signal Layer 4 w0.6: v1@51.2,77.475 v1(51.2,78.198)
  Signal Layer 4 w0.7: v1(51.2,78.198) 49.244,78.198 48.209,77.163 46.837,77.163 45.883,78.117 45.883,85.733 51.699,91.549 91.801,91.549 92.714,90.636 96.239,90.636 105.727,81.148 135.884,81.148 137.025,80.007 v1(137.025,79.7)
  Bottom Layer w0.8: C130.2@135.55,78.325 135.659,78.325 v1@137.025,79.691
pads on no net: U14.J1 U14.J9 U14.L1 U14.L9 U16.J1 U16.J9 U16.L1 U16.L9 U24.A1 U24.A2 U24.A7 U24.A8 U24.A9 U24.A10 U24.A11 U24.A12 U24.A13 U24.A14 U24.B1 U24.B7 U24.B8 U24.B9 U24.B10 U24.B11 U24.B12 U24.B13 U24.B14 U24.C1 U24.C3 U24.C5 U24.C7 U24.C8 U24.C9 U24.C10 U24.C11 U24.C12 U24.C13 U24.C14 U24.D1 U24.D2 U24.D3 U24.D4 U24.D12 U24.D13 U24.D14 U24.E1 U24.E2 U24.E3 U24.E5 U24.E8 U24.E9 U24.E10 U24.E12 U24.E13 U24.E14 U24.F1 U24.F2 U24.F3 U24.F10 U24.F12 U24.F13 U24.F14 U24.G1 U24.G2 U24.G3 U24.G10 U24.G12 U24.G13 U24.G14 U24.H1 U24.H2 U24.H3 U24.H12 U24.H13 U24.H14 U24.J1 U24.J2 U24.J3 U24.J12 U24.J13 U24.J14 U24.K1 U24.K2 U24.K3 U24.K6 U24.K7 U24.K10 U24.K12 U24.K13 U24.K14 U24.L1 U24.L2 U24.L3 U24.L12 U24.L13 U24.L14 U24.M1 U24.M2 U24.M3 U24.M7 U24.M8 U24.M9 U24.M10 U24.M11 U24.M12 U24.M13 U24.M14 U24.N1 U24.N3 U24.N6 U24.N7 U24.N8 U24.N9 U24.N10 U24.N11 U24.N12 U24.N13 U24.N14 U24.P1 U24.P2 U24.P7 U24.P8 U24.P9 U24.P10 U24.P11 U24.P12 U24.P13 U24.P14 U27.A2 U27.A3 U27.A4 U27.A7 U27.A8 U27.A11 U27.A12 U27.A15 U27.A16 U27.A21 U27.AA1 U27.AA2 U27.AA3 U27.AA4 U27.AA6 U27.AA7 U27.AA8 U27.AA10 U27.AA11 U27.AA12 U27.AA14 U27.AA15 U27.AA16 U27.AA18 U27.AA19 U27.AA20 U27.AA21 U27.AB2 U27.AB3 U27.AB4 U27.AB7 U27.AB8 U27.AB11 U27.AB12 U27.AB15 U27.AB16 U27.AB19 U27.AB20 U27.AB21 U27.B1 U27.B2 U27.B3 U27.B4 U27.B5 U27.B7 U27.B8 U27.B9 U27.B11 U27.B12 U27.B13 U27.B15 U27.B16 U27.B17 U27.B20 U27.B21 U27.C1 U27.C2 U27.C3 U27.C5 U27.C6 U27.C8 U27.C9 U27.C10 U27.C11 U27.C12 U27.C13 U27.C14 U27.C15 U27.C16 U27.C17 U27.C20 U27.D1 U27.D2 U27.D3 U27.D4 U27.D6 U27.D7 U27.D8 U27.D9 U27.D10 U27.D11 U27.D12 U27.D13 U27.D14 U27.D15 U27.D16 U27.D19 U27.E3 U27.E4 U27.E6 U27.E7 U27.E8 U27.E9 U27.E10 U27.E11 U27.E12 U27.E13 U27.E14 U27.E15 U27.E18 U27.F2 U27.F3 U27.F4 U27.F5 U27.F11 U27.F12 U27.F13 U27.F14 U27.F15 U27.G1 U27.G2 U27.G3 U27.G4 U27.G5 U27.G11 U27.G12 U27.G13 U27.G14 U27.G16 U27.H1 U27.H2 U27.H3 U27.H4 U27.H5 U27.H6 U27.J3 U27.J4 U27.J5 U27.J6 U27.J7 U27.K2 U27.K3 U27.K4 U27.K5 U27.K6 U27.K7 U27.K17 U27.L1 U27.L2 U27.L3 U27.L4 U27.L5 U27.L6 U27.L7 U27.L20 U27.M1 U27.M2 U27.M3 U27.M4 U27.M5 U27.M6 U27.N3 U27.N4 U27.N5 U27.N6 U27.P2 U27.P3 U27.P4 U27.P5 U27.R3 U27.R4 U27.R5 U27.R6 U27.T1 U27.T2 U27.T8 U27.T9 U27.T10 U27.T11 U27.T12 U27.T13 U27.T14 U27.T15 U27.T17 U27.T18 U27.U4 U27.U5 U27.U8 U27.U9 U27.U10 U27.U11 U27.U12 U27.U13 U27.U14 U27.U15 U27.U16 U27.U18 U27.U19 U27.V4 U27.V5 U27.V6 U27.V8 U27.V9 U27.V10 U27.V11 U27.V12 U27.V13 U27.V14 U27.V15 U27.V16 U27.V17 U27.W1 U27.W2 U27.W3 U27.W4 U27.W6 U27.W7 U27.W9 U27.W10 U27.W11 U27.W12 U27.W13 U27.W14 U27.W15 U27.W17 U27.Y1 U27.Y3 U27.Y4 U27.Y6 U27.Y7 U27.Y8 U27.Y9 U27.Y10 U27.Y11 U27.Y12 U27.Y13 U27.Y14 U27.Y15 U27.Y17 U27.Y18 U27.Y20
copper on no net: | length 334.2
  Top Layer w0.09: 81.172,76.702 85.898,76.702 86.105,76.495 88.305,76.495 88.8,76 ; 81.614,76.882 86.261,76.882 86.343,76.8 86.4,76.8 ; 81.76,77.09 86.513,77.09 86.803,76.8 87.2,76.8 ; 82.23,77.27 86.59,77.27 86.775,77.085 87.332,77.085 87.342,77.075 87.575,76.842 87.59,76.827 87.973,76.827 88,76.8 ; 82.334,77.52 86.693,77.52 86.898,77.315 87.427,77.315 87.437,77.305 87.657,77.085 88.515,77.085 88.8,76.8 ; 82.986,77.7 87.043,77.7 87.143,77.6 87.2,77.6 ; 83.083,77.935 87.665,77.935 88,77.6 ; 83.395,70.522 83.453,70.522 83.53,70.445 85.911,70.445 86.233,70.123 86.549,70.123 86.777,69.895 87.556,69.895 87.76,70.099 ; 83.448,70.265 85.754,70.265 86.124,69.895 86.522,69.895 86.817,69.6 87.2,69.6 ; 83.537,70.707 83.619,70.625 86.175,70.625 86.4,70.4 ; 83.604,70.895 83.694,70.805 86.412,70.805 86.695,70.522 86.695,70.28 86.9,70.075 87.406,70.075 87.731,70.4 88,70.4 ; 83.673,71.08 83.758,70.995 86.477,70.995 87.032,70.44 87.16,70.44 87.2,70.4 ; 83.685,78.115 85.718,78.115 86.003,78.4 86.4,78.4 ; 83.748,71.26 83.833,71.175 86.551,71.175 87.031,70.695 88.295,70.695 88.8,71.2 ; 83.789,78.365 85.565,78.365 85.6,78.4 ; 83.877,71.64 83.982,71.535 86.75,71.535 87.045,71.24 87.16,71.24 87.2,71.2 ; 84.075,71.875 84.235,71.715 86.827,71.715 87.047,71.495 88.295,71.495 88.8,72 ; 84.174,72.075 84.249,72 ; 84.615,68.995 85.224,68.995 85.354,69.125 87.525,69.125 88,69.6 ; 84.65,68.41 85.613,68.41 86.003,68.8 86.4,68.8 ; 84.862,74.565 86.439,74.565 86.939,75.065 87.011,75.065 87.146,75.2 87.2,75.2 ; 85.472,78.675 85.482,78.685 86.603,78.685 86.875,78.413 86.875,78.3 87.06,78.115 87.715,78.115 88,78.4 ; 85.472,78.925 85.482,78.915 86.642,78.915 87.157,78.4 87.2,78.4 ; 86.115,75.475 86.125,75.475 86.4,75.2 ; 86.865,75.665 87.2,76 ; 87.359,70.885 87.361,70.885 87.683,70.885 87.998,71.2 ; 87.424,60.877 89.925,63.377 89.925,64.197 90.105,64.377 90.105,65.305 90.4,65.6 ; 87.634,82.95 89.145,81.439 89.145,80.673 89.52,80.298 89.52,79.693 89.885,79.328 89.885,78.115 90.4,77.6 ; 87.634,60.832 90.105,63.303 90.105,64.122 90.4,64.417 90.4,64.8 ; 87.738,83.2 89.395,81.543 89.395,81.439 89.395,80.91 89.394,80.909 89.394,80.776 89.75,80.42 89.75,79.788 90.115,79.424 90.115,78.273 90.273,78.115 90.347,78.115 90.4,78.168 90.4,78.4 ; 87.796,81.5 88.106,81.19 88.285,81.011 88.285,79.715 88.8,79.2 ; 87.826,82.15 88.715,81.261 88.715,80.495 89.085,80.125 89.085,78.915 89.6,78.4 ; 87.87,60.813 90.4,63.343 90.4,64 ; 87.9,81.75 88.535,81.115 88.535,81.011 88.535,79.853 88.673,79.715 88.747,79.715 88.8,79.768 88.8,80 ; 87.93,82.4 88.965,81.365 88.965,80.599 89.335,80.229 89.335,79.053 89.473,78.915 89.547,78.915 89.6,78.968 89.6,79.2 ; 88.124,70.099 88.405,70.38 88.78,70.38 88.8,70.4 ; 89.745,63.452 89.745,64.271 89.925,64.451 89.925,65.925 90.4,66.4 ; v2@90.8,78 91.2,77.6 ; v2(90.846,66.845) 91.2,67.2 ; v2(90.846,67.645) 91.2,68 ; v2@90.865,65.226 v2(90.846,65.245) 91.2,65.6 ; v2(91.525,66.825) 91.575,66.825 91.95,67.2 92,67.2 ; 92.145,63.204 92.145,65.071 92.505,65.431 92.505,65.722 92.505,66.905 92.8,67.2 ; 92.325,62.976 92.325,64.997 92.603,65.275 92.744,65.275 92.8,65.331 92.8,65.6 ; 92.505,62.82 92.505,64.922 92.678,65.095 92.969,65.095 93.12,65.247 93.12,66.08 92.8,66.4 ; 92.765,62.66 92.765,64.346 92.825,64.406 92.825,64.775 92.8,64.8 ; v2(93.05,66.775) 93.294,67.019 93.364,67.019 93.545,67.2 93.6,67.2 ; 93.29,82.424 93.29,80.31 93.6,80 ; 93.6,76 v2@94,76.4 ; v2(93.898,66.003) 93.93,66.035 93.93,66.75 94.38,67.2 94.4,67.2 ; 93.925,62.425 93.925,65.173 94.105,65.353 94.105,65.722 94.25,65.868 94.25,66.239 94.4,66.389 94.4,66.4 ; v2(93.95,67.6) 94.35,68 94.4,68 ; 94.105,62.105 94.105,64.122 94.4,64.417 94.4,64.8 ; 94.4,61.975 94.4,64 ; 94.4,65.6 94.695,65.305 94.695,61.851 ; 95.045,81.28 95.045,80.533 94.915,80.403 94.915,79.882 95.2,79.597 95.2,79.2 ; 95.2,67.2 95.541,67.541 95.541,67.734 v2(95.6,67.793) ; 95.275,61.5 95.275,65 95.495,65.22 95.495,66.775 95.495,67.2 95.858,67.563 96.163,67.563 96.4,67.8 96.4,68.048 96,68.448 96,68.8 ; 95.455,61.383 95.455,64.913 95.675,65.133 95.675,66.875 96,67.2 ; 95.585,81.665 95.585,80.308 95.69,80.203 95.69,78.71 96,78.4 ; 95.635,61.266 95.635,64.838 96,65.203 96,65.6 ; 95.765,81.835 95.765,80.383 95.87,80.278 95.87,79.361 96,79.231 96,79.2 ; 95.833,61.167 95.833,64.576 96,64.743 96,64.8 ; 95.945,81.98 95.945,80.457 96.05,80.352 96.05,79.588 96.31,79.328 96.31,77.91 96,77.6 ; 96,66.4 96.295,66.105 96.295,64.62 96.081,64.406 96.081,61.118 ; 96,68 96,68.025 ; 96.125,82.2 96.125,80.532 96.23,80.427 96.23,79.663 96.49,79.403 96.49,78.8 96.49,78.71 96.8,78.4 ; 96.305,82.495 96.305,80.606 96.41,80.501 96.41,79.866 96.781,79.495 96.781,79.219 96.8,79.2 ; 96.315,60.815 96.315,64.385 96.475,64.545 96.475,66.875 96.8,67.2 ; 96.485,82.74 96.485,80.681 96.59,80.576 96.59,80.225 96.8,80.015 96.8,80 ; 97.6,78.762 98.09,79.252 98.09,80.244 98.245,80.399 98.245,83.761 ; 99.2,64.8 99.166,64.834 98.961,64.834 98.875,64.749 98.875,63.825 99.3,63.4 99.3,61.425 99.525,61.2 ; 99.2,65.6 99.192,65.592 99.192,65.381 99.035,65.224 98.997,65.224 98.625,64.852 98.625,63.721 99.05,63.296 99.05,61.321 99.275,61.096 ; 100,64 99.96,64.04 99.96,64.219 99.904,64.275 99.756,64.275 99.7,64.219 99.7,63.8 99.775,63.725 100.025,63.475 100.025,61.9 100.548,61.378 100.799,61.126 ; 100,64.8 99.96,64.76 99.96,64.581 99.904,64.525 99.622,64.525 99.45,64.354 99.45,63.696 99.775,63.371 99.775,61.796 100.361,61.211 100.549,61.022 ; 100.525,62.771 100.525,63.446 100.285,63.687 100.285,64.106 100.76,64.581 100.76,64.76 100.8,64.8 ; 100.775,62.875 100.775,63.55 100.535,63.79 100.535,63.937 100.588,63.989 100.709,63.989 100.72,64 100.8,64 ; 101.6,64 101.56,64.04 101.56,64.195 101.504,64.251 101.425,64.251 101.335,64.16 101.335,63.85 101.445,63.74 101.445,63.509 102,62.954 102.85,62.104 103.082,61.872 ; 101.6,64.8 101.56,64.76 101.56,64.585 101.5,64.525 101.346,64.525 101.085,64.264 101.085,63.746 101.195,63.637 101.195,63.543 101.195,63.406 101.75,62.85 102.6,62 102.832,61.768
  Top Layer w0.1: 81.172,76.29 85.72,76.29 86.01,76 86.4,76 ; 83.388,70.325 83.448,70.265 ; 83.838,62.335 84.635,63.132 84.635,63.791 85.244,64.4 86,64.4 86.4,64.8 ; 84.249,72 85.6,72 ; 84.29,68.41 84.65,68.41 ; 84.378,68.994 84.614,68.994 84.615,68.995 ; 84.412,68.8 85.6,68.8 ; 85.063,65.025 85.063,65.473 85.48,65.89 85.89,65.89 86.4,66.4 ; 85.199,73.085 85.394,73.28 85.792,73.28 86.162,72.91 86.236,72.91 86.346,72.8 86.4,72.8 ; 85.38,75.659 85.401,75.68 86.126,75.68 86.141,75.665 86.865,75.665 ; 85.459,75.469 85.48,75.49 85.79,75.49 85.805,75.475 86.115,75.475 ; v2(87.6,73.2) 88,73.6 ; 87.76,70.099 88.124,70.099 ; 87.914,74.011 89.989,74.011 90.4,73.6 ; 88,67.2 88,66.81 88.49,66.32 88.49,63.265 ; v2(88.4,72.4) 88.8,72.8 ; v2(88.4,73.2) 88.8,73.6 ; v2(88.4,74.8) 88.8,74.4 ; v2(88.4,75.6) 88.8,75.2 ; 88.722,63.227 88.722,64.601 89.31,65.189 89.31,65.72 89.6,66.01 89.6,66.4 ; 88.912,63.149 88.912,64.522 89.6,65.21 89.6,65.6 ; 89.102,63.07 89.102,64.302 89.6,64.8 ; v2(89.2,71.6) 89.6,72 ; v2(89.2,72.4) 89.6,72.8 ; v2(89.2,73.2) 89.6,73.6 ; v2(89.2,74.8) 89.6,74.4 ; v2(89.2,75.6) 89.6,75.2 ; v2(89.2,78) 89.6,77.6 ; v2(90.8,68.4) 91.2,68.8 ; v2(91.6,67.6) 92,68 ; v2(91.6,68.4) 92,68.8 ; v2(92.4,67.6) 92.8,68 ; v2(92.4,68.4) 92.8,68.8 ; 92.8,78.4 v2@93.2,78.8 ; v2(93.2,67.6) 93.6,68 ; v2(93.2,68.4) 93.6,68.8 ; v2(94,68.4) 94.4,68.8 ; 94.4,76.8 v2@94.8,77.2 ; v2(94.8,76.4) 95.2,76 ; v2(95.6,68.4) 96,68 ; 97.536,63.661 97.603,63.728 97.603,63.997 97.6,64 ; 97.6,64.8 97.6,64.439 97.89,64.149 97.89,63.88 97.823,63.813 97.823,63.637 97.756,63.569 ; 97.6,67.2 v2(98,66.8) ; 97.6,78.4 97.6,78.762 ; 98.35,61.975 98.08,62.245 98.08,64.88 98.48,65.28 98.48,65.466 98.4,65.546 98.4,65.6 ; 98.4,66.4 98.4,66.01 98.7,65.71 98.7,65.189 98.3,64.789 98.3,62.336 98.57,62.066 ; 98.4,67.2 98.643,66.957 98.643,66.857 v2(98.7,66.8)
  Top Layer w0.11: v2(94.65,66) 94.606,66 94.662,66.055 94.855,66.055 95.2,66.4 ; v2(94.8,66.8) 94.8,67.602 95.198,68 95.2,68 ; v2(94.8,69.075) 95.2,68.8 ; 96.8,80.8 96.8,82.85
  Top Layer w0.2: 88.8,67.2 88.827,67.2 89.103,66.924 89.226,66.924 v2(89.264,66.886) ; v2(90.01,73.23) 90.01,73.21 90.4,72.82 90.4,72.8
  Bottom Layer w0.11: v2@94.8,66.752 v2(94.8,66.8) ; v2@95.6,67.709 v2(95.6,67.793)
  Bottom Layer w0.2: v2@89.264,66.858 v2(89.264,66.886)
  other v2: 94,76.4 94.8,77.2 90.8,78 93.2,78.8 87.6,80.42

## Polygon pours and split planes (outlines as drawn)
GND on Bottom Layer "GND_L06" (solid, pour order 155): 0.225,137.075 172,137.075 172,-0.225 0.025,-0.225
5V_STLK on Bottom Layer "5V_STLK_L06" (solid, pour order 149): 42.715,94.735 42.76,94.78 72.14,94.78 72.14,59.34 72.155,59.325 42.73,59.325
VTT_DDR on Bottom Layer "VTT" (solid, pour order 154): 139.22,69.8 138.62,69.2 138.57,69.2 138.57,68.178 138.57,68.179 136.538,66.148 133.088,66.148 133.088,64.65 126.189,64.65 126.189,62.948 133.34,62.95 134.938,64.548 138.064,64.548 140.689,67.173 140.689,77.023 138.614,79.098 127.214,79.098 127.214,77.575 137.037,77.575 139.22,75.391
1V8 on Bottom Layer "1V8_L06" (solid, pour order 0): 84.939,76.533 84.939,85.255 86.38,85.255 86.38,82.845 86.37,82.843 92.23,82.843 92.23,77.2 90.71,77.2 90.71,81.299 87.934,81.299 87.934,79.63 87.966,79.598 89.365,79.159 89.365,76.533
VDD_DDR on Signal Layer 4 "VDD_DDR" (solid, remove dead copper, pour order 144): 49.219,81.75 49.222,81.753 52.781,81.753 53.197,81.337 53.197,79.055 52.613,78.471 49.219,78.471 48.216,77.468 46.918,77.468 46.246,78.14 46.246,85.378 50.853,89.985 96.44,89.985 98.8,87.625 105.625,80.8 133.525,80.8 139.962,74.363 139.962,68.619 136.118,64.775 126.5,64.775 120.3,58.575 107.267,58.575 100.423,65.419 100.425,65.422 100.425,65.587 97.173,68.84 96.42,68.84 96.21,69.05 96.21,70.609 95.239,71.579 95.239,73.188 97.557,75.506 97.557,77.268 97.557,80.298 95.32,82.536 93.76,84.095 49.539,84.095 49.219,83.775
GND on Signal Layer 4 "GND_L03" (solid, remove dead copper, pour order 152): 0,137 172,137 172,0 0,0
5V_STLK on Signal Layer 4 "5V_STLK_L05" (solid, pour order 150): 43.375,82.635 68.935,82.635 68.975,82.595 68.975,66.229 43.411,66.229
VDDIO on Signal Layer 4 "VDDIO_L05" (solid, remove dead copper, pour order 145): 93.852,70.39 93.235,69.772 91.585,69.772 89.378,67.564 74.378,67.564 72.553,69.389 72.553,71.646 73.945,73.038 93.024,73.038 93.852,72.21
VDDGPU on Signal Layer 4 "VDDGPU" (solid, remove dead copper, pour order 127): 95.348,72.122 95.348,71.47 95.61,71.208 98.541,68.277 98.541,64.841 91.09,57.39 77.655,57.39 69.27,65.607 69.27,70.917 66.599,73.523 66.599,75.759 68.13,77.29 73.63,77.29 73.63,72.863 72.549,71.782 72.549,69.54 74.374,67.715 89.374,67.715 91.607,69.923 93.267,69.923 93.441,70.097 93.441,70.49 92.994,71.003 92.994,72.331 95.14,72.331
3V3 on Signal Layer 4 "3V3_L03" (solid, remove dead copper, pour order 146): 58,61.394 57.939,61.394 37.983,61.394 35.711,61.394 35.711,67.822 35.711,84.011 44.436,84.011 44.436,73.55 45.447,72.539 58,72.539
VDDCORE on Signal Layer 4 "VDDCORE" (solid, remove dead copper, pour order 142): 93.118,75.605 93.118,77.055 91.173,79 73.745,79 73.745,73.019 93.843,73.019 93.843,74.83
VDDCPU on Signal Layer 4 "VDDCPU" (solid, remove dead copper, pour order 143): 97.516,75.448 94.844,72.776 94.833,72.775 92.631,72.775 92.631,76.645 92.631,77.532 91.618,78.545 66.455,78.545 66.455,80.62 66.505,80.67 66.175,81 60.143,81 60.055,80.912 59.116,81.85 49.319,81.85 49.219,81.75 49.219,83.775 50.843,85.4 59.717,85.4 60.603,84.513 60.603,84.5 93.355,84.5 97.516,80.339 97.516,76.697
1V8 on Signal Layer 4 "1V8" (solid, pour order 151): 60.675,96.6 60.675,93.472 101.693,93.472 101.752,83.21 115.76,83.21 117.725,85.175 117.725,96.6
GND on Top Layer "GND_L01" (solid, pour order 153): 0.178,137.102 0.303,136.977 172,136.977 172,-0.323 0.103,-0.323
3V3 on Top Layer "3V3" (solid, pour order 137): 44.387,68.548 44.562,68.373 50.91,68.373 52.212,69.675 52.212,70.523 44.588,70.523 44.387,70.323
5V_STLK on Top Layer "5V_STK" (solid, pour order 111): 54.01,75.62 54.667,75.62 54.85,75.803 54.85,75.463 54.367,74.98 54.01,74.98
VDDCPU on Top Layer "I_SENS_VDDCPU_P" (solid, pour order 133): 49.312,83.845 49.312,81.998 49.835,81.475 54.25,81.475 54.245,81.48 54.245,83.845
VDDCORE on Top Layer "I_SENS_VDDCORE_P" (solid, pour order 134): 72.507,84.74 75.389,81.858 75.389,75.631 75.394,75.626 73.94,75.626 73.395,76.171 73.395,80.872 73.022,81.245 71.375,81.245 67.015,81.245 67.005,84.74
VDDGPU on Top Layer "I_SENS_VDDGPU_P" (solid, pour order 135): 73.103,75.6 73.245,75.742 73.245,78.72 68.525,78.72 68.525,75.6
VDDIO on Top Layer "VDDIO" (solid, pour order 136): 62.495,78.77 62.495,80.568 63.03,81.103 63.212,81.103 63.65,80.664 63.65,80.123 62.95,79.423 62.95,78.77
NetL6_1 on Top Layer "NetL6_1" (solid, pour order 138): 64.875,73.863 65.338,73.4 66.6,73.4 66.6,71.1 66.598,71.098 65.301,71.098 65.301,72.722 64.875,73.148
GND on Signal Layer 1 "GND_L02" (solid, remove dead copper, pour order 99): -1,138 172,138 172,-1 -1,-1
GND on Signal Layer 3 "GND_L04_P156" (solid, pour order 156): 0,137 172,137 172,0 0,0
GND on Signal Layer 2 "GND_L03_P157" (solid, pour order 157): 0,137 172,137 172,0 0,0

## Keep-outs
Keep-Out Layer:
  lines w0.1: 133.661,133.38 142.561,133.38 142.561,135.53 133.661,135.53 133.661,133.38

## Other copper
Top Layer:
  rectangle net VDD_DDR: 47.155,73.8 50.125,75.6
  region net 5V_STLK: 56.73,80.524 56.631,80.425 56.275,80.425 cw(c56.275,80.775) 55.925,80.775 55.925,80.825 55.2,80.825 ccw(c55.2,80.75) 55.125,80.75 55.125,80.4 ccw(c55.327,80.397) 55.325,80.195 57.95,80.195 58.35,79.8 58.612,79.8 57.891,80.521 57.625,80.525
  region net 5V_STLK: 65.105,79.78 64.93,79.672 ccw(c65.063,79.473) 64.894,79.642 64.853,79.601 ccw(c65.113,79.342) 64.746,79.342 64.746,79.326 ccw(c65.101,79.326) 64.85,79.075 64.85,77.539 64.849,77.538 64.847,77.551 64.376,77.08 63.77,77.08 63.77,77.345 64.006,77.345 64.48,77.819 64.48,80.347 64.808,80.67 65.825,80.67 65.825,79.78
  region net GND: 56.4,79.685 56.307,79.685 ccw(c56.307,79.584) 56.235,79.655 55.955,79.375 ccw(c56.026,79.303) 55.925,79.303 55.925,78.975 56.425,78.975 cw(c56.823,78.982) 56.815,79.38 57.075,79.375 ccw(c57.075,79.423) 57.109,79.389 57.205,79.485
  region net GND: 63.725,76 63.65,75.925 63.572,75.925 cw(c63.572,75.798) 63.662,75.888 63.688,75.862 ccw(c63.778,75.952) 63.778,75.825 64.447,75.825 cw(c64.447,75.698) 64.537,75.788 64.6,75.725 64.729,75.854 cw(c64.78,75.803) 64.78,75.875
  region net NetL1_1: 59.072,81.875 ccw(c58.769,81.883) 58.978,82.102 58.955,82.125 58.955,82.187 59.026,82.194 ccw(c59.025,82.194) 59.025,82.195 59.175,82.075
  region net 5V_STLK: 65.695,78.175 65.695,77.32 65.625,77.25 65.5,77.375 64.9,77.375 65.055,77.53 65.055,78.175
  region net 5V_STLK: 65.625,77.25 65.05,76.675 64.375,76.675 64.375,76.85 64.9,77.375
  region net 5V_STLK: 54.375,72.9 54.216,72.9 54.189,72.874 54.148,72.842 54.102,72.815 54.054,72.795 54.003,72.782 53.951,72.775 53.925,72.774 53.425,72.774 53.399,72.775 53.347,72.782 53.296,72.795 53.248,72.815 53.202,72.842 53.161,72.874 53.15,72.45 53.15,71.945 52.875,71.945 52.875,71.305 53.33,71.305 54.099,72.074 54.099,72.184 54.103,72.227 54.113,72.27 54.129,72.31 54.152,72.346 54.18,72.379 54.538,72.737
  region net 5V_STLK: 51.575,71.948 52.225,71.948 52.225,71.305 51.92,71.305 51.825,71.4 51.575,71.4
  region net 5V_STLK: 54.75,75.62 54.75,75.4 54.33,74.98 52.65,74.98 52.65,75.525 52.9,75.525 52.995,75.62
  region net 5V_STLK: 65.575,73.875 65.575,74.125 64.675,75.025 65.425,75.025 65.747,74.703
  region net 5V_STLK: 65.575,73.85 65.477,73.948 65.477,74.625 66.12,74.625 66.12,73.895 66.075,73.85 66.075,73.6 65.575,73.6
  region net 5V_STLK: 58.675,81.85 58.77,81.755 58.77,81.45 58.13,81.45 58.13,81.805 58.175,81.85 58.175,82.1 58.675,82.1
  region net 5V_STLK: 58.925,79.725 58.9,79.725 58.13,80.495 58.13,80.825 58.77,80.825 58.77,80.605 58.9,80.475 58.9,79.925
  region net 5V_STLK: 65.675,81 65.825,80.85 65.825,80.6 65.025,80.6 65.025,80.85 65.175,81 65.175,81.25 65.675,81.25
  region net 5V_STLK: 65.625,79.35 65.775,79.2 65.775,78.95 64.975,78.95 64.975,79.2 65.125,79.35 65.125,79.6 65.625,79.6
  region net 5V_STLK: 54.75,81.3 54.795,81.345 55.15,81.345 55.15,80.65 54.9,80.65 54.75,80.8 54.5,80.8 54.5,81.3
  region net GND: 51.575,72.75 51.62,72.705 52.18,72.705 52.225,72.75 52.225,73.345 51.92,73.345 51.825,73.25 51.575,73.25
  region net GND: 50.525,72.798 50.675,72.648 50.675,72.398 49.8,72.398 49.8,72.823 50.025,73.048 50.525,73.048
  region net GND: 50.525,72.798 50.375,72.648 50.375,72.398 51.2,72.398 51.2,72.873 51.025,73.048 50.525,73.048
  region net GND: 72.3,73.298 72.3,74.651 70.9,74.651 70.9,73.298
  region net GND: 59.525,87.425 59.675,87.275 59.675,87.025 58.8,87.025 58.8,87.45 59.025,87.675 59.525,87.675
  region net GND: 59.525,87.425 59.375,87.275 59.375,87.025 60.2,87.025 60.2,87.5 60.025,87.675 59.525,87.675
  region net GND: 57.675,87.425 57.825,87.275 57.825,87.025 56.95,87.025 56.95,87.45 57.175,87.675 57.675,87.675
  region net GND: 57.675,87.425 57.525,87.275 57.525,87.025 58.35,87.025 58.35,87.5 58.175,87.675 57.675,87.675
  region net GND: 56.1,81.323 56.297,81.52 56.75,81.52 56.75,80.63 56.293,80.63 56.1,80.823
  region net GND: 45.125,72.798 44.975,72.648 44.975,72.398 45.8,72.398 45.8,72.873 45.625,73.048 45.125,73.048
  region net GND: 45.125,72.798 45.275,72.648 45.275,72.398 44.4,72.398 44.4,72.823 44.625,73.048 45.125,73.048
  region net GND: 46.925,72.798 46.775,72.648 46.775,72.398 47.6,72.398 47.6,72.873 47.425,73.048 46.925,73.048
  region net GND: 46.925,72.798 47.075,72.648 47.075,72.398 46.2,72.398 46.2,72.823 46.425,73.048 46.925,73.048
  region net GND: 45.1,74.7 45.295,74.895 46.075,74.895 46.075,74.005 45.295,74.005 45.1,74.2
  region net GND: 48.725,72.798 48.575,72.648 48.575,72.398 49.4,72.398 49.4,72.873 49.225,73.048 48.725,73.048
  region net GND: 48.725,72.798 48.875,72.648 48.875,72.398 48,72.398 48,72.823 48.225,73.048 48.725,73.048
  region net GND: 57.075,79.375 56.74,79.375 56.74,79.385
  region net GND: 63.421,78.656 63.52,78.656 63.549,78.653 63.578,78.644 63.604,78.63 63.627,78.612 63.645,78.589 63.67,78.555 63.67,78.23 63.77,78.23 63.77,78.93 63.421,78.93
  region net GND: 53.425,72.952 53.23,73.147 53.23,73.602 54.12,73.602 54.12,73.147 53.925,72.952
  region net GND: 64.33,76.125 64.78,76.125 64.78,75.825 64.655,75.7 64.48,75.875 64.33,75.875
  region net GND: 45.1,77.3 45.295,77.495 46.075,77.495 46.075,76.605 45.295,76.605 45.1,76.8
  region net GND: 45.1,76 45.295,76.195 46.075,76.195 46.075,75.305 45.295,75.305 45.1,75.5
  region net GND: 51.45,85.873 51.645,85.678 51.645,85.223 50.755,85.223 50.755,85.678 50.95,85.873
  region net GND: 52.75,85.873 52.945,85.678 52.945,85.223 52.055,85.223 52.055,85.678 52.25,85.873
  region net GND: 54.05,85.873 54.245,85.678 54.245,85.223 53.355,85.223 53.355,85.678 53.55,85.873
  region net GND: 55.775,83.373 55.97,83.178 55.97,82.723 55.08,82.723 55.08,83.178 55.275,83.373
  region net GND: 55.825,87.425 55.675,87.275 55.675,87.025 56.5,87.025 56.5,87.5 56.325,87.675 55.825,87.675
  region net GND: 55.825,87.425 55.975,87.275 55.975,87.025 55.1,87.025 55.1,87.45 55.325,87.675 55.825,87.675
  region net GND: 70.45,80.825 70.645,80.63 70.645,79.775 69.755,79.775 69.755,80.63 69.95,80.825
  region net GND: 69.15,80.825 69.345,80.63 69.345,79.775 68.455,79.775 68.455,80.63 68.65,80.825
  region net GND: 67.7,86.825 67.895,86.63 67.895,85.775 67.005,85.775 67.005,86.63 67.2,86.825
  region net GND: 74.1,73.298 74.1,74.651 72.7,74.651 72.7,73.298
  region net GND: 70.5,73.298 70.5,74.651 69.1,74.651 69.1,73.298
  region net GND: 73.05,80.825 73.245,80.63 73.245,79.775 72.355,79.775 72.355,80.63 72.55,80.825
  region net GND: 71.75,80.825 71.945,80.63 71.945,79.775 71.055,79.775 71.055,80.63 71.25,80.825
  region net GND: 68.975,86.825 69.17,86.63 69.17,85.775 68.28,85.775 68.28,86.63 68.475,86.825
  region net GND: 70.25,86.825 70.445,86.63 70.445,85.775 69.555,85.775 69.555,86.63 69.75,86.825
  region net GND: 71.525,86.825 71.72,86.63 71.72,85.775 70.83,85.775 70.83,86.63 71.025,86.825
  region net GND: 67.8,78.325 67.605,78.13 66.75,78.13 66.75,79.02 67.605,79.02 67.8,78.825
  region net GND: 67.825,79.975 67.63,79.78 66.775,79.78 66.775,80.67 67.63,80.67 67.825,80.475
  region net GND: 68.002,74.375 67.807,74.18 67.5,74.18 67.5,75.07 67.975,75.07 68.17,74.875 68.17,74.375
  region net VDD_DDR: 47.795,77.615 47.795,77.731 48.148,78.084 48.148,79.215 47.795,79.215 47.155,79.215 46.798,79.215 46.798,78.019 47.155,77.662 47.155,77.238 47.795,77.238
  region net VDDIO: 73.08,70.835 73.08,70.719 72.727,70.366 72.727,69.235 73.08,69.235 73.72,69.235 74.077,69.235 74.077,70.431 73.72,70.788 73.72,71.212 73.08,71.212
  pour cut-out: 74.825,62.125 78.033,62.125 78.26,62.125 78.785,61.6 78.785,59.714 78.283,59.211 74.825,59.211
  pour cut-out: 68.455,77.45 67.395,77.45 67.395,75.35 68.455,75.35
  pour cut-out: 74.1,71.925 69.13,71.925 69.13,72.575 74.1,72.575
  pour cut-out: 67.4,73.075 66.6,73.075 66.6,70.975 67.4,70.975
  pour cut-out: 67.355,72.875 69.13,72.875 69.13,71.6 67.8,71.6
  pour cut-out: 52.3,81.605 52.3,80.545 54.4,80.545 54.4,81.605
  pour cut-out: 66.945,83.25 65.885,83.25 65.885,81.15 66.945,81.15
  region net NetL1_1: 59.495,82.275 59.15,81.93 58.695,82.385 58.695,84.075 59.495,84.075
  pour cut-out: 58.655,84.225 57.935,84.225 57.935,82.125 58.655,82.125
  region net NetL2_1: 65.15,82.225 65.15,81.45 65.015,81.45 64.325,80.76 64.325,78 63.85,77.525 63.525,77.525 63.525,77.675 63.614,77.675 63.77,77.831 63.95,78.011 64.005,78.094 64.025,78.191 64.025,78.742 64.07,78.85 64.07,79.01 64.009,79.157 63.897,79.269 63.77,79.322 63.75,79.325 63.75,83.102 64.098,83.45 65.015,83.45 65.15,83.315 65.15,83.2
  region net NetL5_1: 50.925,75.948 51.15,76.173 52.525,76.173 52.525,74.323 52.002,73.8 51.725,73.8 50.925,73.8
  pour cut-out: 49.995,73.65 51.055,73.65 51.055,75.75 49.995,75.75
  region net NetL4_1: 66.025,77.6 66.025,75.6 66.934,75.6 66.934,77.6
  region net NetL7_1: 54.375,70.35 54.075,70.05 53.3,70.05 53.3,70.95 54.375,72.02
  region net NetL3_1: 54.075,78.975 52.888,80.162 53.988,80.162 54.075,80.075 57.68,80.075 57.92,79.835 56.29,79.835 56.267,79.833 56.248,79.829 56.22,79.82 56.201,79.813 56.175,79.799 56.158,79.788 56.135,79.769 55.841,79.474 55.822,79.452 55.811,79.435 55.802,79.419 55.79,79.39 55.786,79.378 55.781,79.362 55.777,79.342 55.776,79.327 55.774,79.313 55.774,78.975
  region net NetL3_1: 55.283,80.045 55.254,80.048 55.225,80.057 55.151,80.089 55.125,80.103 55.103,80.122 55.047,80.18 55.028,80.203 55.014,80.229 54.988,80.294 54.981,80.316 54.958,80.347 54.933,80.367 54.897,80.391 54.851,80.4 54.075,80.4 54.075,79.263
  pour cut-out: 53,72.6 51.05,72.6 51.05,72.025 53,72.025
  pour cut-out: 44.4,70.773 51.05,70.773 51.05,71.573 44.4,71.573
  pour cut-out: 53.44,71.1 52.38,71.1 52.38,69 53.44,69
  pour cut-out: 75.75,68.05 75.75,65.25 78.28,65.25 78.28,68.05
  pour cut-out: 106.875,94 107.125,94.25 114,94.25 114.175,94.075 114.175,87.1 114,86.925 107.15,86.925 106.875,87.2
  pour cut-out: 105.169,60.906 108.375,57.7 116.959,57.7 119.382,60.123 123.34,60.123 125.452,62.235 125.452,65.003 125.877,65.428 133.943,65.428 136.32,67.804 140.214,67.804 141.293,68.883 141.293,75.407 135.4,81.3 103.525,81.3 84.875,81.3 84.875,63.2 102.875,63.2
  text "1" at 134.025,133.811 h2
Signal Layer 1:
  text "2" at 135.309,133.811 h2
Signal Layer 4:
  text "5" at 140.661,133.833 h2
Bottom Layer:
  pour cut-out: 102.078,63.764 103.126,63.764 103.126,63.722 107.371,59.478 108.774,59.478 110.423,59.478 111.235,58.665 120.35,58.665 126.28,64.595 132.9,64.595 132.9,66.4 136.682,66.4 136.7,66.419 138.224,67.943 138.224,69.673 138.899,69.673 138.899,75.713 137.153,77.459 127.309,77.459 125.375,75.525 106.869,75.525 104.745,77.649 99.272,77.649 97.508,75.885 97.508,68.734 99.933,66.309 99.933,65.909
  text "6" at 142.16,133.822 h2

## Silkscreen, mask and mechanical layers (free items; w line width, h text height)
Top Overlay:
  text "J" at 38.481,119.842 h15
  text "VBAT" at 63.012,59.791 h1.2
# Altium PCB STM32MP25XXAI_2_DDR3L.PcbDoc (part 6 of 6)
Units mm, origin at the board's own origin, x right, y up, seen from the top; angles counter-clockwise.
Board outline 172 x 137 mm, 6 copper layers (Top Layer, Signal Layer 1, Signal Layer 2, Signal Layer 3, Signal Layer 4, Bottom Layer), stack 2.079 mm thick; 237 components, 152 nets, 1304 pads, 909 vias.
Unrouted connection lines stored in the file: 13.

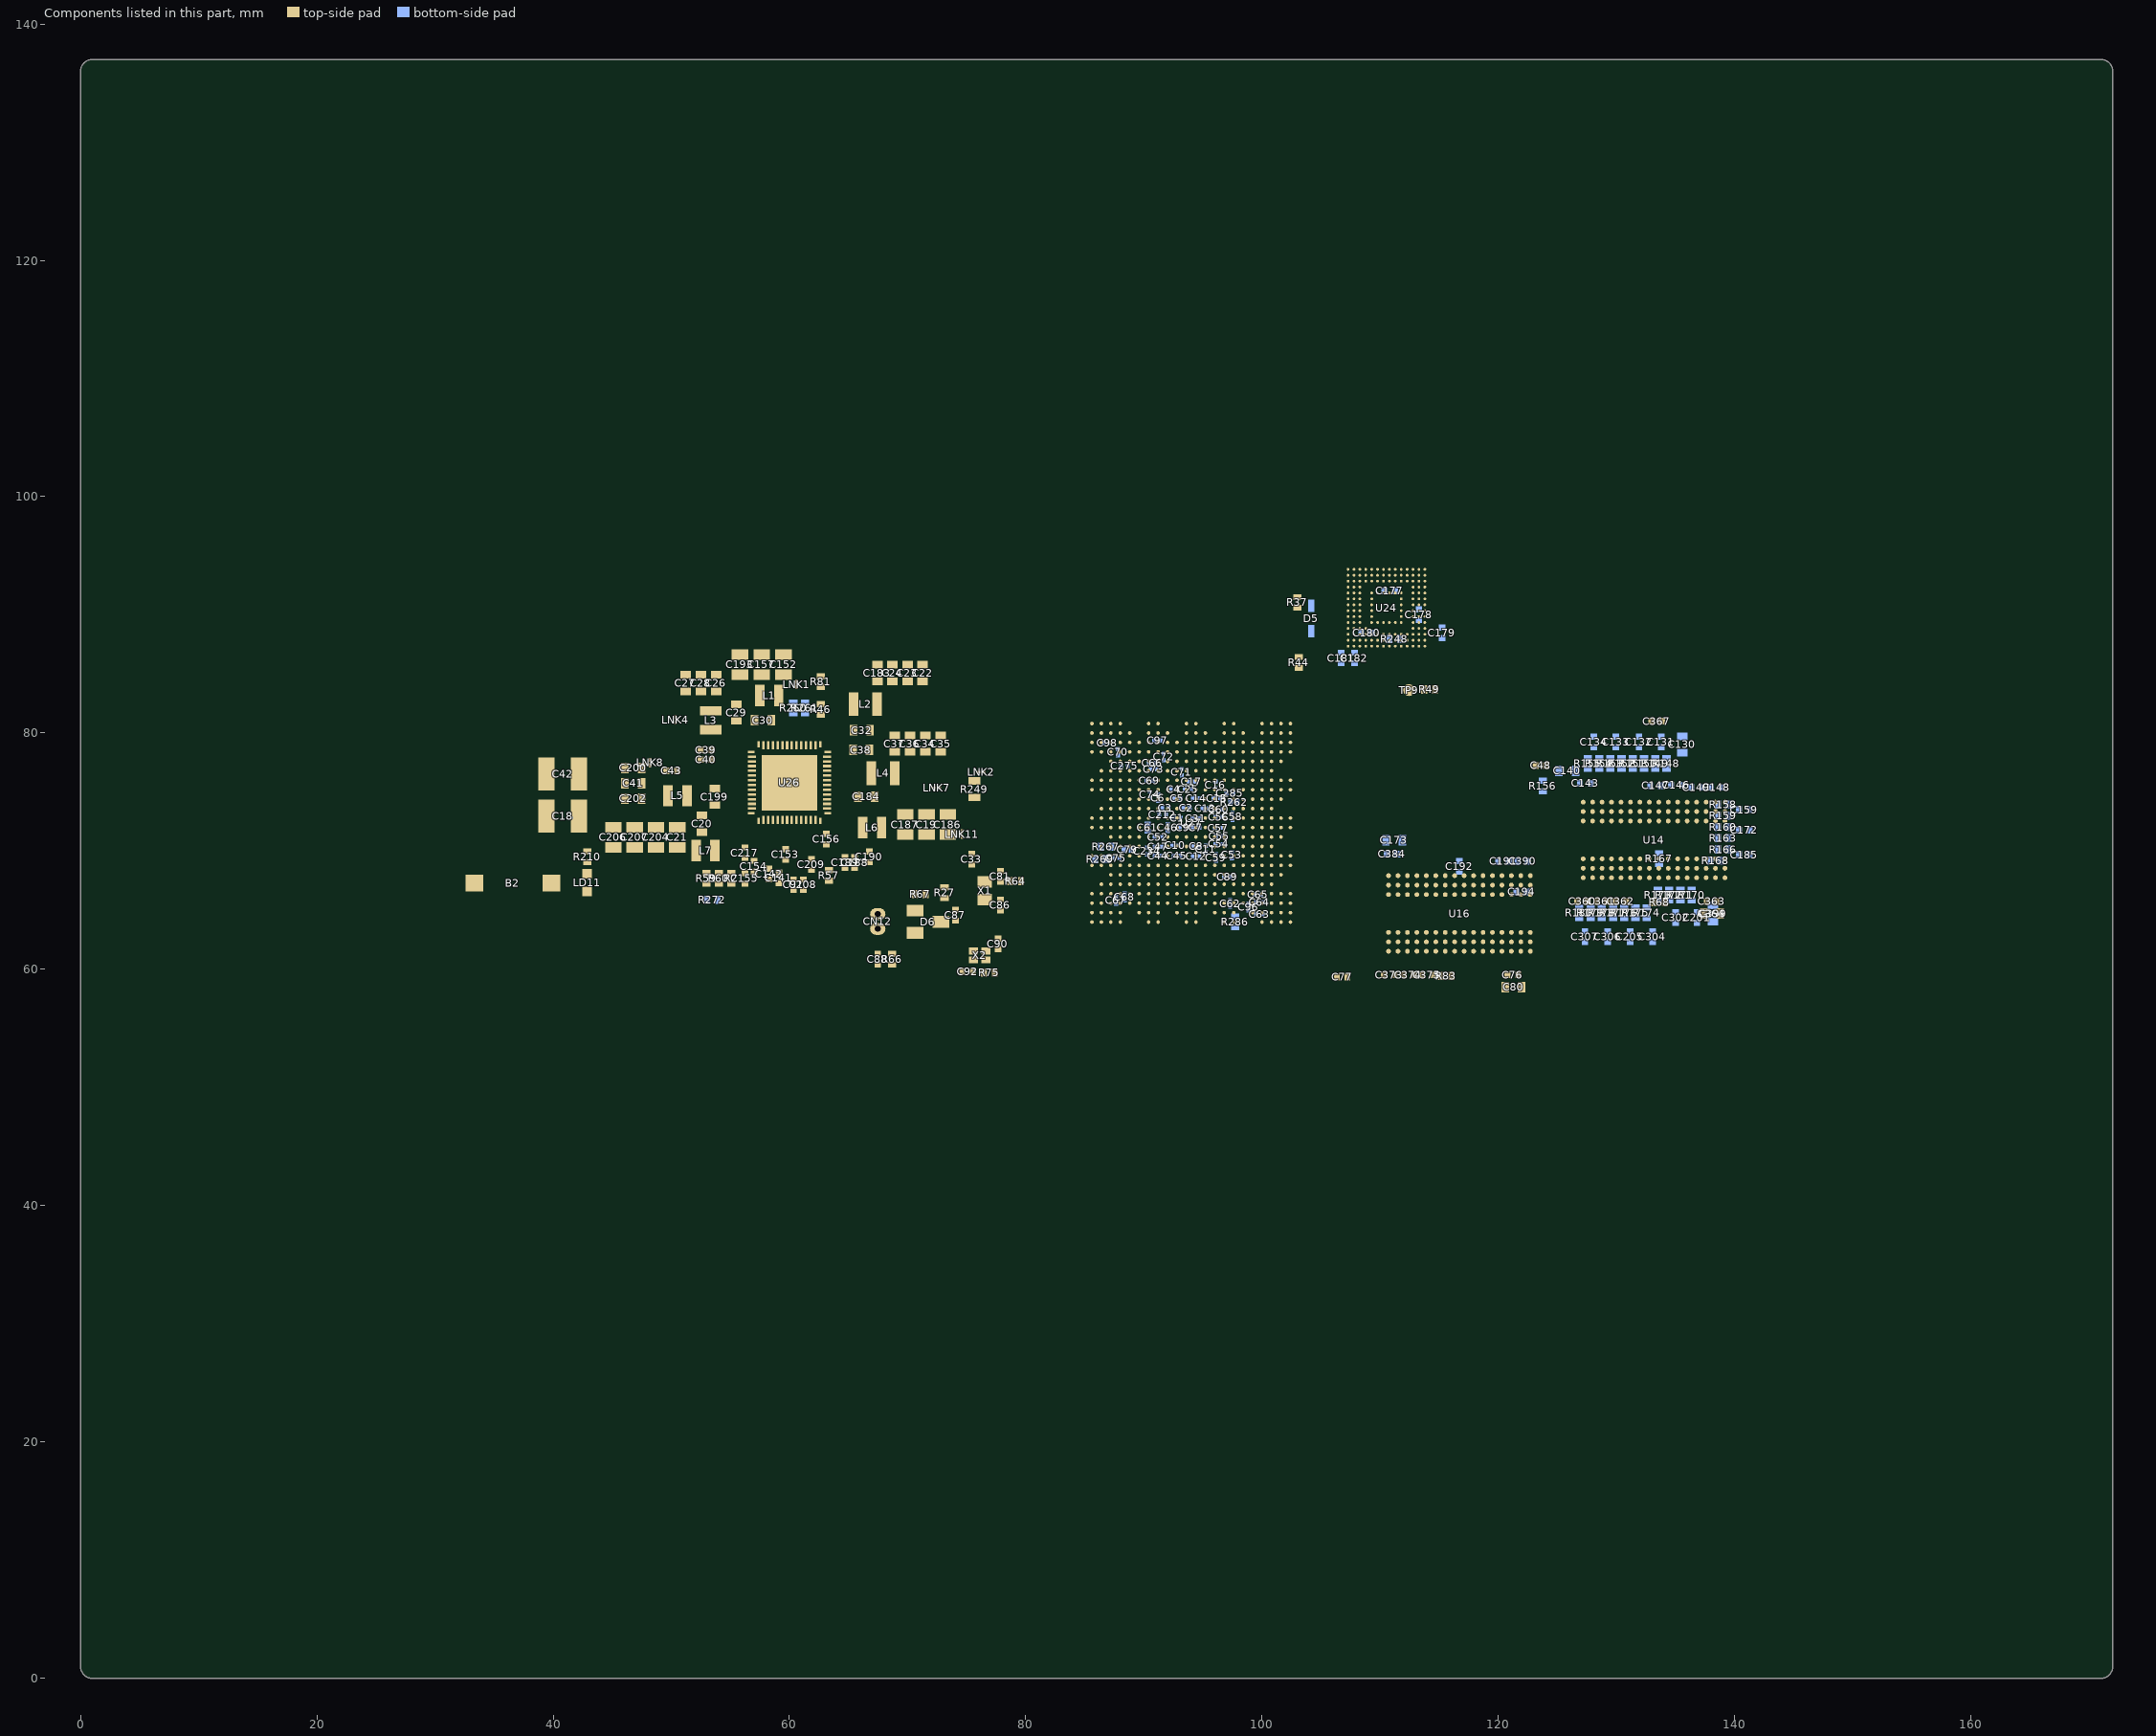
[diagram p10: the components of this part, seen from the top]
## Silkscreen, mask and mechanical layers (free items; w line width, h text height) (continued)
Top Solder:
  region: 133.736,135.455 133.736,133.455 142.486,133.455 142.486,135.455
Bottom Solder:
  region: 133.736,135.455 133.736,133.455 142.486,133.455 142.486,135.455
M1-Board Shape:
  lines w0.1: 1,137 ccw(c1,136) 0,136 0,95 0,1 ccw(c1,1) 1,0 171,0 ccw(c171,1) 172,1 172,136 ccw(c171,136) 171,137 ; 1,137 1,137 ; 1,137 171,137 ; 171,137 171,137
M2-Board Dimensions:
  lines w0.1: 1,137 ccw(c1,136) 0,136 0,1 ccw(c1,1) 1,0 171,0 ccw(c171,1) 172,1 172,136 ccw(c171,136) 171,137 ; 1,137 1,137 ; 1,137 171,137 ; 171,137 171,137
Drill Drawing:
  drawing of 203 lines, arcs and shapes, not listed
  text "PCB SPECIFICATIONS :" at 3.455,183.85 h3
  text "MINIMUN PARAMETERS" at 155.325,183.145 h3
  text "PCB : TYPE 3" at 194.663,183.121 h3
  text "Layer" at 244.479,182.45 h2
  text "Name" at 252.853,182.45 h2
  text "Material" at 269.05,182.45 h2
  text "Thickness" at 283.604,182.45 h2
  text "Constant" at 295.559,182.45 h2
  text "A.   MATERIAL :" at 3.455,179.85 h3
  text "FR-4" at 41.955,179.85 h3
  text "TG-170" at 58.455,179.85 h3
  text "X  TG-150" at 76.705,179.85 h3
  text "TG-140" at 92.705,179.85 h3
  text "Top Overlay" at 252.853,178.45 h2
  text "DEFAULT" at 155.325,177.645 h3
  text "ASPECT-RATIO, AXE Z :" at 194.663,177.621 h3
  text "B.   MATERIAL FAMILY :" at 3.455,176.85 h3
  text "N/A" at 41.955,176.85 h3
  text "Top Solder" at 252.853,174.45 h2
  text "Solder Resist" at 269.05,174.45 h2
  text "0.025mm" at 283.604,174.45 h2
  text "3.5" at 295.559,174.45 h2
  text "C.   SOLDERMASK COLOR :" at 3.455,173.85 h3
  text "GREEN" at 41.955,173.85 h3
  text "X  BLUE" at 58.455,173.85 h3
  text "RED" at 76.705,173.85 h3
  text "BLACK" at 92.705,173.85 h3
  text "TRACKS : 0.100mm           / GAPS : 0.100mm" at 155.325,171.895 h3
  text "6 :1  to  8 :1 / LEVEL \"B\"" at 194.682,170.874 h3
  text "D.   SILKSCREEN COLOR :" at 3.455,170.85 h3
  text "X  WHITE" at 41.955,170.85 h3
  text "YELLOW" at 58.455,170.85 h3
  text "BLACK" at 76.705,170.85 h3
  text "1" at 244.479,170.45 h2
  text "Top Layer" at 252.853,170.45 h2
  text "0.037mm" at 283.604,170.45 h2
  text "E.   SURFACE FINISH :" at 3.455,167.85 h3
  text "X  ENIG" at 41.955,167.85 h3
  text "IMMERSION SILVER" at 58.455,167.85 h3
  text "IMMERSION TIN" at 92.705,167.85 h3
  text "BGA :" at 155.3,167.07 h3
  text "Dielectric 1" at 252.853,166.45 h2
  text "0.072mm" at 283.604,166.45 h2
  text "3.8" at 295.559,166.45 h2
  text "HASL" at 41.955,164.85 h3
  text "HASL (PB-FREE)" at 58.455,164.85 h3
  text "GOLDEN FINGER" at 92.705,164.85 h3
  text "2" at 244.478,162.45 h2
  text "Signal Layer 1" at 252.853,162.45 h2
  text "0.035mm" at 283.604,162.45 h2
  text "F.   IMPEDANCE CONTROL :" at 3.455,161.85 h3
  text "NO" at 41.955,161.85 h3
  text "X  YES" at 58.455,161.85 h3
  text "TRACKS : 0.090mm           / GAPS : 0.090mm" at 155.3,161.32 h3
  text "G.   THROUGH VIA :" at 3.455,158.85 h3
  text "PLUG THE VIAS WHICH ARE COVERED WITH SOLDERMASK ONE OR TWO SIDE." at 41.955,158.85 h3
  text "Dielectric 2" at 252.853,158.45 h2
  text "0.500mm" at 283.604,158.45 h2
  text "5" at 295.559,158.45 h2
  text "PLUG MATERIAL :" at 41.955,155.85 h3
  text "X  SOLDERMASK" at 67.455,155.85 h3
  text "NON-CONDUCTIVE EPOXY." at 92.705,155.85 h3
  text "3" at 244.479,154.45 h2
  text "Signal Layer 2" at 252.853,154.45 h2
  text "0.300mm" at 283.604,154.45 h2
  text "H.   STACK-UP :" at 3.455,152.85 h3
  text "SEE LAYER STACK-UP SEQUENCE FOR OVERALL THICKNESS." at 41.955,152.85 h3
  text "Dielectric 3" at 252.853,150.45 h2
  text "0.191mm" at 283.604,150.45 h2
  text "4.3" at 295.559,150.45 h2
  text "4" at 244.479,146.45 h2
  text "Signal Layer 3" at 252.853,146.45 h2
  text "0.300mm" at 283.604,146.45 h2
  text "Dielectric 4" at 252.853,142.45 h2
  text "0.500mm" at 283.604,142.45 h2
  text "5" at 295.559,142.45 h2
  text "5" at 244.479,138.45 h2
  text "Signal Layer 4" at 252.853,138.45 h2
  text "0.035mm" at 283.604,138.45 h2
  text "Dielectric 5" at 252.853,134.45 h2
  text "0.072mm" at 283.604,134.45 h2
  text "3.8" at 295.559,134.45 h2
  text "6" at 244.479,130.45 h2
  text "Bottom Layer" at 252.853,130.45 h2
  text "0.037mm" at 283.604,130.45 h2
  text "Bottom Solder" at 252.853,126.45 h2
  text "Solder Resist" at 269.05,126.45 h2
  text "0.025mm" at 283.604,126.45 h2
  text "3.5" at 295.559,126.45 h2
  text "Bottom Overlay" at 252.853,122.45 h2
  text "Symbol" at 183.644,20.309 h2.4
  text "Count" at 193.043,20.309 h2.4
  text "Hole Size" at 202.799,20.309 h2.4
  text "Plated" at 221.075,20.309 h2.4
  text "Hole Type" at 229.326,20.309 h2.4
  text "Drill Layer Pair" at 241.338,20.309 h2.4
  text "Via/Pad" at 264.118,20.309 h2.4
  text "Pad Shape" at 273.961,20.309 h2.4
  text "Hole Length" at 286.819,20.309 h2.4
  text "343" at 193.043,16.166 h2
  text "0.200mm (7.87mil)" at 202.799,16.166 h2
  text "PTH" at 221.075,16.166 h2
  text "Round" at 229.326,16.166 h2
  text "Top Layer - Bottom Layer" at 241.338,16.166 h2
  text "Via" at 264.118,16.166 h2
  text "Rounded" at 273.961,16.166 h2
  text "-" at 286.819,16.166 h2
  text "D" at 182.856,15.912 h1.84
  text "145" at 193.043,12.023 h2
  text "0.250mm (9.84mil)" at 202.799,12.023 h2
  text "PTH" at 221.075,12.023 h2
  text "Round" at 229.326,12.023 h2
  text "Top Layer - Bottom Layer" at 241.338,12.023 h2
  text "Via" at 264.118,12.023 h2
  text "Rounded" at 273.961,12.023 h2
  text "-" at 286.819,12.023 h2
  text "E" at 182.856,11.769 h1.84
  text "421" at 193.043,7.88 h2
  text "0.350mm (13.78mil)" at 202.799,7.88 h2
  text "PTH" at 221.075,7.88 h2
  text "Round" at 229.326,7.88 h2
  text "Top Layer - Bottom Layer" at 241.338,7.88 h2
  text "Via" at 264.118,7.88 h2
  text "Rounded" at 273.961,7.88 h2
  text "-" at 286.819,7.88 h2
  text "F" at 182.856,7.626 h1.84
  text "2" at 193.043,3.737 h2
  text "0.500mm (19.69mil)" at 202.799,3.737 h2
  text "PTH" at 221.075,3.737 h2
  text "Round" at 229.326,3.737 h2
  text "Top Layer - Bottom Layer" at 241.338,3.737 h2
  text "Pad" at 264.118,3.737 h2
  text "Rounded" at 273.961,3.737 h2
  text "-" at 286.819,3.737 h2
  text "911 Total" at 193.043,-0.407 h2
